VERSION 5.8 ;
BUSBITCHARS "[]" ;
DIVIDERCHAR "/" ;
UNITS
    DATABASE MICRONS 1000 ;
END UNITS

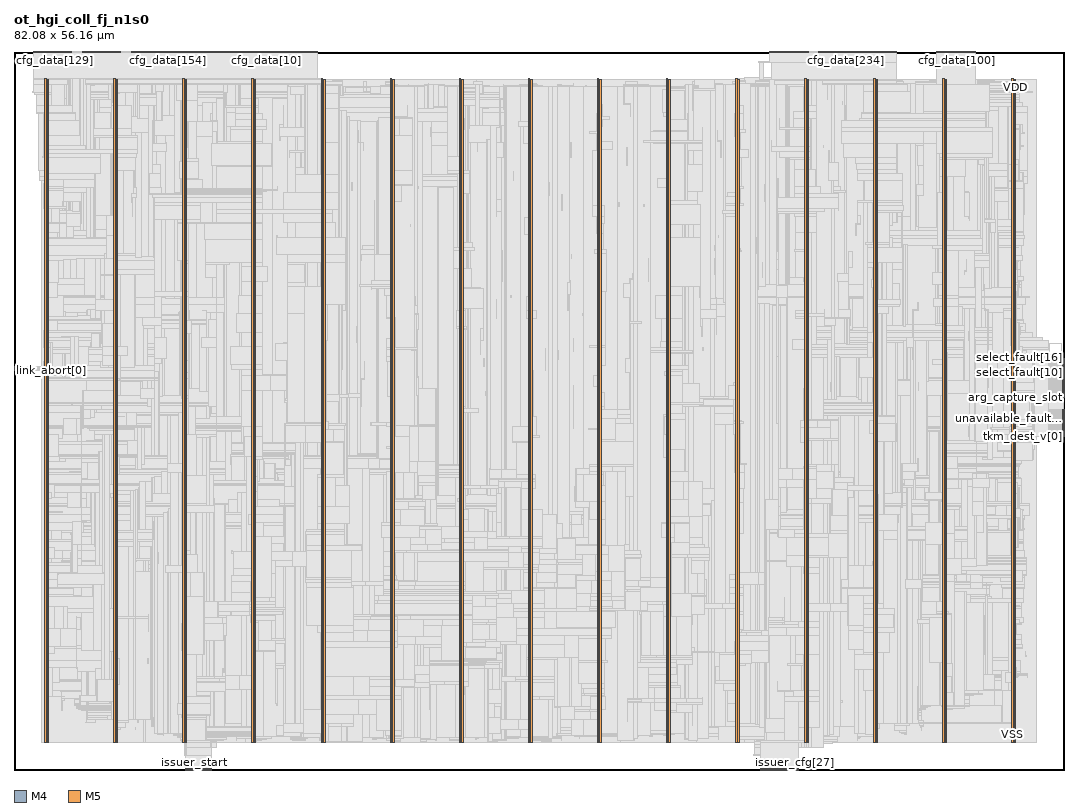
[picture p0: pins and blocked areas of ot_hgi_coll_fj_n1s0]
MACRO ot_hgi_coll_fj_n1s0
  FOREIGN ot_hgi_coll_fj_n1s0 0 0 ;
  CLASS BLOCK ;
  SIZE 82.08 BY 56.16 ;
  PIN arg_capture_slot
    DIRECTION INPUT ;
    USE SIGNAL ;
    PORT
      LAYER M4 ;
        RECT  81.996 29.136 82.08 29.16 ;
    END
  END arg_capture_slot
  PIN capture_fault[0]
    DIRECTION INPUT ;
    USE SIGNAL ;
    PORT
      LAYER M4 ;
        RECT  81.996 29.232 82.08 29.256 ;
    END
  END capture_fault[0]
  PIN capture_fault[1]
    DIRECTION INPUT ;
    USE SIGNAL ;
    PORT
      LAYER M4 ;
        RECT  81.996 29.328 82.08 29.352 ;
    END
  END capture_fault[1]
  PIN capture_fault[2]
    DIRECTION INPUT ;
    USE SIGNAL ;
    PORT
      LAYER M4 ;
        RECT  81.996 29.424 82.08 29.448 ;
    END
  END capture_fault[2]
  PIN capture_fault[3]
    DIRECTION INPUT ;
    USE SIGNAL ;
    PORT
      LAYER M4 ;
        RECT  81.996 29.52 82.08 29.544 ;
    END
  END capture_fault[3]
  PIN capture_fault[4]
    DIRECTION INPUT ;
    USE SIGNAL ;
    PORT
      LAYER M4 ;
        RECT  81.996 29.616 82.08 29.64 ;
    END
  END capture_fault[4]
  PIN capture_fault[5]
    DIRECTION INPUT ;
    USE SIGNAL ;
    PORT
      LAYER M4 ;
        RECT  81.996 29.712 82.08 29.736 ;
    END
  END capture_fault[5]
  PIN capture_fault[6]
    DIRECTION INPUT ;
    USE SIGNAL ;
    PORT
      LAYER M4 ;
        RECT  81.996 29.808 82.08 29.832 ;
    END
  END capture_fault[6]
  PIN capture_fault[7]
    DIRECTION INPUT ;
    USE SIGNAL ;
    PORT
      LAYER M4 ;
        RECT  81.996 29.904 82.08 29.928 ;
    END
  END capture_fault[7]
  PIN cfg_addr[0]
    DIRECTION INPUT ;
    USE SIGNAL ;
    PORT
      LAYER M5 ;
        RECT  17.616 56.076 17.64 56.16 ;
    END
  END cfg_addr[0]
  PIN cfg_addr[10]
    DIRECTION INPUT ;
    USE SIGNAL ;
    PORT
      LAYER M5 ;
        RECT  18.576 56.076 18.6 56.16 ;
    END
  END cfg_addr[10]
  PIN cfg_addr[11]
    DIRECTION INPUT ;
    USE SIGNAL ;
    PORT
      LAYER M5 ;
        RECT  18.672 56.076 18.696 56.16 ;
    END
  END cfg_addr[11]
  PIN cfg_addr[1]
    DIRECTION INPUT ;
    USE SIGNAL ;
    PORT
      LAYER M5 ;
        RECT  17.712 56.076 17.736 56.16 ;
    END
  END cfg_addr[1]
  PIN cfg_addr[2]
    DIRECTION INPUT ;
    USE SIGNAL ;
    PORT
      LAYER M5 ;
        RECT  17.808 56.076 17.832 56.16 ;
    END
  END cfg_addr[2]
  PIN cfg_addr[3]
    DIRECTION INPUT ;
    USE SIGNAL ;
    PORT
      LAYER M5 ;
        RECT  17.904 56.076 17.928 56.16 ;
    END
  END cfg_addr[3]
  PIN cfg_addr[4]
    DIRECTION INPUT ;
    USE SIGNAL ;
    PORT
      LAYER M5 ;
        RECT  18 56.076 18.024 56.16 ;
    END
  END cfg_addr[4]
  PIN cfg_addr[5]
    DIRECTION INPUT ;
    USE SIGNAL ;
    PORT
      LAYER M5 ;
        RECT  18.096 56.076 18.12 56.16 ;
    END
  END cfg_addr[5]
  PIN cfg_addr[6]
    DIRECTION INPUT ;
    USE SIGNAL ;
    PORT
      LAYER M5 ;
        RECT  18.192 56.076 18.216 56.16 ;
    END
  END cfg_addr[6]
  PIN cfg_addr[7]
    DIRECTION INPUT ;
    USE SIGNAL ;
    PORT
      LAYER M5 ;
        RECT  18.288 56.076 18.312 56.16 ;
    END
  END cfg_addr[7]
  PIN cfg_addr[8]
    DIRECTION INPUT ;
    USE SIGNAL ;
    PORT
      LAYER M5 ;
        RECT  18.384 56.076 18.408 56.16 ;
    END
  END cfg_addr[8]
  PIN cfg_addr[9]
    DIRECTION INPUT ;
    USE SIGNAL ;
    PORT
      LAYER M5 ;
        RECT  18.48 56.076 18.504 56.16 ;
    END
  END cfg_addr[9]
  PIN cfg_data[0]
    DIRECTION INPUT ;
    USE SIGNAL ;
    PORT
      LAYER M5 ;
        RECT  18.768 56.076 18.792 56.16 ;
    END
  END cfg_data[0]
  PIN cfg_data[100]
    DIRECTION INPUT ;
    USE SIGNAL ;
    PORT
      LAYER M5 ;
        RECT  73.68 56.076 73.704 56.16 ;
    END
  END cfg_data[100]
  PIN cfg_data[101]
    DIRECTION INPUT ;
    USE SIGNAL ;
    PORT
      LAYER M5 ;
        RECT  73.776 56.076 73.8 56.16 ;
    END
  END cfg_data[101]
  PIN cfg_data[102]
    DIRECTION INPUT ;
    USE SIGNAL ;
    PORT
      LAYER M5 ;
        RECT  73.872 56.076 73.896 56.16 ;
    END
  END cfg_data[102]
  PIN cfg_data[103]
    DIRECTION INPUT ;
    USE SIGNAL ;
    PORT
      LAYER M5 ;
        RECT  73.968 56.076 73.992 56.16 ;
    END
  END cfg_data[103]
  PIN cfg_data[104]
    DIRECTION INPUT ;
    USE SIGNAL ;
    PORT
      LAYER M5 ;
        RECT  74.064 56.076 74.088 56.16 ;
    END
  END cfg_data[104]
  PIN cfg_data[105]
    DIRECTION INPUT ;
    USE SIGNAL ;
    PORT
      LAYER M5 ;
        RECT  74.16 56.076 74.184 56.16 ;
    END
  END cfg_data[105]
  PIN cfg_data[106]
    DIRECTION INPUT ;
    USE SIGNAL ;
    PORT
      LAYER M5 ;
        RECT  74.256 56.076 74.28 56.16 ;
    END
  END cfg_data[106]
  PIN cfg_data[107]
    DIRECTION INPUT ;
    USE SIGNAL ;
    PORT
      LAYER M5 ;
        RECT  74.352 56.076 74.376 56.16 ;
    END
  END cfg_data[107]
  PIN cfg_data[108]
    DIRECTION INPUT ;
    USE SIGNAL ;
    PORT
      LAYER M5 ;
        RECT  74.448 56.076 74.472 56.16 ;
    END
  END cfg_data[108]
  PIN cfg_data[109]
    DIRECTION INPUT ;
    USE SIGNAL ;
    PORT
      LAYER M5 ;
        RECT  74.544 56.076 74.568 56.16 ;
    END
  END cfg_data[109]
  PIN cfg_data[10]
    DIRECTION INPUT ;
    USE SIGNAL ;
    PORT
      LAYER M5 ;
        RECT  19.728 56.076 19.752 56.16 ;
    END
  END cfg_data[10]
  PIN cfg_data[110]
    DIRECTION INPUT ;
    USE SIGNAL ;
    PORT
      LAYER M5 ;
        RECT  74.64 56.076 74.664 56.16 ;
    END
  END cfg_data[110]
  PIN cfg_data[111]
    DIRECTION INPUT ;
    USE SIGNAL ;
    PORT
      LAYER M5 ;
        RECT  74.736 56.076 74.76 56.16 ;
    END
  END cfg_data[111]
  PIN cfg_data[112]
    DIRECTION INPUT ;
    USE SIGNAL ;
    PORT
      LAYER M5 ;
        RECT  74.832 56.076 74.856 56.16 ;
    END
  END cfg_data[112]
  PIN cfg_data[113]
    DIRECTION INPUT ;
    USE SIGNAL ;
    PORT
      LAYER M5 ;
        RECT  74.928 56.076 74.952 56.16 ;
    END
  END cfg_data[113]
  PIN cfg_data[114]
    DIRECTION INPUT ;
    USE SIGNAL ;
    PORT
      LAYER M5 ;
        RECT  75.024 56.076 75.048 56.16 ;
    END
  END cfg_data[114]
  PIN cfg_data[115]
    DIRECTION INPUT ;
    USE SIGNAL ;
    PORT
      LAYER M5 ;
        RECT  75.12 56.076 75.144 56.16 ;
    END
  END cfg_data[115]
  PIN cfg_data[116]
    DIRECTION INPUT ;
    USE SIGNAL ;
    PORT
      LAYER M5 ;
        RECT  1.488 56.076 1.512 56.16 ;
    END
  END cfg_data[116]
  PIN cfg_data[117]
    DIRECTION INPUT ;
    USE SIGNAL ;
    PORT
      LAYER M5 ;
        RECT  1.584 56.076 1.608 56.16 ;
    END
  END cfg_data[117]
  PIN cfg_data[118]
    DIRECTION INPUT ;
    USE SIGNAL ;
    PORT
      LAYER M5 ;
        RECT  1.68 56.076 1.704 56.16 ;
    END
  END cfg_data[118]
  PIN cfg_data[119]
    DIRECTION INPUT ;
    USE SIGNAL ;
    PORT
      LAYER M5 ;
        RECT  1.776 56.076 1.8 56.16 ;
    END
  END cfg_data[119]
  PIN cfg_data[11]
    DIRECTION INPUT ;
    USE SIGNAL ;
    PORT
      LAYER M5 ;
        RECT  19.824 56.076 19.848 56.16 ;
    END
  END cfg_data[11]
  PIN cfg_data[120]
    DIRECTION INPUT ;
    USE SIGNAL ;
    PORT
      LAYER M5 ;
        RECT  1.872 56.076 1.896 56.16 ;
    END
  END cfg_data[120]
  PIN cfg_data[121]
    DIRECTION INPUT ;
    USE SIGNAL ;
    PORT
      LAYER M5 ;
        RECT  1.968 56.076 1.992 56.16 ;
    END
  END cfg_data[121]
  PIN cfg_data[122]
    DIRECTION INPUT ;
    USE SIGNAL ;
    PORT
      LAYER M5 ;
        RECT  2.064 56.076 2.088 56.16 ;
    END
  END cfg_data[122]
  PIN cfg_data[123]
    DIRECTION INPUT ;
    USE SIGNAL ;
    PORT
      LAYER M5 ;
        RECT  2.16 56.076 2.184 56.16 ;
    END
  END cfg_data[123]
  PIN cfg_data[124]
    DIRECTION INPUT ;
    USE SIGNAL ;
    PORT
      LAYER M5 ;
        RECT  2.256 56.076 2.28 56.16 ;
    END
  END cfg_data[124]
  PIN cfg_data[125]
    DIRECTION INPUT ;
    USE SIGNAL ;
    PORT
      LAYER M5 ;
        RECT  2.352 56.076 2.376 56.16 ;
    END
  END cfg_data[125]
  PIN cfg_data[126]
    DIRECTION INPUT ;
    USE SIGNAL ;
    PORT
      LAYER M5 ;
        RECT  2.448 56.076 2.472 56.16 ;
    END
  END cfg_data[126]
  PIN cfg_data[127]
    DIRECTION INPUT ;
    USE SIGNAL ;
    PORT
      LAYER M5 ;
        RECT  2.544 56.076 2.568 56.16 ;
    END
  END cfg_data[127]
  PIN cfg_data[128]
    DIRECTION INPUT ;
    USE SIGNAL ;
    PORT
      LAYER M5 ;
        RECT  2.64 56.076 2.664 56.16 ;
    END
  END cfg_data[128]
  PIN cfg_data[129]
    DIRECTION INPUT ;
    USE SIGNAL ;
    PORT
      LAYER M5 ;
        RECT  2.736 56.076 2.76 56.16 ;
    END
  END cfg_data[129]
  PIN cfg_data[12]
    DIRECTION INPUT ;
    USE SIGNAL ;
    PORT
      LAYER M5 ;
        RECT  19.92 56.076 19.944 56.16 ;
    END
  END cfg_data[12]
  PIN cfg_data[130]
    DIRECTION INPUT ;
    USE SIGNAL ;
    PORT
      LAYER M5 ;
        RECT  2.832 56.076 2.856 56.16 ;
    END
  END cfg_data[130]
  PIN cfg_data[131]
    DIRECTION INPUT ;
    USE SIGNAL ;
    PORT
      LAYER M5 ;
        RECT  2.928 56.076 2.952 56.16 ;
    END
  END cfg_data[131]
  PIN cfg_data[132]
    DIRECTION INPUT ;
    USE SIGNAL ;
    PORT
      LAYER M5 ;
        RECT  3.024 56.076 3.048 56.16 ;
    END
  END cfg_data[132]
  PIN cfg_data[133]
    DIRECTION INPUT ;
    USE SIGNAL ;
    PORT
      LAYER M5 ;
        RECT  3.12 56.076 3.144 56.16 ;
    END
  END cfg_data[133]
  PIN cfg_data[134]
    DIRECTION INPUT ;
    USE SIGNAL ;
    PORT
      LAYER M5 ;
        RECT  3.216 56.076 3.24 56.16 ;
    END
  END cfg_data[134]
  PIN cfg_data[135]
    DIRECTION INPUT ;
    USE SIGNAL ;
    PORT
      LAYER M5 ;
        RECT  3.312 56.076 3.336 56.16 ;
    END
  END cfg_data[135]
  PIN cfg_data[136]
    DIRECTION INPUT ;
    USE SIGNAL ;
    PORT
      LAYER M5 ;
        RECT  3.408 56.076 3.432 56.16 ;
    END
  END cfg_data[136]
  PIN cfg_data[137]
    DIRECTION INPUT ;
    USE SIGNAL ;
    PORT
      LAYER M5 ;
        RECT  3.504 56.076 3.528 56.16 ;
    END
  END cfg_data[137]
  PIN cfg_data[138]
    DIRECTION INPUT ;
    USE SIGNAL ;
    PORT
      LAYER M5 ;
        RECT  3.6 56.076 3.624 56.16 ;
    END
  END cfg_data[138]
  PIN cfg_data[139]
    DIRECTION INPUT ;
    USE SIGNAL ;
    PORT
      LAYER M5 ;
        RECT  3.696 56.076 3.72 56.16 ;
    END
  END cfg_data[139]
  PIN cfg_data[13]
    DIRECTION INPUT ;
    USE SIGNAL ;
    PORT
      LAYER M5 ;
        RECT  20.016 56.076 20.04 56.16 ;
    END
  END cfg_data[13]
  PIN cfg_data[140]
    DIRECTION INPUT ;
    USE SIGNAL ;
    PORT
      LAYER M5 ;
        RECT  3.792 56.076 3.816 56.16 ;
    END
  END cfg_data[140]
  PIN cfg_data[141]
    DIRECTION INPUT ;
    USE SIGNAL ;
    PORT
      LAYER M5 ;
        RECT  3.888 56.076 3.912 56.16 ;
    END
  END cfg_data[141]
  PIN cfg_data[142]
    DIRECTION INPUT ;
    USE SIGNAL ;
    PORT
      LAYER M5 ;
        RECT  3.984 56.076 4.008 56.16 ;
    END
  END cfg_data[142]
  PIN cfg_data[143]
    DIRECTION INPUT ;
    USE SIGNAL ;
    PORT
      LAYER M5 ;
        RECT  4.08 56.076 4.104 56.16 ;
    END
  END cfg_data[143]
  PIN cfg_data[144]
    DIRECTION INPUT ;
    USE SIGNAL ;
    PORT
      LAYER M5 ;
        RECT  4.176 56.076 4.2 56.16 ;
    END
  END cfg_data[144]
  PIN cfg_data[145]
    DIRECTION INPUT ;
    USE SIGNAL ;
    PORT
      LAYER M5 ;
        RECT  4.272 56.076 4.296 56.16 ;
    END
  END cfg_data[145]
  PIN cfg_data[146]
    DIRECTION INPUT ;
    USE SIGNAL ;
    PORT
      LAYER M5 ;
        RECT  4.368 56.076 4.392 56.16 ;
    END
  END cfg_data[146]
  PIN cfg_data[147]
    DIRECTION INPUT ;
    USE SIGNAL ;
    PORT
      LAYER M5 ;
        RECT  4.464 56.076 4.488 56.16 ;
    END
  END cfg_data[147]
  PIN cfg_data[148]
    DIRECTION INPUT ;
    USE SIGNAL ;
    PORT
      LAYER M5 ;
        RECT  11.472 56.076 11.496 56.16 ;
    END
  END cfg_data[148]
  PIN cfg_data[149]
    DIRECTION INPUT ;
    USE SIGNAL ;
    PORT
      LAYER M5 ;
        RECT  11.568 56.076 11.592 56.16 ;
    END
  END cfg_data[149]
  PIN cfg_data[14]
    DIRECTION INPUT ;
    USE SIGNAL ;
    PORT
      LAYER M5 ;
        RECT  20.112 56.076 20.136 56.16 ;
    END
  END cfg_data[14]
  PIN cfg_data[150]
    DIRECTION INPUT ;
    USE SIGNAL ;
    PORT
      LAYER M5 ;
        RECT  11.664 56.076 11.688 56.16 ;
    END
  END cfg_data[150]
  PIN cfg_data[151]
    DIRECTION INPUT ;
    USE SIGNAL ;
    PORT
      LAYER M5 ;
        RECT  11.76 56.076 11.784 56.16 ;
    END
  END cfg_data[151]
  PIN cfg_data[152]
    DIRECTION INPUT ;
    USE SIGNAL ;
    PORT
      LAYER M5 ;
        RECT  11.856 56.076 11.88 56.16 ;
    END
  END cfg_data[152]
  PIN cfg_data[153]
    DIRECTION INPUT ;
    USE SIGNAL ;
    PORT
      LAYER M5 ;
        RECT  11.952 56.076 11.976 56.16 ;
    END
  END cfg_data[153]
  PIN cfg_data[154]
    DIRECTION INPUT ;
    USE SIGNAL ;
    PORT
      LAYER M5 ;
        RECT  12.048 56.076 12.072 56.16 ;
    END
  END cfg_data[154]
  PIN cfg_data[155]
    DIRECTION INPUT ;
    USE SIGNAL ;
    PORT
      LAYER M5 ;
        RECT  12.144 56.076 12.168 56.16 ;
    END
  END cfg_data[155]
  PIN cfg_data[156]
    DIRECTION INPUT ;
    USE SIGNAL ;
    PORT
      LAYER M5 ;
        RECT  12.24 56.076 12.264 56.16 ;
    END
  END cfg_data[156]
  PIN cfg_data[157]
    DIRECTION INPUT ;
    USE SIGNAL ;
    PORT
      LAYER M5 ;
        RECT  12.336 56.076 12.36 56.16 ;
    END
  END cfg_data[157]
  PIN cfg_data[158]
    DIRECTION INPUT ;
    USE SIGNAL ;
    PORT
      LAYER M5 ;
        RECT  12.432 56.076 12.456 56.16 ;
    END
  END cfg_data[158]
  PIN cfg_data[159]
    DIRECTION INPUT ;
    USE SIGNAL ;
    PORT
      LAYER M5 ;
        RECT  12.528 56.076 12.552 56.16 ;
    END
  END cfg_data[159]
  PIN cfg_data[15]
    DIRECTION INPUT ;
    USE SIGNAL ;
    PORT
      LAYER M5 ;
        RECT  20.208 56.076 20.232 56.16 ;
    END
  END cfg_data[15]
  PIN cfg_data[160]
    DIRECTION INPUT ;
    USE SIGNAL ;
    PORT
      LAYER M5 ;
        RECT  12.624 56.076 12.648 56.16 ;
    END
  END cfg_data[160]
  PIN cfg_data[161]
    DIRECTION INPUT ;
    USE SIGNAL ;
    PORT
      LAYER M5 ;
        RECT  12.72 56.076 12.744 56.16 ;
    END
  END cfg_data[161]
  PIN cfg_data[162]
    DIRECTION INPUT ;
    USE SIGNAL ;
    PORT
      LAYER M5 ;
        RECT  12.816 56.076 12.84 56.16 ;
    END
  END cfg_data[162]
  PIN cfg_data[163]
    DIRECTION INPUT ;
    USE SIGNAL ;
    PORT
      LAYER M5 ;
        RECT  12.912 56.076 12.936 56.16 ;
    END
  END cfg_data[163]
  PIN cfg_data[164]
    DIRECTION INPUT ;
    USE SIGNAL ;
    PORT
      LAYER M5 ;
        RECT  13.008 56.076 13.032 56.16 ;
    END
  END cfg_data[164]
  PIN cfg_data[165]
    DIRECTION INPUT ;
    USE SIGNAL ;
    PORT
      LAYER M5 ;
        RECT  13.104 56.076 13.128 56.16 ;
    END
  END cfg_data[165]
  PIN cfg_data[166]
    DIRECTION INPUT ;
    USE SIGNAL ;
    PORT
      LAYER M5 ;
        RECT  13.2 56.076 13.224 56.16 ;
    END
  END cfg_data[166]
  PIN cfg_data[167]
    DIRECTION INPUT ;
    USE SIGNAL ;
    PORT
      LAYER M5 ;
        RECT  13.296 56.076 13.32 56.16 ;
    END
  END cfg_data[167]
  PIN cfg_data[168]
    DIRECTION INPUT ;
    USE SIGNAL ;
    PORT
      LAYER M5 ;
        RECT  13.392 56.076 13.416 56.16 ;
    END
  END cfg_data[168]
  PIN cfg_data[169]
    DIRECTION INPUT ;
    USE SIGNAL ;
    PORT
      LAYER M5 ;
        RECT  13.488 56.076 13.512 56.16 ;
    END
  END cfg_data[169]
  PIN cfg_data[16]
    DIRECTION INPUT ;
    USE SIGNAL ;
    PORT
      LAYER M5 ;
        RECT  20.304 56.076 20.328 56.16 ;
    END
  END cfg_data[16]
  PIN cfg_data[170]
    DIRECTION INPUT ;
    USE SIGNAL ;
    PORT
      LAYER M5 ;
        RECT  13.584 56.076 13.608 56.16 ;
    END
  END cfg_data[170]
  PIN cfg_data[171]
    DIRECTION INPUT ;
    USE SIGNAL ;
    PORT
      LAYER M5 ;
        RECT  13.68 56.076 13.704 56.16 ;
    END
  END cfg_data[171]
  PIN cfg_data[172]
    DIRECTION INPUT ;
    USE SIGNAL ;
    PORT
      LAYER M5 ;
        RECT  13.776 56.076 13.8 56.16 ;
    END
  END cfg_data[172]
  PIN cfg_data[173]
    DIRECTION INPUT ;
    USE SIGNAL ;
    PORT
      LAYER M5 ;
        RECT  13.872 56.076 13.896 56.16 ;
    END
  END cfg_data[173]
  PIN cfg_data[174]
    DIRECTION INPUT ;
    USE SIGNAL ;
    PORT
      LAYER M5 ;
        RECT  13.968 56.076 13.992 56.16 ;
    END
  END cfg_data[174]
  PIN cfg_data[175]
    DIRECTION INPUT ;
    USE SIGNAL ;
    PORT
      LAYER M5 ;
        RECT  14.064 56.076 14.088 56.16 ;
    END
  END cfg_data[175]
  PIN cfg_data[176]
    DIRECTION INPUT ;
    USE SIGNAL ;
    PORT
      LAYER M5 ;
        RECT  14.16 56.076 14.184 56.16 ;
    END
  END cfg_data[176]
  PIN cfg_data[177]
    DIRECTION INPUT ;
    USE SIGNAL ;
    PORT
      LAYER M5 ;
        RECT  14.256 56.076 14.28 56.16 ;
    END
  END cfg_data[177]
  PIN cfg_data[178]
    DIRECTION INPUT ;
    USE SIGNAL ;
    PORT
      LAYER M5 ;
        RECT  14.352 56.076 14.376 56.16 ;
    END
  END cfg_data[178]
  PIN cfg_data[179]
    DIRECTION INPUT ;
    USE SIGNAL ;
    PORT
      LAYER M5 ;
        RECT  14.448 56.076 14.472 56.16 ;
    END
  END cfg_data[179]
  PIN cfg_data[17]
    DIRECTION INPUT ;
    USE SIGNAL ;
    PORT
      LAYER M5 ;
        RECT  20.4 56.076 20.424 56.16 ;
    END
  END cfg_data[17]
  PIN cfg_data[180]
    DIRECTION INPUT ;
    USE SIGNAL ;
    PORT
      LAYER M5 ;
        RECT  59.088 56.076 59.112 56.16 ;
    END
  END cfg_data[180]
  PIN cfg_data[181]
    DIRECTION INPUT ;
    USE SIGNAL ;
    PORT
      LAYER M5 ;
        RECT  59.184 56.076 59.208 56.16 ;
    END
  END cfg_data[181]
  PIN cfg_data[182]
    DIRECTION INPUT ;
    USE SIGNAL ;
    PORT
      LAYER M5 ;
        RECT  59.28 56.076 59.304 56.16 ;
    END
  END cfg_data[182]
  PIN cfg_data[183]
    DIRECTION INPUT ;
    USE SIGNAL ;
    PORT
      LAYER M5 ;
        RECT  59.376 56.076 59.4 56.16 ;
    END
  END cfg_data[183]
  PIN cfg_data[184]
    DIRECTION INPUT ;
    USE SIGNAL ;
    PORT
      LAYER M5 ;
        RECT  59.472 56.076 59.496 56.16 ;
    END
  END cfg_data[184]
  PIN cfg_data[185]
    DIRECTION INPUT ;
    USE SIGNAL ;
    PORT
      LAYER M5 ;
        RECT  59.568 56.076 59.592 56.16 ;
    END
  END cfg_data[185]
  PIN cfg_data[186]
    DIRECTION INPUT ;
    USE SIGNAL ;
    PORT
      LAYER M5 ;
        RECT  59.664 56.076 59.688 56.16 ;
    END
  END cfg_data[186]
  PIN cfg_data[187]
    DIRECTION INPUT ;
    USE SIGNAL ;
    PORT
      LAYER M5 ;
        RECT  59.76 56.076 59.784 56.16 ;
    END
  END cfg_data[187]
  PIN cfg_data[188]
    DIRECTION INPUT ;
    USE SIGNAL ;
    PORT
      LAYER M5 ;
        RECT  59.856 56.076 59.88 56.16 ;
    END
  END cfg_data[188]
  PIN cfg_data[189]
    DIRECTION INPUT ;
    USE SIGNAL ;
    PORT
      LAYER M5 ;
        RECT  59.952 56.076 59.976 56.16 ;
    END
  END cfg_data[189]
  PIN cfg_data[18]
    DIRECTION INPUT ;
    USE SIGNAL ;
    PORT
      LAYER M5 ;
        RECT  20.496 56.076 20.52 56.16 ;
    END
  END cfg_data[18]
  PIN cfg_data[190]
    DIRECTION INPUT ;
    USE SIGNAL ;
    PORT
      LAYER M5 ;
        RECT  60.048 56.076 60.072 56.16 ;
    END
  END cfg_data[190]
  PIN cfg_data[191]
    DIRECTION INPUT ;
    USE SIGNAL ;
    PORT
      LAYER M5 ;
        RECT  60.144 56.076 60.168 56.16 ;
    END
  END cfg_data[191]
  PIN cfg_data[192]
    DIRECTION INPUT ;
    USE SIGNAL ;
    PORT
      LAYER M5 ;
        RECT  60.24 56.076 60.264 56.16 ;
    END
  END cfg_data[192]
  PIN cfg_data[193]
    DIRECTION INPUT ;
    USE SIGNAL ;
    PORT
      LAYER M5 ;
        RECT  60.336 56.076 60.36 56.16 ;
    END
  END cfg_data[193]
  PIN cfg_data[194]
    DIRECTION INPUT ;
    USE SIGNAL ;
    PORT
      LAYER M5 ;
        RECT  60.432 56.076 60.456 56.16 ;
    END
  END cfg_data[194]
  PIN cfg_data[195]
    DIRECTION INPUT ;
    USE SIGNAL ;
    PORT
      LAYER M5 ;
        RECT  60.528 56.076 60.552 56.16 ;
    END
  END cfg_data[195]
  PIN cfg_data[196]
    DIRECTION INPUT ;
    USE SIGNAL ;
    PORT
      LAYER M5 ;
        RECT  60.624 56.076 60.648 56.16 ;
    END
  END cfg_data[196]
  PIN cfg_data[197]
    DIRECTION INPUT ;
    USE SIGNAL ;
    PORT
      LAYER M5 ;
        RECT  60.72 56.076 60.744 56.16 ;
    END
  END cfg_data[197]
  PIN cfg_data[198]
    DIRECTION INPUT ;
    USE SIGNAL ;
    PORT
      LAYER M5 ;
        RECT  60.816 56.076 60.84 56.16 ;
    END
  END cfg_data[198]
  PIN cfg_data[199]
    DIRECTION INPUT ;
    USE SIGNAL ;
    PORT
      LAYER M5 ;
        RECT  60.912 56.076 60.936 56.16 ;
    END
  END cfg_data[199]
  PIN cfg_data[19]
    DIRECTION INPUT ;
    USE SIGNAL ;
    PORT
      LAYER M5 ;
        RECT  20.592 56.076 20.616 56.16 ;
    END
  END cfg_data[19]
  PIN cfg_data[1]
    DIRECTION INPUT ;
    USE SIGNAL ;
    PORT
      LAYER M5 ;
        RECT  18.864 56.076 18.888 56.16 ;
    END
  END cfg_data[1]
  PIN cfg_data[200]
    DIRECTION INPUT ;
    USE SIGNAL ;
    PORT
      LAYER M5 ;
        RECT  61.008 56.076 61.032 56.16 ;
    END
  END cfg_data[200]
  PIN cfg_data[201]
    DIRECTION INPUT ;
    USE SIGNAL ;
    PORT
      LAYER M5 ;
        RECT  61.104 56.076 61.128 56.16 ;
    END
  END cfg_data[201]
  PIN cfg_data[202]
    DIRECTION INPUT ;
    USE SIGNAL ;
    PORT
      LAYER M5 ;
        RECT  61.2 56.076 61.224 56.16 ;
    END
  END cfg_data[202]
  PIN cfg_data[203]
    DIRECTION INPUT ;
    USE SIGNAL ;
    PORT
      LAYER M5 ;
        RECT  61.296 56.076 61.32 56.16 ;
    END
  END cfg_data[203]
  PIN cfg_data[204]
    DIRECTION INPUT ;
    USE SIGNAL ;
    PORT
      LAYER M5 ;
        RECT  61.392 56.076 61.416 56.16 ;
    END
  END cfg_data[204]
  PIN cfg_data[205]
    DIRECTION INPUT ;
    USE SIGNAL ;
    PORT
      LAYER M5 ;
        RECT  61.488 56.076 61.512 56.16 ;
    END
  END cfg_data[205]
  PIN cfg_data[206]
    DIRECTION INPUT ;
    USE SIGNAL ;
    PORT
      LAYER M5 ;
        RECT  61.584 56.076 61.608 56.16 ;
    END
  END cfg_data[206]
  PIN cfg_data[207]
    DIRECTION INPUT ;
    USE SIGNAL ;
    PORT
      LAYER M5 ;
        RECT  61.68 56.076 61.704 56.16 ;
    END
  END cfg_data[207]
  PIN cfg_data[208]
    DIRECTION INPUT ;
    USE SIGNAL ;
    PORT
      LAYER M5 ;
        RECT  61.776 56.076 61.8 56.16 ;
    END
  END cfg_data[208]
  PIN cfg_data[209]
    DIRECTION INPUT ;
    USE SIGNAL ;
    PORT
      LAYER M5 ;
        RECT  61.872 56.076 61.896 56.16 ;
    END
  END cfg_data[209]
  PIN cfg_data[20]
    DIRECTION INPUT ;
    USE SIGNAL ;
    PORT
      LAYER M5 ;
        RECT  14.544 56.076 14.568 56.16 ;
    END
  END cfg_data[20]
  PIN cfg_data[210]
    DIRECTION INPUT ;
    USE SIGNAL ;
    PORT
      LAYER M5 ;
        RECT  61.968 56.076 61.992 56.16 ;
    END
  END cfg_data[210]
  PIN cfg_data[211]
    DIRECTION INPUT ;
    USE SIGNAL ;
    PORT
      LAYER M5 ;
        RECT  62.064 56.076 62.088 56.16 ;
    END
  END cfg_data[211]
  PIN cfg_data[212]
    DIRECTION INPUT ;
    USE SIGNAL ;
    PORT
      LAYER M5 ;
        RECT  62.928 56.076 62.952 56.16 ;
    END
  END cfg_data[212]
  PIN cfg_data[213]
    DIRECTION INPUT ;
    USE SIGNAL ;
    PORT
      LAYER M5 ;
        RECT  63.024 56.076 63.048 56.16 ;
    END
  END cfg_data[213]
  PIN cfg_data[214]
    DIRECTION INPUT ;
    USE SIGNAL ;
    PORT
      LAYER M5 ;
        RECT  63.12 56.076 63.144 56.16 ;
    END
  END cfg_data[214]
  PIN cfg_data[215]
    DIRECTION INPUT ;
    USE SIGNAL ;
    PORT
      LAYER M5 ;
        RECT  63.216 56.076 63.24 56.16 ;
    END
  END cfg_data[215]
  PIN cfg_data[216]
    DIRECTION INPUT ;
    USE SIGNAL ;
    PORT
      LAYER M5 ;
        RECT  63.312 56.076 63.336 56.16 ;
    END
  END cfg_data[216]
  PIN cfg_data[217]
    DIRECTION INPUT ;
    USE SIGNAL ;
    PORT
      LAYER M5 ;
        RECT  63.408 56.076 63.432 56.16 ;
    END
  END cfg_data[217]
  PIN cfg_data[218]
    DIRECTION INPUT ;
    USE SIGNAL ;
    PORT
      LAYER M5 ;
        RECT  63.504 56.076 63.528 56.16 ;
    END
  END cfg_data[218]
  PIN cfg_data[219]
    DIRECTION INPUT ;
    USE SIGNAL ;
    PORT
      LAYER M5 ;
        RECT  63.6 56.076 63.624 56.16 ;
    END
  END cfg_data[219]
  PIN cfg_data[21]
    DIRECTION INPUT ;
    USE SIGNAL ;
    PORT
      LAYER M5 ;
        RECT  14.64 56.076 14.664 56.16 ;
    END
  END cfg_data[21]
  PIN cfg_data[220]
    DIRECTION INPUT ;
    USE SIGNAL ;
    PORT
      LAYER M5 ;
        RECT  63.696 56.076 63.72 56.16 ;
    END
  END cfg_data[220]
  PIN cfg_data[221]
    DIRECTION INPUT ;
    USE SIGNAL ;
    PORT
      LAYER M5 ;
        RECT  63.792 56.076 63.816 56.16 ;
    END
  END cfg_data[221]
  PIN cfg_data[222]
    DIRECTION INPUT ;
    USE SIGNAL ;
    PORT
      LAYER M5 ;
        RECT  63.888 56.076 63.912 56.16 ;
    END
  END cfg_data[222]
  PIN cfg_data[223]
    DIRECTION INPUT ;
    USE SIGNAL ;
    PORT
      LAYER M5 ;
        RECT  63.984 56.076 64.008 56.16 ;
    END
  END cfg_data[223]
  PIN cfg_data[224]
    DIRECTION INPUT ;
    USE SIGNAL ;
    PORT
      LAYER M5 ;
        RECT  64.08 56.076 64.104 56.16 ;
    END
  END cfg_data[224]
  PIN cfg_data[225]
    DIRECTION INPUT ;
    USE SIGNAL ;
    PORT
      LAYER M5 ;
        RECT  64.176 56.076 64.2 56.16 ;
    END
  END cfg_data[225]
  PIN cfg_data[226]
    DIRECTION INPUT ;
    USE SIGNAL ;
    PORT
      LAYER M5 ;
        RECT  64.272 56.076 64.296 56.16 ;
    END
  END cfg_data[226]
  PIN cfg_data[227]
    DIRECTION INPUT ;
    USE SIGNAL ;
    PORT
      LAYER M5 ;
        RECT  64.368 56.076 64.392 56.16 ;
    END
  END cfg_data[227]
  PIN cfg_data[228]
    DIRECTION INPUT ;
    USE SIGNAL ;
    PORT
      LAYER M5 ;
        RECT  64.464 56.076 64.488 56.16 ;
    END
  END cfg_data[228]
  PIN cfg_data[229]
    DIRECTION INPUT ;
    USE SIGNAL ;
    PORT
      LAYER M5 ;
        RECT  64.56 56.076 64.584 56.16 ;
    END
  END cfg_data[229]
  PIN cfg_data[22]
    DIRECTION INPUT ;
    USE SIGNAL ;
    PORT
      LAYER M5 ;
        RECT  14.736 56.076 14.76 56.16 ;
    END
  END cfg_data[22]
  PIN cfg_data[230]
    DIRECTION INPUT ;
    USE SIGNAL ;
    PORT
      LAYER M5 ;
        RECT  64.656 56.076 64.68 56.16 ;
    END
  END cfg_data[230]
  PIN cfg_data[231]
    DIRECTION INPUT ;
    USE SIGNAL ;
    PORT
      LAYER M5 ;
        RECT  64.752 56.076 64.776 56.16 ;
    END
  END cfg_data[231]
  PIN cfg_data[232]
    DIRECTION INPUT ;
    USE SIGNAL ;
    PORT
      LAYER M5 ;
        RECT  64.848 56.076 64.872 56.16 ;
    END
  END cfg_data[232]
  PIN cfg_data[233]
    DIRECTION INPUT ;
    USE SIGNAL ;
    PORT
      LAYER M5 ;
        RECT  64.944 56.076 64.968 56.16 ;
    END
  END cfg_data[233]
  PIN cfg_data[234]
    DIRECTION INPUT ;
    USE SIGNAL ;
    PORT
      LAYER M5 ;
        RECT  65.04 56.076 65.064 56.16 ;
    END
  END cfg_data[234]
  PIN cfg_data[235]
    DIRECTION INPUT ;
    USE SIGNAL ;
    PORT
      LAYER M5 ;
        RECT  65.136 56.076 65.16 56.16 ;
    END
  END cfg_data[235]
  PIN cfg_data[236]
    DIRECTION INPUT ;
    USE SIGNAL ;
    PORT
      LAYER M5 ;
        RECT  65.232 56.076 65.256 56.16 ;
    END
  END cfg_data[236]
  PIN cfg_data[237]
    DIRECTION INPUT ;
    USE SIGNAL ;
    PORT
      LAYER M5 ;
        RECT  65.328 56.076 65.352 56.16 ;
    END
  END cfg_data[237]
  PIN cfg_data[238]
    DIRECTION INPUT ;
    USE SIGNAL ;
    PORT
      LAYER M5 ;
        RECT  65.424 56.076 65.448 56.16 ;
    END
  END cfg_data[238]
  PIN cfg_data[239]
    DIRECTION INPUT ;
    USE SIGNAL ;
    PORT
      LAYER M5 ;
        RECT  65.52 56.076 65.544 56.16 ;
    END
  END cfg_data[239]
  PIN cfg_data[23]
    DIRECTION INPUT ;
    USE SIGNAL ;
    PORT
      LAYER M5 ;
        RECT  14.832 56.076 14.856 56.16 ;
    END
  END cfg_data[23]
  PIN cfg_data[240]
    DIRECTION INPUT ;
    USE SIGNAL ;
    PORT
      LAYER M5 ;
        RECT  65.616 56.076 65.64 56.16 ;
    END
  END cfg_data[240]
  PIN cfg_data[241]
    DIRECTION INPUT ;
    USE SIGNAL ;
    PORT
      LAYER M5 ;
        RECT  65.712 56.076 65.736 56.16 ;
    END
  END cfg_data[241]
  PIN cfg_data[242]
    DIRECTION INPUT ;
    USE SIGNAL ;
    PORT
      LAYER M5 ;
        RECT  65.808 56.076 65.832 56.16 ;
    END
  END cfg_data[242]
  PIN cfg_data[243]
    DIRECTION INPUT ;
    USE SIGNAL ;
    PORT
      LAYER M5 ;
        RECT  65.904 56.076 65.928 56.16 ;
    END
  END cfg_data[243]
  PIN cfg_data[244]
    DIRECTION INPUT ;
    USE SIGNAL ;
    PORT
      LAYER M5 ;
        RECT  20.688 56.076 20.712 56.16 ;
    END
  END cfg_data[244]
  PIN cfg_data[245]
    DIRECTION INPUT ;
    USE SIGNAL ;
    PORT
      LAYER M5 ;
        RECT  20.784 56.076 20.808 56.16 ;
    END
  END cfg_data[245]
  PIN cfg_data[246]
    DIRECTION INPUT ;
    USE SIGNAL ;
    PORT
      LAYER M5 ;
        RECT  20.88 56.076 20.904 56.16 ;
    END
  END cfg_data[246]
  PIN cfg_data[247]
    DIRECTION INPUT ;
    USE SIGNAL ;
    PORT
      LAYER M5 ;
        RECT  20.976 56.076 21 56.16 ;
    END
  END cfg_data[247]
  PIN cfg_data[248]
    DIRECTION INPUT ;
    USE SIGNAL ;
    PORT
      LAYER M5 ;
        RECT  21.072 56.076 21.096 56.16 ;
    END
  END cfg_data[248]
  PIN cfg_data[249]
    DIRECTION INPUT ;
    USE SIGNAL ;
    PORT
      LAYER M5 ;
        RECT  21.168 56.076 21.192 56.16 ;
    END
  END cfg_data[249]
  PIN cfg_data[24]
    DIRECTION INPUT ;
    USE SIGNAL ;
    PORT
      LAYER M5 ;
        RECT  14.928 56.076 14.952 56.16 ;
    END
  END cfg_data[24]
  PIN cfg_data[250]
    DIRECTION INPUT ;
    USE SIGNAL ;
    PORT
      LAYER M5 ;
        RECT  21.264 56.076 21.288 56.16 ;
    END
  END cfg_data[250]
  PIN cfg_data[251]
    DIRECTION INPUT ;
    USE SIGNAL ;
    PORT
      LAYER M5 ;
        RECT  21.36 56.076 21.384 56.16 ;
    END
  END cfg_data[251]
  PIN cfg_data[252]
    DIRECTION INPUT ;
    USE SIGNAL ;
    PORT
      LAYER M5 ;
        RECT  21.456 56.076 21.48 56.16 ;
    END
  END cfg_data[252]
  PIN cfg_data[253]
    DIRECTION INPUT ;
    USE SIGNAL ;
    PORT
      LAYER M5 ;
        RECT  21.552 56.076 21.576 56.16 ;
    END
  END cfg_data[253]
  PIN cfg_data[254]
    DIRECTION INPUT ;
    USE SIGNAL ;
    PORT
      LAYER M5 ;
        RECT  21.648 56.076 21.672 56.16 ;
    END
  END cfg_data[254]
  PIN cfg_data[255]
    DIRECTION INPUT ;
    USE SIGNAL ;
    PORT
      LAYER M5 ;
        RECT  21.744 56.076 21.768 56.16 ;
    END
  END cfg_data[255]
  PIN cfg_data[25]
    DIRECTION INPUT ;
    USE SIGNAL ;
    PORT
      LAYER M5 ;
        RECT  15.024 56.076 15.048 56.16 ;
    END
  END cfg_data[25]
  PIN cfg_data[26]
    DIRECTION INPUT ;
    USE SIGNAL ;
    PORT
      LAYER M5 ;
        RECT  15.12 56.076 15.144 56.16 ;
    END
  END cfg_data[26]
  PIN cfg_data[27]
    DIRECTION INPUT ;
    USE SIGNAL ;
    PORT
      LAYER M5 ;
        RECT  15.216 56.076 15.24 56.16 ;
    END
  END cfg_data[27]
  PIN cfg_data[28]
    DIRECTION INPUT ;
    USE SIGNAL ;
    PORT
      LAYER M5 ;
        RECT  15.312 56.076 15.336 56.16 ;
    END
  END cfg_data[28]
  PIN cfg_data[29]
    DIRECTION INPUT ;
    USE SIGNAL ;
    PORT
      LAYER M5 ;
        RECT  15.408 56.076 15.432 56.16 ;
    END
  END cfg_data[29]
  PIN cfg_data[2]
    DIRECTION INPUT ;
    USE SIGNAL ;
    PORT
      LAYER M5 ;
        RECT  18.96 56.076 18.984 56.16 ;
    END
  END cfg_data[2]
  PIN cfg_data[30]
    DIRECTION INPUT ;
    USE SIGNAL ;
    PORT
      LAYER M5 ;
        RECT  15.504 56.076 15.528 56.16 ;
    END
  END cfg_data[30]
  PIN cfg_data[31]
    DIRECTION INPUT ;
    USE SIGNAL ;
    PORT
      LAYER M5 ;
        RECT  15.6 56.076 15.624 56.16 ;
    END
  END cfg_data[31]
  PIN cfg_data[32]
    DIRECTION INPUT ;
    USE SIGNAL ;
    PORT
      LAYER M5 ;
        RECT  15.696 56.076 15.72 56.16 ;
    END
  END cfg_data[32]
  PIN cfg_data[33]
    DIRECTION INPUT ;
    USE SIGNAL ;
    PORT
      LAYER M5 ;
        RECT  15.792 56.076 15.816 56.16 ;
    END
  END cfg_data[33]
  PIN cfg_data[34]
    DIRECTION INPUT ;
    USE SIGNAL ;
    PORT
      LAYER M5 ;
        RECT  15.888 56.076 15.912 56.16 ;
    END
  END cfg_data[34]
  PIN cfg_data[35]
    DIRECTION INPUT ;
    USE SIGNAL ;
    PORT
      LAYER M5 ;
        RECT  15.984 56.076 16.008 56.16 ;
    END
  END cfg_data[35]
  PIN cfg_data[36]
    DIRECTION INPUT ;
    USE SIGNAL ;
    PORT
      LAYER M5 ;
        RECT  16.08 56.076 16.104 56.16 ;
    END
  END cfg_data[36]
  PIN cfg_data[37]
    DIRECTION INPUT ;
    USE SIGNAL ;
    PORT
      LAYER M5 ;
        RECT  16.176 56.076 16.2 56.16 ;
    END
  END cfg_data[37]
  PIN cfg_data[38]
    DIRECTION INPUT ;
    USE SIGNAL ;
    PORT
      LAYER M5 ;
        RECT  16.272 56.076 16.296 56.16 ;
    END
  END cfg_data[38]
  PIN cfg_data[39]
    DIRECTION INPUT ;
    USE SIGNAL ;
    PORT
      LAYER M5 ;
        RECT  16.368 56.076 16.392 56.16 ;
    END
  END cfg_data[39]
  PIN cfg_data[3]
    DIRECTION INPUT ;
    USE SIGNAL ;
    PORT
      LAYER M5 ;
        RECT  19.056 56.076 19.08 56.16 ;
    END
  END cfg_data[3]
  PIN cfg_data[40]
    DIRECTION INPUT ;
    USE SIGNAL ;
    PORT
      LAYER M5 ;
        RECT  16.464 56.076 16.488 56.16 ;
    END
  END cfg_data[40]
  PIN cfg_data[41]
    DIRECTION INPUT ;
    USE SIGNAL ;
    PORT
      LAYER M5 ;
        RECT  16.56 56.076 16.584 56.16 ;
    END
  END cfg_data[41]
  PIN cfg_data[42]
    DIRECTION INPUT ;
    USE SIGNAL ;
    PORT
      LAYER M5 ;
        RECT  16.656 56.076 16.68 56.16 ;
    END
  END cfg_data[42]
  PIN cfg_data[43]
    DIRECTION INPUT ;
    USE SIGNAL ;
    PORT
      LAYER M5 ;
        RECT  16.752 56.076 16.776 56.16 ;
    END
  END cfg_data[43]
  PIN cfg_data[44]
    DIRECTION INPUT ;
    USE SIGNAL ;
    PORT
      LAYER M5 ;
        RECT  16.848 56.076 16.872 56.16 ;
    END
  END cfg_data[44]
  PIN cfg_data[45]
    DIRECTION INPUT ;
    USE SIGNAL ;
    PORT
      LAYER M5 ;
        RECT  16.944 56.076 16.968 56.16 ;
    END
  END cfg_data[45]
  PIN cfg_data[46]
    DIRECTION INPUT ;
    USE SIGNAL ;
    PORT
      LAYER M5 ;
        RECT  17.04 56.076 17.064 56.16 ;
    END
  END cfg_data[46]
  PIN cfg_data[47]
    DIRECTION INPUT ;
    USE SIGNAL ;
    PORT
      LAYER M5 ;
        RECT  17.136 56.076 17.16 56.16 ;
    END
  END cfg_data[47]
  PIN cfg_data[48]
    DIRECTION INPUT ;
    USE SIGNAL ;
    PORT
      LAYER M5 ;
        RECT  17.232 56.076 17.256 56.16 ;
    END
  END cfg_data[48]
  PIN cfg_data[49]
    DIRECTION INPUT ;
    USE SIGNAL ;
    PORT
      LAYER M5 ;
        RECT  17.328 56.076 17.352 56.16 ;
    END
  END cfg_data[49]
  PIN cfg_data[4]
    DIRECTION INPUT ;
    USE SIGNAL ;
    PORT
      LAYER M5 ;
        RECT  19.152 56.076 19.176 56.16 ;
    END
  END cfg_data[4]
  PIN cfg_data[50]
    DIRECTION INPUT ;
    USE SIGNAL ;
    PORT
      LAYER M5 ;
        RECT  17.424 56.076 17.448 56.16 ;
    END
  END cfg_data[50]
  PIN cfg_data[51]
    DIRECTION INPUT ;
    USE SIGNAL ;
    PORT
      LAYER M5 ;
        RECT  17.52 56.076 17.544 56.16 ;
    END
  END cfg_data[51]
  PIN cfg_data[52]
    DIRECTION INPUT ;
    USE SIGNAL ;
    PORT
      LAYER M5 ;
        RECT  66 56.076 66.024 56.16 ;
    END
  END cfg_data[52]
  PIN cfg_data[53]
    DIRECTION INPUT ;
    USE SIGNAL ;
    PORT
      LAYER M5 ;
        RECT  66.096 56.076 66.12 56.16 ;
    END
  END cfg_data[53]
  PIN cfg_data[54]
    DIRECTION INPUT ;
    USE SIGNAL ;
    PORT
      LAYER M5 ;
        RECT  66.192 56.076 66.216 56.16 ;
    END
  END cfg_data[54]
  PIN cfg_data[55]
    DIRECTION INPUT ;
    USE SIGNAL ;
    PORT
      LAYER M5 ;
        RECT  66.288 56.076 66.312 56.16 ;
    END
  END cfg_data[55]
  PIN cfg_data[56]
    DIRECTION INPUT ;
    USE SIGNAL ;
    PORT
      LAYER M5 ;
        RECT  66.384 56.076 66.408 56.16 ;
    END
  END cfg_data[56]
  PIN cfg_data[57]
    DIRECTION INPUT ;
    USE SIGNAL ;
    PORT
      LAYER M5 ;
        RECT  66.48 56.076 66.504 56.16 ;
    END
  END cfg_data[57]
  PIN cfg_data[58]
    DIRECTION INPUT ;
    USE SIGNAL ;
    PORT
      LAYER M5 ;
        RECT  66.576 56.076 66.6 56.16 ;
    END
  END cfg_data[58]
  PIN cfg_data[59]
    DIRECTION INPUT ;
    USE SIGNAL ;
    PORT
      LAYER M5 ;
        RECT  66.672 56.076 66.696 56.16 ;
    END
  END cfg_data[59]
  PIN cfg_data[5]
    DIRECTION INPUT ;
    USE SIGNAL ;
    PORT
      LAYER M5 ;
        RECT  19.248 56.076 19.272 56.16 ;
    END
  END cfg_data[5]
  PIN cfg_data[60]
    DIRECTION INPUT ;
    USE SIGNAL ;
    PORT
      LAYER M5 ;
        RECT  66.768 56.076 66.792 56.16 ;
    END
  END cfg_data[60]
  PIN cfg_data[61]
    DIRECTION INPUT ;
    USE SIGNAL ;
    PORT
      LAYER M5 ;
        RECT  66.864 56.076 66.888 56.16 ;
    END
  END cfg_data[61]
  PIN cfg_data[62]
    DIRECTION INPUT ;
    USE SIGNAL ;
    PORT
      LAYER M5 ;
        RECT  66.96 56.076 66.984 56.16 ;
    END
  END cfg_data[62]
  PIN cfg_data[63]
    DIRECTION INPUT ;
    USE SIGNAL ;
    PORT
      LAYER M5 ;
        RECT  67.056 56.076 67.08 56.16 ;
    END
  END cfg_data[63]
  PIN cfg_data[64]
    DIRECTION INPUT ;
    USE SIGNAL ;
    PORT
      LAYER M5 ;
        RECT  67.152 56.076 67.176 56.16 ;
    END
  END cfg_data[64]
  PIN cfg_data[65]
    DIRECTION INPUT ;
    USE SIGNAL ;
    PORT
      LAYER M5 ;
        RECT  67.248 56.076 67.272 56.16 ;
    END
  END cfg_data[65]
  PIN cfg_data[66]
    DIRECTION INPUT ;
    USE SIGNAL ;
    PORT
      LAYER M5 ;
        RECT  67.344 56.076 67.368 56.16 ;
    END
  END cfg_data[66]
  PIN cfg_data[67]
    DIRECTION INPUT ;
    USE SIGNAL ;
    PORT
      LAYER M5 ;
        RECT  67.44 56.076 67.464 56.16 ;
    END
  END cfg_data[67]
  PIN cfg_data[68]
    DIRECTION INPUT ;
    USE SIGNAL ;
    PORT
      LAYER M5 ;
        RECT  67.536 56.076 67.56 56.16 ;
    END
  END cfg_data[68]
  PIN cfg_data[69]
    DIRECTION INPUT ;
    USE SIGNAL ;
    PORT
      LAYER M5 ;
        RECT  67.632 56.076 67.656 56.16 ;
    END
  END cfg_data[69]
  PIN cfg_data[6]
    DIRECTION INPUT ;
    USE SIGNAL ;
    PORT
      LAYER M5 ;
        RECT  19.344 56.076 19.368 56.16 ;
    END
  END cfg_data[6]
  PIN cfg_data[70]
    DIRECTION INPUT ;
    USE SIGNAL ;
    PORT
      LAYER M5 ;
        RECT  67.728 56.076 67.752 56.16 ;
    END
  END cfg_data[70]
  PIN cfg_data[71]
    DIRECTION INPUT ;
    USE SIGNAL ;
    PORT
      LAYER M5 ;
        RECT  67.824 56.076 67.848 56.16 ;
    END
  END cfg_data[71]
  PIN cfg_data[72]
    DIRECTION INPUT ;
    USE SIGNAL ;
    PORT
      LAYER M5 ;
        RECT  67.92 56.076 67.944 56.16 ;
    END
  END cfg_data[72]
  PIN cfg_data[73]
    DIRECTION INPUT ;
    USE SIGNAL ;
    PORT
      LAYER M5 ;
        RECT  68.016 56.076 68.04 56.16 ;
    END
  END cfg_data[73]
  PIN cfg_data[74]
    DIRECTION INPUT ;
    USE SIGNAL ;
    PORT
      LAYER M5 ;
        RECT  68.112 56.076 68.136 56.16 ;
    END
  END cfg_data[74]
  PIN cfg_data[75]
    DIRECTION INPUT ;
    USE SIGNAL ;
    PORT
      LAYER M5 ;
        RECT  68.208 56.076 68.232 56.16 ;
    END
  END cfg_data[75]
  PIN cfg_data[76]
    DIRECTION INPUT ;
    USE SIGNAL ;
    PORT
      LAYER M5 ;
        RECT  68.304 56.076 68.328 56.16 ;
    END
  END cfg_data[76]
  PIN cfg_data[77]
    DIRECTION INPUT ;
    USE SIGNAL ;
    PORT
      LAYER M5 ;
        RECT  68.4 56.076 68.424 56.16 ;
    END
  END cfg_data[77]
  PIN cfg_data[78]
    DIRECTION INPUT ;
    USE SIGNAL ;
    PORT
      LAYER M5 ;
        RECT  68.496 56.076 68.52 56.16 ;
    END
  END cfg_data[78]
  PIN cfg_data[79]
    DIRECTION INPUT ;
    USE SIGNAL ;
    PORT
      LAYER M5 ;
        RECT  68.592 56.076 68.616 56.16 ;
    END
  END cfg_data[79]
  PIN cfg_data[7]
    DIRECTION INPUT ;
    USE SIGNAL ;
    PORT
      LAYER M5 ;
        RECT  19.44 56.076 19.464 56.16 ;
    END
  END cfg_data[7]
  PIN cfg_data[80]
    DIRECTION INPUT ;
    USE SIGNAL ;
    PORT
      LAYER M5 ;
        RECT  68.688 56.076 68.712 56.16 ;
    END
  END cfg_data[80]
  PIN cfg_data[81]
    DIRECTION INPUT ;
    USE SIGNAL ;
    PORT
      LAYER M5 ;
        RECT  68.784 56.076 68.808 56.16 ;
    END
  END cfg_data[81]
  PIN cfg_data[82]
    DIRECTION INPUT ;
    USE SIGNAL ;
    PORT
      LAYER M5 ;
        RECT  68.88 56.076 68.904 56.16 ;
    END
  END cfg_data[82]
  PIN cfg_data[83]
    DIRECTION INPUT ;
    USE SIGNAL ;
    PORT
      LAYER M5 ;
        RECT  68.976 56.076 69 56.16 ;
    END
  END cfg_data[83]
  PIN cfg_data[84]
    DIRECTION INPUT ;
    USE SIGNAL ;
    PORT
      LAYER M5 ;
        RECT  72.144 56.076 72.168 56.16 ;
    END
  END cfg_data[84]
  PIN cfg_data[85]
    DIRECTION INPUT ;
    USE SIGNAL ;
    PORT
      LAYER M5 ;
        RECT  72.24 56.076 72.264 56.16 ;
    END
  END cfg_data[85]
  PIN cfg_data[86]
    DIRECTION INPUT ;
    USE SIGNAL ;
    PORT
      LAYER M5 ;
        RECT  72.336 56.076 72.36 56.16 ;
    END
  END cfg_data[86]
  PIN cfg_data[87]
    DIRECTION INPUT ;
    USE SIGNAL ;
    PORT
      LAYER M5 ;
        RECT  72.432 56.076 72.456 56.16 ;
    END
  END cfg_data[87]
  PIN cfg_data[88]
    DIRECTION INPUT ;
    USE SIGNAL ;
    PORT
      LAYER M5 ;
        RECT  72.528 56.076 72.552 56.16 ;
    END
  END cfg_data[88]
  PIN cfg_data[89]
    DIRECTION INPUT ;
    USE SIGNAL ;
    PORT
      LAYER M5 ;
        RECT  72.624 56.076 72.648 56.16 ;
    END
  END cfg_data[89]
  PIN cfg_data[8]
    DIRECTION INPUT ;
    USE SIGNAL ;
    PORT
      LAYER M5 ;
        RECT  19.536 56.076 19.56 56.16 ;
    END
  END cfg_data[8]
  PIN cfg_data[90]
    DIRECTION INPUT ;
    USE SIGNAL ;
    PORT
      LAYER M5 ;
        RECT  72.72 56.076 72.744 56.16 ;
    END
  END cfg_data[90]
  PIN cfg_data[91]
    DIRECTION INPUT ;
    USE SIGNAL ;
    PORT
      LAYER M5 ;
        RECT  72.816 56.076 72.84 56.16 ;
    END
  END cfg_data[91]
  PIN cfg_data[92]
    DIRECTION INPUT ;
    USE SIGNAL ;
    PORT
      LAYER M5 ;
        RECT  72.912 56.076 72.936 56.16 ;
    END
  END cfg_data[92]
  PIN cfg_data[93]
    DIRECTION INPUT ;
    USE SIGNAL ;
    PORT
      LAYER M5 ;
        RECT  73.008 56.076 73.032 56.16 ;
    END
  END cfg_data[93]
  PIN cfg_data[94]
    DIRECTION INPUT ;
    USE SIGNAL ;
    PORT
      LAYER M5 ;
        RECT  73.104 56.076 73.128 56.16 ;
    END
  END cfg_data[94]
  PIN cfg_data[95]
    DIRECTION INPUT ;
    USE SIGNAL ;
    PORT
      LAYER M5 ;
        RECT  73.2 56.076 73.224 56.16 ;
    END
  END cfg_data[95]
  PIN cfg_data[96]
    DIRECTION INPUT ;
    USE SIGNAL ;
    PORT
      LAYER M5 ;
        RECT  73.296 56.076 73.32 56.16 ;
    END
  END cfg_data[96]
  PIN cfg_data[97]
    DIRECTION INPUT ;
    USE SIGNAL ;
    PORT
      LAYER M5 ;
        RECT  73.392 56.076 73.416 56.16 ;
    END
  END cfg_data[97]
  PIN cfg_data[98]
    DIRECTION INPUT ;
    USE SIGNAL ;
    PORT
      LAYER M5 ;
        RECT  73.488 56.076 73.512 56.16 ;
    END
  END cfg_data[98]
  PIN cfg_data[99]
    DIRECTION INPUT ;
    USE SIGNAL ;
    PORT
      LAYER M5 ;
        RECT  73.584 56.076 73.608 56.16 ;
    END
  END cfg_data[99]
  PIN cfg_data[9]
    DIRECTION INPUT ;
    USE SIGNAL ;
    PORT
      LAYER M5 ;
        RECT  19.632 56.076 19.656 56.16 ;
    END
  END cfg_data[9]
  PIN cfg_target[0]
    DIRECTION INPUT ;
    USE SIGNAL ;
    PORT
      LAYER M5 ;
        RECT  21.84 56.076 21.864 56.16 ;
    END
  END cfg_target[0]
  PIN cfg_target[1]
    DIRECTION INPUT ;
    USE SIGNAL ;
    PORT
      LAYER M5 ;
        RECT  21.936 56.076 21.96 56.16 ;
    END
  END cfg_target[1]
  PIN cfg_target[2]
    DIRECTION INPUT ;
    USE SIGNAL ;
    PORT
      LAYER M5 ;
        RECT  22.032 56.076 22.056 56.16 ;
    END
  END cfg_target[2]
  PIN cfg_target[3]
    DIRECTION INPUT ;
    USE SIGNAL ;
    PORT
      LAYER M5 ;
        RECT  22.128 56.076 22.152 56.16 ;
    END
  END cfg_target[3]
  PIN cfg_target[4]
    DIRECTION INPUT ;
    USE SIGNAL ;
    PORT
      LAYER M5 ;
        RECT  22.224 56.076 22.248 56.16 ;
    END
  END cfg_target[4]
  PIN cfg_target[5]
    DIRECTION INPUT ;
    USE SIGNAL ;
    PORT
      LAYER M5 ;
        RECT  22.32 56.076 22.344 56.16 ;
    END
  END cfg_target[5]
  PIN cfg_target[6]
    DIRECTION INPUT ;
    USE SIGNAL ;
    PORT
      LAYER M5 ;
        RECT  22.416 56.076 22.44 56.16 ;
    END
  END cfg_target[6]
  PIN cfg_target[7]
    DIRECTION INPUT ;
    USE SIGNAL ;
    PORT
      LAYER M5 ;
        RECT  22.512 56.076 22.536 56.16 ;
    END
  END cfg_target[7]
  PIN cfg_v
    DIRECTION INPUT ;
    USE SIGNAL ;
    PORT
      LAYER M5 ;
        RECT  22.608 56.076 22.632 56.16 ;
    END
  END cfg_v
  PIN clk
    DIRECTION INPUT ;
    USE SIGNAL ;
    PORT
      LAYER M5 ;
        RECT  22.704 56.076 22.728 56.16 ;
    END
  END clk
  PIN configured
    DIRECTION OUTPUT ;
    USE SIGNAL ;
    PORT
      LAYER M5 ;
        RECT  22.8 56.076 22.824 56.16 ;
    END
  END configured
  PIN desc_base[0]
    DIRECTION INPUT ;
    USE SIGNAL ;
    PORT
      LAYER M5 ;
        RECT  22.896 56.076 22.92 56.16 ;
    END
  END desc_base[0]
  PIN desc_base[10]
    DIRECTION INPUT ;
    USE SIGNAL ;
    PORT
      LAYER M5 ;
        RECT  5.424 56.076 5.448 56.16 ;
    END
  END desc_base[10]
  PIN desc_base[11]
    DIRECTION INPUT ;
    USE SIGNAL ;
    PORT
      LAYER M5 ;
        RECT  5.52 56.076 5.544 56.16 ;
    END
  END desc_base[11]
  PIN desc_base[1]
    DIRECTION INPUT ;
    USE SIGNAL ;
    PORT
      LAYER M5 ;
        RECT  22.992 56.076 23.016 56.16 ;
    END
  END desc_base[1]
  PIN desc_base[2]
    DIRECTION INPUT ;
    USE SIGNAL ;
    PORT
      LAYER M5 ;
        RECT  23.088 56.076 23.112 56.16 ;
    END
  END desc_base[2]
  PIN desc_base[3]
    DIRECTION INPUT ;
    USE SIGNAL ;
    PORT
      LAYER M5 ;
        RECT  23.184 56.076 23.208 56.16 ;
    END
  END desc_base[3]
  PIN desc_base[4]
    DIRECTION INPUT ;
    USE SIGNAL ;
    PORT
      LAYER M5 ;
        RECT  23.28 56.076 23.304 56.16 ;
    END
  END desc_base[4]
  PIN desc_base[5]
    DIRECTION INPUT ;
    USE SIGNAL ;
    PORT
      LAYER M5 ;
        RECT  23.376 56.076 23.4 56.16 ;
    END
  END desc_base[5]
  PIN desc_base[6]
    DIRECTION INPUT ;
    USE SIGNAL ;
    PORT
      LAYER M5 ;
        RECT  23.472 56.076 23.496 56.16 ;
    END
  END desc_base[6]
  PIN desc_base[7]
    DIRECTION INPUT ;
    USE SIGNAL ;
    PORT
      LAYER M5 ;
        RECT  23.568 56.076 23.592 56.16 ;
    END
  END desc_base[7]
  PIN desc_base[8]
    DIRECTION INPUT ;
    USE SIGNAL ;
    PORT
      LAYER M5 ;
        RECT  23.664 56.076 23.688 56.16 ;
    END
  END desc_base[8]
  PIN desc_base[9]
    DIRECTION INPUT ;
    USE SIGNAL ;
    PORT
      LAYER M5 ;
        RECT  5.328 56.076 5.352 56.16 ;
    END
  END desc_base[9]
  PIN desc_limit[0]
    DIRECTION INPUT ;
    USE SIGNAL ;
    PORT
      LAYER M5 ;
        RECT  5.616 56.076 5.64 56.16 ;
    END
  END desc_limit[0]
  PIN desc_limit[10]
    DIRECTION INPUT ;
    USE SIGNAL ;
    PORT
      LAYER M5 ;
        RECT  6.576 56.076 6.6 56.16 ;
    END
  END desc_limit[10]
  PIN desc_limit[11]
    DIRECTION INPUT ;
    USE SIGNAL ;
    PORT
      LAYER M5 ;
        RECT  6.672 56.076 6.696 56.16 ;
    END
  END desc_limit[11]
  PIN desc_limit[12]
    DIRECTION INPUT ;
    USE SIGNAL ;
    PORT
      LAYER M5 ;
        RECT  6.768 56.076 6.792 56.16 ;
    END
  END desc_limit[12]
  PIN desc_limit[1]
    DIRECTION INPUT ;
    USE SIGNAL ;
    PORT
      LAYER M5 ;
        RECT  5.712 56.076 5.736 56.16 ;
    END
  END desc_limit[1]
  PIN desc_limit[2]
    DIRECTION INPUT ;
    USE SIGNAL ;
    PORT
      LAYER M5 ;
        RECT  5.808 56.076 5.832 56.16 ;
    END
  END desc_limit[2]
  PIN desc_limit[3]
    DIRECTION INPUT ;
    USE SIGNAL ;
    PORT
      LAYER M5 ;
        RECT  5.904 56.076 5.928 56.16 ;
    END
  END desc_limit[3]
  PIN desc_limit[4]
    DIRECTION INPUT ;
    USE SIGNAL ;
    PORT
      LAYER M5 ;
        RECT  6 56.076 6.024 56.16 ;
    END
  END desc_limit[4]
  PIN desc_limit[5]
    DIRECTION INPUT ;
    USE SIGNAL ;
    PORT
      LAYER M5 ;
        RECT  6.096 56.076 6.12 56.16 ;
    END
  END desc_limit[5]
  PIN desc_limit[6]
    DIRECTION INPUT ;
    USE SIGNAL ;
    PORT
      LAYER M5 ;
        RECT  6.192 56.076 6.216 56.16 ;
    END
  END desc_limit[6]
  PIN desc_limit[7]
    DIRECTION INPUT ;
    USE SIGNAL ;
    PORT
      LAYER M5 ;
        RECT  6.288 56.076 6.312 56.16 ;
    END
  END desc_limit[7]
  PIN desc_limit[8]
    DIRECTION INPUT ;
    USE SIGNAL ;
    PORT
      LAYER M5 ;
        RECT  6.384 56.076 6.408 56.16 ;
    END
  END desc_limit[8]
  PIN desc_limit[9]
    DIRECTION INPUT ;
    USE SIGNAL ;
    PORT
      LAYER M5 ;
        RECT  6.48 56.076 6.504 56.16 ;
    END
  END desc_limit[9]
  PIN desc_loops[0]
    DIRECTION INPUT ;
    USE SIGNAL ;
    PORT
      LAYER M5 ;
        RECT  6.864 56.076 6.888 56.16 ;
    END
  END desc_loops[0]
  PIN desc_loops[10]
    DIRECTION INPUT ;
    USE SIGNAL ;
    PORT
      LAYER M5 ;
        RECT  7.824 56.076 7.848 56.16 ;
    END
  END desc_loops[10]
  PIN desc_loops[11]
    DIRECTION INPUT ;
    USE SIGNAL ;
    PORT
      LAYER M5 ;
        RECT  7.92 56.076 7.944 56.16 ;
    END
  END desc_loops[11]
  PIN desc_loops[12]
    DIRECTION INPUT ;
    USE SIGNAL ;
    PORT
      LAYER M5 ;
        RECT  8.016 56.076 8.04 56.16 ;
    END
  END desc_loops[12]
  PIN desc_loops[13]
    DIRECTION INPUT ;
    USE SIGNAL ;
    PORT
      LAYER M5 ;
        RECT  8.112 56.076 8.136 56.16 ;
    END
  END desc_loops[13]
  PIN desc_loops[14]
    DIRECTION INPUT ;
    USE SIGNAL ;
    PORT
      LAYER M5 ;
        RECT  8.208 56.076 8.232 56.16 ;
    END
  END desc_loops[14]
  PIN desc_loops[15]
    DIRECTION INPUT ;
    USE SIGNAL ;
    PORT
      LAYER M5 ;
        RECT  8.304 56.076 8.328 56.16 ;
    END
  END desc_loops[15]
  PIN desc_loops[1]
    DIRECTION INPUT ;
    USE SIGNAL ;
    PORT
      LAYER M5 ;
        RECT  6.96 56.076 6.984 56.16 ;
    END
  END desc_loops[1]
  PIN desc_loops[2]
    DIRECTION INPUT ;
    USE SIGNAL ;
    PORT
      LAYER M5 ;
        RECT  7.056 56.076 7.08 56.16 ;
    END
  END desc_loops[2]
  PIN desc_loops[3]
    DIRECTION INPUT ;
    USE SIGNAL ;
    PORT
      LAYER M5 ;
        RECT  7.152 56.076 7.176 56.16 ;
    END
  END desc_loops[3]
  PIN desc_loops[4]
    DIRECTION INPUT ;
    USE SIGNAL ;
    PORT
      LAYER M5 ;
        RECT  7.248 56.076 7.272 56.16 ;
    END
  END desc_loops[4]
  PIN desc_loops[5]
    DIRECTION INPUT ;
    USE SIGNAL ;
    PORT
      LAYER M5 ;
        RECT  7.344 56.076 7.368 56.16 ;
    END
  END desc_loops[5]
  PIN desc_loops[6]
    DIRECTION INPUT ;
    USE SIGNAL ;
    PORT
      LAYER M5 ;
        RECT  7.44 56.076 7.464 56.16 ;
    END
  END desc_loops[6]
  PIN desc_loops[7]
    DIRECTION INPUT ;
    USE SIGNAL ;
    PORT
      LAYER M5 ;
        RECT  7.536 56.076 7.56 56.16 ;
    END
  END desc_loops[7]
  PIN desc_loops[8]
    DIRECTION INPUT ;
    USE SIGNAL ;
    PORT
      LAYER M5 ;
        RECT  7.632 56.076 7.656 56.16 ;
    END
  END desc_loops[8]
  PIN desc_loops[9]
    DIRECTION INPUT ;
    USE SIGNAL ;
    PORT
      LAYER M5 ;
        RECT  7.728 56.076 7.752 56.16 ;
    END
  END desc_loops[9]
  PIN desc_v
    DIRECTION INPUT ;
    USE SIGNAL ;
    PORT
      LAYER M5 ;
        RECT  9.168 56.076 9.192 56.16 ;
    END
  END desc_v
  PIN fault
    DIRECTION OUTPUT ;
    USE SIGNAL ;
    PORT
      LAYER M5 ;
        RECT  9.264 56.076 9.288 56.16 ;
    END
  END fault
  PIN fault_cause[0]
    DIRECTION OUTPUT ;
    USE SIGNAL ;
    PORT
      LAYER M5 ;
        RECT  9.36 56.076 9.384 56.16 ;
    END
  END fault_cause[0]
  PIN fault_cause[10]
    DIRECTION OUTPUT ;
    USE SIGNAL ;
    PORT
      LAYER M5 ;
        RECT  10.32 56.076 10.344 56.16 ;
    END
  END fault_cause[10]
  PIN fault_cause[11]
    DIRECTION OUTPUT ;
    USE SIGNAL ;
    PORT
      LAYER M5 ;
        RECT  10.416 56.076 10.44 56.16 ;
    END
  END fault_cause[11]
  PIN fault_cause[12]
    DIRECTION OUTPUT ;
    USE SIGNAL ;
    PORT
      LAYER M5 ;
        RECT  10.512 56.076 10.536 56.16 ;
    END
  END fault_cause[12]
  PIN fault_cause[13]
    DIRECTION OUTPUT ;
    USE SIGNAL ;
    PORT
      LAYER M5 ;
        RECT  10.608 56.076 10.632 56.16 ;
    END
  END fault_cause[13]
  PIN fault_cause[14]
    DIRECTION OUTPUT ;
    USE SIGNAL ;
    PORT
      LAYER M5 ;
        RECT  10.704 56.076 10.728 56.16 ;
    END
  END fault_cause[14]
  PIN fault_cause[15]
    DIRECTION OUTPUT ;
    USE SIGNAL ;
    PORT
      LAYER M5 ;
        RECT  10.8 56.076 10.824 56.16 ;
    END
  END fault_cause[15]
  PIN fault_cause[1]
    DIRECTION OUTPUT ;
    USE SIGNAL ;
    PORT
      LAYER M5 ;
        RECT  9.456 56.076 9.48 56.16 ;
    END
  END fault_cause[1]
  PIN fault_cause[2]
    DIRECTION OUTPUT ;
    USE SIGNAL ;
    PORT
      LAYER M5 ;
        RECT  9.552 56.076 9.576 56.16 ;
    END
  END fault_cause[2]
  PIN fault_cause[3]
    DIRECTION OUTPUT ;
    USE SIGNAL ;
    PORT
      LAYER M5 ;
        RECT  9.648 56.076 9.672 56.16 ;
    END
  END fault_cause[3]
  PIN fault_cause[4]
    DIRECTION OUTPUT ;
    USE SIGNAL ;
    PORT
      LAYER M5 ;
        RECT  9.744 56.076 9.768 56.16 ;
    END
  END fault_cause[4]
  PIN fault_cause[5]
    DIRECTION OUTPUT ;
    USE SIGNAL ;
    PORT
      LAYER M5 ;
        RECT  9.84 56.076 9.864 56.16 ;
    END
  END fault_cause[5]
  PIN fault_cause[6]
    DIRECTION OUTPUT ;
    USE SIGNAL ;
    PORT
      LAYER M5 ;
        RECT  9.936 56.076 9.96 56.16 ;
    END
  END fault_cause[6]
  PIN fault_cause[7]
    DIRECTION OUTPUT ;
    USE SIGNAL ;
    PORT
      LAYER M5 ;
        RECT  10.032 56.076 10.056 56.16 ;
    END
  END fault_cause[7]
  PIN fault_cause[8]
    DIRECTION OUTPUT ;
    USE SIGNAL ;
    PORT
      LAYER M5 ;
        RECT  10.128 56.076 10.152 56.16 ;
    END
  END fault_cause[8]
  PIN fault_cause[9]
    DIRECTION OUTPUT ;
    USE SIGNAL ;
    PORT
      LAYER M5 ;
        RECT  10.224 56.076 10.248 56.16 ;
    END
  END fault_cause[9]
  PIN init_busy
    DIRECTION OUTPUT ;
    USE SIGNAL ;
    PORT
      LAYER M5 ;
        RECT  10.896 56.076 10.92 56.16 ;
    END
  END init_busy
  PIN issuer_busy
    DIRECTION INPUT ;
    USE SIGNAL ;
    PORT
      LAYER M5 ;
        RECT  58.32 0 58.344 0.084 ;
    END
  END issuer_busy
  PIN issuer_cfg[0]
    DIRECTION OUTPUT ;
    USE SIGNAL ;
    PORT
      LAYER M5 ;
        RECT  58.416 0 58.44 0.084 ;
    END
  END issuer_cfg[0]
  PIN issuer_cfg[10]
    DIRECTION OUTPUT ;
    USE SIGNAL ;
    PORT
      LAYER M5 ;
        RECT  59.376 0 59.4 0.084 ;
    END
  END issuer_cfg[10]
  PIN issuer_cfg[11]
    DIRECTION OUTPUT ;
    USE SIGNAL ;
    PORT
      LAYER M5 ;
        RECT  59.472 0 59.496 0.084 ;
    END
  END issuer_cfg[11]
  PIN issuer_cfg[12]
    DIRECTION OUTPUT ;
    USE SIGNAL ;
    PORT
      LAYER M5 ;
        RECT  59.568 0 59.592 0.084 ;
    END
  END issuer_cfg[12]
  PIN issuer_cfg[13]
    DIRECTION OUTPUT ;
    USE SIGNAL ;
    PORT
      LAYER M5 ;
        RECT  59.664 0 59.688 0.084 ;
    END
  END issuer_cfg[13]
  PIN issuer_cfg[14]
    DIRECTION OUTPUT ;
    USE SIGNAL ;
    PORT
      LAYER M5 ;
        RECT  59.76 0 59.784 0.084 ;
    END
  END issuer_cfg[14]
  PIN issuer_cfg[15]
    DIRECTION OUTPUT ;
    USE SIGNAL ;
    PORT
      LAYER M5 ;
        RECT  59.856 0 59.88 0.084 ;
    END
  END issuer_cfg[15]
  PIN issuer_cfg[16]
    DIRECTION OUTPUT ;
    USE SIGNAL ;
    PORT
      LAYER M5 ;
        RECT  59.952 0 59.976 0.084 ;
    END
  END issuer_cfg[16]
  PIN issuer_cfg[17]
    DIRECTION OUTPUT ;
    USE SIGNAL ;
    PORT
      LAYER M5 ;
        RECT  60.048 0 60.072 0.084 ;
    END
  END issuer_cfg[17]
  PIN issuer_cfg[18]
    DIRECTION OUTPUT ;
    USE SIGNAL ;
    PORT
      LAYER M5 ;
        RECT  60.144 0 60.168 0.084 ;
    END
  END issuer_cfg[18]
  PIN issuer_cfg[19]
    DIRECTION OUTPUT ;
    USE SIGNAL ;
    PORT
      LAYER M5 ;
        RECT  60.24 0 60.264 0.084 ;
    END
  END issuer_cfg[19]
  PIN issuer_cfg[1]
    DIRECTION OUTPUT ;
    USE SIGNAL ;
    PORT
      LAYER M5 ;
        RECT  58.512 0 58.536 0.084 ;
    END
  END issuer_cfg[1]
  PIN issuer_cfg[20]
    DIRECTION OUTPUT ;
    USE SIGNAL ;
    PORT
      LAYER M5 ;
        RECT  60.336 0 60.36 0.084 ;
    END
  END issuer_cfg[20]
  PIN issuer_cfg[21]
    DIRECTION OUTPUT ;
    USE SIGNAL ;
    PORT
      LAYER M5 ;
        RECT  60.432 0 60.456 0.084 ;
    END
  END issuer_cfg[21]
  PIN issuer_cfg[22]
    DIRECTION OUTPUT ;
    USE SIGNAL ;
    PORT
      LAYER M5 ;
        RECT  60.528 0 60.552 0.084 ;
    END
  END issuer_cfg[22]
  PIN issuer_cfg[23]
    DIRECTION OUTPUT ;
    USE SIGNAL ;
    PORT
      LAYER M5 ;
        RECT  60.624 0 60.648 0.084 ;
    END
  END issuer_cfg[23]
  PIN issuer_cfg[24]
    DIRECTION OUTPUT ;
    USE SIGNAL ;
    PORT
      LAYER M5 ;
        RECT  60.72 0 60.744 0.084 ;
    END
  END issuer_cfg[24]
  PIN issuer_cfg[25]
    DIRECTION OUTPUT ;
    USE SIGNAL ;
    PORT
      LAYER M5 ;
        RECT  60.816 0 60.84 0.084 ;
    END
  END issuer_cfg[25]
  PIN issuer_cfg[26]
    DIRECTION OUTPUT ;
    USE SIGNAL ;
    PORT
      LAYER M5 ;
        RECT  60.912 0 60.936 0.084 ;
    END
  END issuer_cfg[26]
  PIN issuer_cfg[27]
    DIRECTION OUTPUT ;
    USE SIGNAL ;
    PORT
      LAYER M5 ;
        RECT  61.008 0 61.032 0.084 ;
    END
  END issuer_cfg[27]
  PIN issuer_cfg[28]
    DIRECTION OUTPUT ;
    USE SIGNAL ;
    PORT
      LAYER M5 ;
        RECT  61.104 0 61.128 0.084 ;
    END
  END issuer_cfg[28]
  PIN issuer_cfg[29]
    DIRECTION OUTPUT ;
    USE SIGNAL ;
    PORT
      LAYER M5 ;
        RECT  61.2 0 61.224 0.084 ;
    END
  END issuer_cfg[29]
  PIN issuer_cfg[2]
    DIRECTION OUTPUT ;
    USE SIGNAL ;
    PORT
      LAYER M5 ;
        RECT  58.608 0 58.632 0.084 ;
    END
  END issuer_cfg[2]
  PIN issuer_cfg[30]
    DIRECTION OUTPUT ;
    USE SIGNAL ;
    PORT
      LAYER M5 ;
        RECT  61.296 0 61.32 0.084 ;
    END
  END issuer_cfg[30]
  PIN issuer_cfg[31]
    DIRECTION OUTPUT ;
    USE SIGNAL ;
    PORT
      LAYER M5 ;
        RECT  13.392 0 13.416 0.084 ;
    END
  END issuer_cfg[31]
  PIN issuer_cfg[32]
    DIRECTION OUTPUT ;
    USE SIGNAL ;
    PORT
      LAYER M5 ;
        RECT  13.488 0 13.512 0.084 ;
    END
  END issuer_cfg[32]
  PIN issuer_cfg[33]
    DIRECTION OUTPUT ;
    USE SIGNAL ;
    PORT
      LAYER M5 ;
        RECT  13.584 0 13.608 0.084 ;
    END
  END issuer_cfg[33]
  PIN issuer_cfg[34]
    DIRECTION OUTPUT ;
    USE SIGNAL ;
    PORT
      LAYER M5 ;
        RECT  13.68 0 13.704 0.084 ;
    END
  END issuer_cfg[34]
  PIN issuer_cfg[35]
    DIRECTION OUTPUT ;
    USE SIGNAL ;
    PORT
      LAYER M5 ;
        RECT  13.776 0 13.8 0.084 ;
    END
  END issuer_cfg[35]
  PIN issuer_cfg[36]
    DIRECTION OUTPUT ;
    USE SIGNAL ;
    PORT
      LAYER M5 ;
        RECT  13.872 0 13.896 0.084 ;
    END
  END issuer_cfg[36]
  PIN issuer_cfg[3]
    DIRECTION OUTPUT ;
    USE SIGNAL ;
    PORT
      LAYER M5 ;
        RECT  58.704 0 58.728 0.084 ;
    END
  END issuer_cfg[3]
  PIN issuer_cfg[4]
    DIRECTION OUTPUT ;
    USE SIGNAL ;
    PORT
      LAYER M5 ;
        RECT  58.8 0 58.824 0.084 ;
    END
  END issuer_cfg[4]
  PIN issuer_cfg[5]
    DIRECTION OUTPUT ;
    USE SIGNAL ;
    PORT
      LAYER M5 ;
        RECT  58.896 0 58.92 0.084 ;
    END
  END issuer_cfg[5]
  PIN issuer_cfg[6]
    DIRECTION OUTPUT ;
    USE SIGNAL ;
    PORT
      LAYER M5 ;
        RECT  58.992 0 59.016 0.084 ;
    END
  END issuer_cfg[6]
  PIN issuer_cfg[7]
    DIRECTION OUTPUT ;
    USE SIGNAL ;
    PORT
      LAYER M5 ;
        RECT  59.088 0 59.112 0.084 ;
    END
  END issuer_cfg[7]
  PIN issuer_cfg[8]
    DIRECTION OUTPUT ;
    USE SIGNAL ;
    PORT
      LAYER M5 ;
        RECT  59.184 0 59.208 0.084 ;
    END
  END issuer_cfg[8]
  PIN issuer_cfg[9]
    DIRECTION OUTPUT ;
    USE SIGNAL ;
    PORT
      LAYER M5 ;
        RECT  59.28 0 59.304 0.084 ;
    END
  END issuer_cfg[9]
  PIN issuer_fault
    DIRECTION INPUT ;
    USE SIGNAL ;
    PORT
      LAYER M5 ;
        RECT  13.968 0 13.992 0.084 ;
    END
  END issuer_fault
  PIN issuer_start
    DIRECTION OUTPUT ;
    USE SIGNAL ;
    PORT
      LAYER M5 ;
        RECT  14.064 0 14.088 0.084 ;
    END
  END issuer_start
  PIN issuer_start_pc[0]
    DIRECTION OUTPUT ;
    USE SIGNAL ;
    PORT
      LAYER M5 ;
        RECT  14.16 0 14.184 0.084 ;
    END
  END issuer_start_pc[0]
  PIN issuer_start_pc[1]
    DIRECTION OUTPUT ;
    USE SIGNAL ;
    PORT
      LAYER M5 ;
        RECT  14.256 0 14.28 0.084 ;
    END
  END issuer_start_pc[1]
  PIN issuer_start_pc[2]
    DIRECTION OUTPUT ;
    USE SIGNAL ;
    PORT
      LAYER M5 ;
        RECT  14.352 0 14.376 0.084 ;
    END
  END issuer_start_pc[2]
  PIN issuer_start_pc[3]
    DIRECTION OUTPUT ;
    USE SIGNAL ;
    PORT
      LAYER M5 ;
        RECT  14.448 0 14.472 0.084 ;
    END
  END issuer_start_pc[3]
  PIN issuer_start_pc[4]
    DIRECTION OUTPUT ;
    USE SIGNAL ;
    PORT
      LAYER M5 ;
        RECT  14.544 0 14.568 0.084 ;
    END
  END issuer_start_pc[4]
  PIN issuer_start_pc[5]
    DIRECTION OUTPUT ;
    USE SIGNAL ;
    PORT
      LAYER M5 ;
        RECT  14.64 0 14.664 0.084 ;
    END
  END issuer_start_pc[5]
  PIN issuer_uop_pc[0]
    DIRECTION INPUT ;
    USE SIGNAL ;
    PORT
      LAYER M5 ;
        RECT  14.736 0 14.76 0.084 ;
    END
  END issuer_uop_pc[0]
  PIN issuer_uop_pc[1]
    DIRECTION INPUT ;
    USE SIGNAL ;
    PORT
      LAYER M5 ;
        RECT  14.832 0 14.856 0.084 ;
    END
  END issuer_uop_pc[1]
  PIN issuer_uop_pc[2]
    DIRECTION INPUT ;
    USE SIGNAL ;
    PORT
      LAYER M5 ;
        RECT  14.928 0 14.952 0.084 ;
    END
  END issuer_uop_pc[2]
  PIN issuer_uop_pc[3]
    DIRECTION INPUT ;
    USE SIGNAL ;
    PORT
      LAYER M5 ;
        RECT  15.024 0 15.048 0.084 ;
    END
  END issuer_uop_pc[3]
  PIN issuer_uop_pc[4]
    DIRECTION INPUT ;
    USE SIGNAL ;
    PORT
      LAYER M5 ;
        RECT  15.12 0 15.144 0.084 ;
    END
  END issuer_uop_pc[4]
  PIN issuer_uop_pc[5]
    DIRECTION INPUT ;
    USE SIGNAL ;
    PORT
      LAYER M5 ;
        RECT  15.216 0 15.24 0.084 ;
    END
  END issuer_uop_pc[5]
  PIN issuer_uop_v
    DIRECTION INPUT ;
    USE SIGNAL ;
    PORT
      LAYER M5 ;
        RECT  15.312 0 15.336 0.084 ;
    END
  END issuer_uop_v
  PIN launch_v
    DIRECTION INPUT ;
    USE SIGNAL ;
    PORT
      LAYER M5 ;
        RECT  10.992 56.076 11.016 56.16 ;
    END
  END launch_v
  PIN link_abort[0]
    DIRECTION INPUT ;
    USE SIGNAL ;
    PORT
      LAYER M4 ;
        RECT  0 31.248 0.084 31.272 ;
    END
  END link_abort[0]
  PIN program_active
    DIRECTION INPUT ;
    USE SIGNAL ;
    PORT
      LAYER M5 ;
        RECT  15.408 0 15.432 0.084 ;
    END
  END program_active
  PIN program_fault
    DIRECTION OUTPUT ;
    USE SIGNAL ;
    PORT
      LAYER M5 ;
        RECT  11.088 56.076 11.112 56.16 ;
    END
  END program_fault
  PIN protocol_fault
    DIRECTION INPUT ;
    USE SIGNAL ;
    PORT
      LAYER M4 ;
        RECT  81.996 30 82.08 30.024 ;
    END
  END protocol_fault
  PIN qid[0]
    DIRECTION INPUT ;
    USE SIGNAL ;
    PORT
      LAYER M5 ;
        RECT  11.184 56.076 11.208 56.16 ;
    END
  END qid[0]
  PIN qid[1]
    DIRECTION INPUT ;
    USE SIGNAL ;
    PORT
      LAYER M5 ;
        RECT  11.28 56.076 11.304 56.16 ;
    END
  END qid[1]
  PIN reduce_fault
    DIRECTION INPUT ;
    USE SIGNAL ;
    PORT
      LAYER M4 ;
        RECT  0 31.344 0.084 31.368 ;
    END
  END reduce_fault
  PIN ring_fault
    DIRECTION INPUT ;
    USE SIGNAL ;
    PORT
      LAYER M4 ;
        RECT  0 31.44 0.084 31.464 ;
    END
  END ring_fault
  PIN rst_n
    DIRECTION INPUT ;
    USE SIGNAL ;
    PORT
      LAYER M5 ;
        RECT  11.376 56.076 11.4 56.16 ;
    END
  END rst_n
  PIN select_fault[0]
    DIRECTION INPUT ;
    USE SIGNAL ;
    PORT
      LAYER M4 ;
        RECT  81.996 30.096 82.08 30.12 ;
    END
  END select_fault[0]
  PIN select_fault[10]
    DIRECTION INPUT ;
    USE SIGNAL ;
    PORT
      LAYER M4 ;
        RECT  81.996 31.056 82.08 31.08 ;
    END
  END select_fault[10]
  PIN select_fault[11]
    DIRECTION INPUT ;
    USE SIGNAL ;
    PORT
      LAYER M4 ;
        RECT  81.996 31.152 82.08 31.176 ;
    END
  END select_fault[11]
  PIN select_fault[12]
    DIRECTION INPUT ;
    USE SIGNAL ;
    PORT
      LAYER M4 ;
        RECT  81.996 31.248 82.08 31.272 ;
    END
  END select_fault[12]
  PIN select_fault[13]
    DIRECTION INPUT ;
    USE SIGNAL ;
    PORT
      LAYER M4 ;
        RECT  81.996 31.344 82.08 31.368 ;
    END
  END select_fault[13]
  PIN select_fault[14]
    DIRECTION INPUT ;
    USE SIGNAL ;
    PORT
      LAYER M4 ;
        RECT  81.996 31.44 82.08 31.464 ;
    END
  END select_fault[14]
  PIN select_fault[15]
    DIRECTION INPUT ;
    USE SIGNAL ;
    PORT
      LAYER M4 ;
        RECT  81.996 31.536 82.08 31.56 ;
    END
  END select_fault[15]
  PIN select_fault[16]
    DIRECTION INPUT ;
    USE SIGNAL ;
    PORT
      LAYER M4 ;
        RECT  81.996 31.632 82.08 31.656 ;
    END
  END select_fault[16]
  PIN select_fault[17]
    DIRECTION INPUT ;
    USE SIGNAL ;
    PORT
      LAYER M4 ;
        RECT  81.996 31.728 82.08 31.752 ;
    END
  END select_fault[17]
  PIN select_fault[1]
    DIRECTION INPUT ;
    USE SIGNAL ;
    PORT
      LAYER M4 ;
        RECT  81.996 30.192 82.08 30.216 ;
    END
  END select_fault[1]
  PIN select_fault[2]
    DIRECTION INPUT ;
    USE SIGNAL ;
    PORT
      LAYER M4 ;
        RECT  81.996 30.288 82.08 30.312 ;
    END
  END select_fault[2]
  PIN select_fault[3]
    DIRECTION INPUT ;
    USE SIGNAL ;
    PORT
      LAYER M4 ;
        RECT  81.996 30.384 82.08 30.408 ;
    END
  END select_fault[3]
  PIN select_fault[4]
    DIRECTION INPUT ;
    USE SIGNAL ;
    PORT
      LAYER M4 ;
        RECT  81.996 30.48 82.08 30.504 ;
    END
  END select_fault[4]
  PIN select_fault[5]
    DIRECTION INPUT ;
    USE SIGNAL ;
    PORT
      LAYER M4 ;
        RECT  81.996 30.576 82.08 30.6 ;
    END
  END select_fault[5]
  PIN select_fault[6]
    DIRECTION INPUT ;
    USE SIGNAL ;
    PORT
      LAYER M4 ;
        RECT  81.996 30.672 82.08 30.696 ;
    END
  END select_fault[6]
  PIN select_fault[7]
    DIRECTION INPUT ;
    USE SIGNAL ;
    PORT
      LAYER M4 ;
        RECT  81.996 30.768 82.08 30.792 ;
    END
  END select_fault[7]
  PIN select_fault[8]
    DIRECTION INPUT ;
    USE SIGNAL ;
    PORT
      LAYER M4 ;
        RECT  81.996 30.864 82.08 30.888 ;
    END
  END select_fault[8]
  PIN select_fault[9]
    DIRECTION INPUT ;
    USE SIGNAL ;
    PORT
      LAYER M4 ;
        RECT  81.996 30.96 82.08 30.984 ;
    END
  END select_fault[9]
  PIN tkm_del_slot[0]
    DIRECTION INPUT ;
    USE SIGNAL ;
    PORT
      LAYER M4 ;
        RECT  81.996 31.824 82.08 31.848 ;
    END
  END tkm_del_slot[0]
  PIN tkm_del_slot[1]
    DIRECTION INPUT ;
    USE SIGNAL ;
    PORT
      LAYER M4 ;
        RECT  81.996 31.92 82.08 31.944 ;
    END
  END tkm_del_slot[1]
  PIN tkm_del_slot[2]
    DIRECTION INPUT ;
    USE SIGNAL ;
    PORT
      LAYER M4 ;
        RECT  81.996 32.016 82.08 32.04 ;
    END
  END tkm_del_slot[2]
  PIN tkm_del_slot[3]
    DIRECTION INPUT ;
    USE SIGNAL ;
    PORT
      LAYER M4 ;
        RECT  81.996 32.112 82.08 32.136 ;
    END
  END tkm_del_slot[3]
  PIN tkm_dest_v[0]
    DIRECTION INPUT ;
    USE SIGNAL ;
    PORT
      LAYER M4 ;
        RECT  81.996 26.064 82.08 26.088 ;
    END
  END tkm_dest_v[0]
  PIN tkm_dest_v[1]
    DIRECTION INPUT ;
    USE SIGNAL ;
    PORT
      LAYER M4 ;
        RECT  81.996 26.16 82.08 26.184 ;
    END
  END tkm_dest_v[1]
  PIN tkm_dest_v[2]
    DIRECTION INPUT ;
    USE SIGNAL ;
    PORT
      LAYER M4 ;
        RECT  81.996 26.256 82.08 26.28 ;
    END
  END tkm_dest_v[2]
  PIN tkm_dest_v[3]
    DIRECTION INPUT ;
    USE SIGNAL ;
    PORT
      LAYER M4 ;
        RECT  81.996 26.352 82.08 26.376 ;
    END
  END tkm_dest_v[3]
  PIN tkm_start
    DIRECTION INPUT ;
    USE SIGNAL ;
    PORT
      LAYER M4 ;
        RECT  81.996 26.448 82.08 26.472 ;
    END
  END tkm_start
  PIN unavailable_fault[0]
    DIRECTION INPUT ;
    USE SIGNAL ;
    PORT
      LAYER M4 ;
        RECT  81.996 26.544 82.08 26.568 ;
    END
  END unavailable_fault[0]
  PIN unavailable_fault[10]
    DIRECTION INPUT ;
    USE SIGNAL ;
    PORT
      LAYER M4 ;
        RECT  81.996 27.504 82.08 27.528 ;
    END
  END unavailable_fault[10]
  PIN unavailable_fault[11]
    DIRECTION INPUT ;
    USE SIGNAL ;
    PORT
      LAYER M4 ;
        RECT  81.996 27.6 82.08 27.624 ;
    END
  END unavailable_fault[11]
  PIN unavailable_fault[12]
    DIRECTION INPUT ;
    USE SIGNAL ;
    PORT
      LAYER M4 ;
        RECT  81.996 27.696 82.08 27.72 ;
    END
  END unavailable_fault[12]
  PIN unavailable_fault[13]
    DIRECTION INPUT ;
    USE SIGNAL ;
    PORT
      LAYER M4 ;
        RECT  81.996 27.792 82.08 27.816 ;
    END
  END unavailable_fault[13]
  PIN unavailable_fault[14]
    DIRECTION INPUT ;
    USE SIGNAL ;
    PORT
      LAYER M4 ;
        RECT  81.996 27.888 82.08 27.912 ;
    END
  END unavailable_fault[14]
  PIN unavailable_fault[15]
    DIRECTION INPUT ;
    USE SIGNAL ;
    PORT
      LAYER M4 ;
        RECT  81.996 27.984 82.08 28.008 ;
    END
  END unavailable_fault[15]
  PIN unavailable_fault[16]
    DIRECTION INPUT ;
    USE SIGNAL ;
    PORT
      LAYER M4 ;
        RECT  81.996 28.08 82.08 28.104 ;
    END
  END unavailable_fault[16]
  PIN unavailable_fault[17]
    DIRECTION INPUT ;
    USE SIGNAL ;
    PORT
      LAYER M4 ;
        RECT  81.996 28.176 82.08 28.2 ;
    END
  END unavailable_fault[17]
  PIN unavailable_fault[1]
    DIRECTION INPUT ;
    USE SIGNAL ;
    PORT
      LAYER M4 ;
        RECT  81.996 26.64 82.08 26.664 ;
    END
  END unavailable_fault[1]
  PIN unavailable_fault[2]
    DIRECTION INPUT ;
    USE SIGNAL ;
    PORT
      LAYER M4 ;
        RECT  81.996 26.736 82.08 26.76 ;
    END
  END unavailable_fault[2]
  PIN unavailable_fault[3]
    DIRECTION INPUT ;
    USE SIGNAL ;
    PORT
      LAYER M4 ;
        RECT  81.996 26.832 82.08 26.856 ;
    END
  END unavailable_fault[3]
  PIN unavailable_fault[4]
    DIRECTION INPUT ;
    USE SIGNAL ;
    PORT
      LAYER M4 ;
        RECT  81.996 26.928 82.08 26.952 ;
    END
  END unavailable_fault[4]
  PIN unavailable_fault[5]
    DIRECTION INPUT ;
    USE SIGNAL ;
    PORT
      LAYER M4 ;
        RECT  81.996 27.024 82.08 27.048 ;
    END
  END unavailable_fault[5]
  PIN unavailable_fault[6]
    DIRECTION INPUT ;
    USE SIGNAL ;
    PORT
      LAYER M4 ;
        RECT  81.996 27.12 82.08 27.144 ;
    END
  END unavailable_fault[6]
  PIN unavailable_fault[7]
    DIRECTION INPUT ;
    USE SIGNAL ;
    PORT
      LAYER M4 ;
        RECT  81.996 27.216 82.08 27.24 ;
    END
  END unavailable_fault[7]
  PIN unavailable_fault[8]
    DIRECTION INPUT ;
    USE SIGNAL ;
    PORT
      LAYER M4 ;
        RECT  81.996 27.312 82.08 27.336 ;
    END
  END unavailable_fault[8]
  PIN unavailable_fault[9]
    DIRECTION INPUT ;
    USE SIGNAL ;
    PORT
      LAYER M4 ;
        RECT  81.996 27.408 82.08 27.432 ;
    END
  END unavailable_fault[9]
  PIN writer_fault
    DIRECTION INPUT ;
    USE SIGNAL ;
    PORT
      LAYER M4 ;
        RECT  0 31.536 0.084 31.56 ;
    END
  END writer_fault
  PIN VDD
    DIRECTION INOUT ;
    USE POWER ;
    PORT
      LAYER M5 ;
        RECT  78.192 2.151 78.312 54.009 ;
        RECT  72.792 2.151 72.912 54.009 ;
        RECT  67.392 2.151 67.512 54.009 ;
        RECT  61.992 2.151 62.112 54.009 ;
        RECT  56.592 2.151 56.712 54.009 ;
        RECT  51.192 2.151 51.312 54.009 ;
        RECT  45.792 2.151 45.912 54.009 ;
        RECT  40.392 2.151 40.512 54.009 ;
        RECT  34.992 2.151 35.112 54.009 ;
        RECT  29.592 2.151 29.712 54.009 ;
        RECT  24.192 2.151 24.312 54.009 ;
        RECT  18.792 2.151 18.912 54.009 ;
        RECT  13.392 2.151 13.512 54.009 ;
        RECT  7.992 2.151 8.112 54.009 ;
        RECT  2.592 2.151 2.712 54.009 ;
    END
  END VDD
  PIN VSS
    DIRECTION INOUT ;
    USE GROUND ;
    PORT
      LAYER M5 ;
        RECT  78 2.137 78.12 54.023 ;
        RECT  72.6 2.137 72.72 54.023 ;
        RECT  67.2 2.137 67.32 54.023 ;
        RECT  61.8 2.137 61.92 54.023 ;
        RECT  56.4 2.137 56.52 54.023 ;
        RECT  51 2.137 51.12 54.023 ;
        RECT  45.6 2.137 45.72 54.023 ;
        RECT  40.2 2.137 40.32 54.023 ;
        RECT  34.8 2.137 34.92 54.023 ;
        RECT  29.4 2.137 29.52 54.023 ;
        RECT  24 2.137 24.12 54.023 ;
        RECT  18.6 2.137 18.72 54.023 ;
        RECT  13.2 2.137 13.32 54.023 ;
        RECT  7.8 2.137 7.92 54.023 ;
        RECT  2.4 2.137 2.52 54.023 ;
    END
  END VSS
  # OT_OBS_CLOSED layer=M5 d_um=1.536 added=695
  OBS
    LAYER RVTN ;
     RECT  2.16 2.16 79.92 2.295 ;
     RECT  2.16 2.565 79.92 2.835 ;
     RECT  2.16 3.105 79.92 3.375 ;
     RECT  2.16 3.645 79.92 3.915 ;
     RECT  2.16 4.185 79.92 4.455 ;
     RECT  2.16 4.725 79.92 4.995 ;
     RECT  2.16 5.265 79.92 5.535 ;
     RECT  2.16 5.805 79.92 6.075 ;
     RECT  2.16 6.345 79.92 6.615 ;
     RECT  2.16 6.885 79.92 7.155 ;
     RECT  2.16 7.425 79.92 7.695 ;
     RECT  2.16 7.965 79.92 8.235 ;
     RECT  2.16 8.505 79.92 8.775 ;
     RECT  2.16 9.045 79.92 9.315 ;
     RECT  2.16 9.585 79.92 9.855 ;
     RECT  2.16 10.125 79.92 10.395 ;
     RECT  2.16 10.665 79.92 10.935 ;
     RECT  2.16 11.205 79.92 11.475 ;
     RECT  2.16 11.745 79.92 12.015 ;
     RECT  2.16 12.285 79.92 12.555 ;
     RECT  2.16 12.825 79.92 13.095 ;
     RECT  2.16 13.365 79.92 13.635 ;
     RECT  2.16 13.905 79.92 14.175 ;
     RECT  2.16 14.445 79.92 14.715 ;
     RECT  2.16 14.985 79.92 15.255 ;
     RECT  2.16 15.525 79.92 15.795 ;
     RECT  2.16 16.065 79.92 16.335 ;
     RECT  2.16 16.605 79.92 16.875 ;
     RECT  2.16 17.145 79.92 17.415 ;
     RECT  2.16 17.685 79.92 17.955 ;
     RECT  2.16 18.225 79.92 18.495 ;
     RECT  2.16 18.765 79.92 19.035 ;
     RECT  2.16 19.305 79.92 19.575 ;
     RECT  2.16 19.845 79.92 20.115 ;
     RECT  2.16 20.385 79.92 20.655 ;
     RECT  2.16 20.925 79.92 21.195 ;
     RECT  2.16 21.465 79.92 21.735 ;
     RECT  2.16 22.005 79.92 22.275 ;
     RECT  2.16 22.545 79.92 22.815 ;
     RECT  2.16 23.085 79.92 23.355 ;
     RECT  2.16 23.625 79.92 23.895 ;
     RECT  2.16 24.165 79.92 24.435 ;
     RECT  2.16 24.705 79.92 24.975 ;
     RECT  2.16 25.245 79.92 25.515 ;
     RECT  2.16 25.785 79.92 26.055 ;
     RECT  2.16 26.325 79.92 26.595 ;
     RECT  2.16 26.865 79.92 27.135 ;
     RECT  2.16 27.405 79.92 27.675 ;
     RECT  2.16 27.945 79.92 28.215 ;
     RECT  2.16 28.485 79.92 28.755 ;
     RECT  2.16 29.025 79.92 29.295 ;
     RECT  2.16 29.565 79.92 29.835 ;
     RECT  2.16 30.105 79.92 30.375 ;
     RECT  2.16 30.645 79.92 30.915 ;
     RECT  2.16 31.185 79.92 31.455 ;
     RECT  2.16 31.725 79.92 31.995 ;
     RECT  2.16 32.265 79.92 32.535 ;
     RECT  2.16 32.805 79.92 33.075 ;
     RECT  2.16 33.345 79.92 33.615 ;
     RECT  2.16 33.885 79.92 34.155 ;
     RECT  2.16 34.425 79.92 34.695 ;
     RECT  2.16 34.965 79.92 35.235 ;
     RECT  2.16 35.505 79.92 35.775 ;
     RECT  2.16 36.045 79.92 36.315 ;
     RECT  2.16 36.585 79.92 36.855 ;
     RECT  2.16 37.125 79.92 37.395 ;
     RECT  2.16 37.665 79.92 37.935 ;
     RECT  2.16 38.205 79.92 38.475 ;
     RECT  2.16 38.745 79.92 39.015 ;
     RECT  2.16 39.285 79.92 39.555 ;
     RECT  2.16 39.825 79.92 40.095 ;
     RECT  2.16 40.365 79.92 40.635 ;
     RECT  2.16 40.905 79.92 41.175 ;
     RECT  2.16 41.445 79.92 41.715 ;
     RECT  2.16 41.985 79.92 42.255 ;
     RECT  2.16 42.525 79.92 42.795 ;
     RECT  2.16 43.065 79.92 43.335 ;
     RECT  2.16 43.605 79.92 43.875 ;
     RECT  2.16 44.145 79.92 44.415 ;
     RECT  2.16 44.685 79.92 44.955 ;
     RECT  2.16 45.225 79.92 45.495 ;
     RECT  2.16 45.765 79.92 46.035 ;
     RECT  2.16 46.305 79.92 46.575 ;
     RECT  2.16 46.845 79.92 47.115 ;
     RECT  2.16 47.385 79.92 47.655 ;
     RECT  2.16 47.925 79.92 48.195 ;
     RECT  2.16 48.465 79.92 48.735 ;
     RECT  2.16 49.005 79.92 49.275 ;
     RECT  2.16 49.545 79.92 49.815 ;
     RECT  2.16 50.085 79.92 50.355 ;
     RECT  2.16 50.625 79.92 50.895 ;
     RECT  2.16 51.165 79.92 51.435 ;
     RECT  2.16 51.705 79.92 51.975 ;
     RECT  2.16 52.245 79.92 52.515 ;
     RECT  2.16 52.785 79.92 53.055 ;
     RECT  2.16 53.325 79.92 53.595 ;
     RECT  2.16 53.865 79.92 54 ;
    LAYER RVTP ;
     RECT  2.16 2.295 79.92 2.565 ;
     RECT  2.16 2.835 79.92 3.105 ;
     RECT  2.16 3.375 79.92 3.645 ;
     RECT  2.16 3.915 79.92 4.185 ;
     RECT  2.16 4.455 79.92 4.725 ;
     RECT  2.16 4.995 79.92 5.265 ;
     RECT  2.16 5.535 79.92 5.805 ;
     RECT  2.16 6.075 79.92 6.345 ;
     RECT  2.16 6.615 79.92 6.885 ;
     RECT  2.16 7.155 79.92 7.425 ;
     RECT  2.16 7.695 79.92 7.965 ;
     RECT  2.16 8.235 79.92 8.505 ;
     RECT  2.16 8.775 79.92 9.045 ;
     RECT  2.16 9.315 79.92 9.585 ;
     RECT  2.16 9.855 79.92 10.125 ;
     RECT  2.16 10.395 79.92 10.665 ;
     RECT  2.16 10.935 79.92 11.205 ;
     RECT  2.16 11.475 79.92 11.745 ;
     RECT  2.16 12.015 79.92 12.285 ;
     RECT  2.16 12.555 79.92 12.825 ;
     RECT  2.16 13.095 79.92 13.365 ;
     RECT  2.16 13.635 79.92 13.905 ;
     RECT  2.16 14.175 79.92 14.445 ;
     RECT  2.16 14.715 79.92 14.985 ;
     RECT  2.16 15.255 79.92 15.525 ;
     RECT  2.16 15.795 79.92 16.065 ;
     RECT  2.16 16.335 79.92 16.605 ;
     RECT  2.16 16.875 79.92 17.145 ;
     RECT  2.16 17.415 79.92 17.685 ;
     RECT  2.16 17.955 79.92 18.225 ;
     RECT  2.16 18.495 79.92 18.765 ;
     RECT  2.16 19.035 79.92 19.305 ;
     RECT  2.16 19.575 79.92 19.845 ;
     RECT  2.16 20.115 79.92 20.385 ;
     RECT  2.16 20.655 79.92 20.925 ;
     RECT  2.16 21.195 79.92 21.465 ;
     RECT  2.16 21.735 79.92 22.005 ;
     RECT  2.16 22.275 79.92 22.545 ;
     RECT  2.16 22.815 79.92 23.085 ;
     RECT  2.16 23.355 79.92 23.625 ;
     RECT  2.16 23.895 79.92 24.165 ;
     RECT  2.16 24.435 79.92 24.705 ;
     RECT  2.16 24.975 79.92 25.245 ;
     RECT  2.16 25.515 79.92 25.785 ;
     RECT  2.16 26.055 79.92 26.325 ;
     RECT  2.16 26.595 79.92 26.865 ;
     RECT  2.16 27.135 79.92 27.405 ;
     RECT  2.16 27.675 79.92 27.945 ;
     RECT  2.16 28.215 79.92 28.485 ;
     RECT  2.16 28.755 79.92 29.025 ;
     RECT  2.16 29.295 79.92 29.565 ;
     RECT  2.16 29.835 79.92 30.105 ;
     RECT  2.16 30.375 79.92 30.645 ;
     RECT  2.16 30.915 79.92 31.185 ;
     RECT  2.16 31.455 79.92 31.725 ;
     RECT  2.16 31.995 79.92 32.265 ;
     RECT  2.16 32.535 79.92 32.805 ;
     RECT  2.16 33.075 79.92 33.345 ;
     RECT  2.16 33.615 79.92 33.885 ;
     RECT  2.16 34.155 79.92 34.425 ;
     RECT  2.16 34.695 79.92 34.965 ;
     RECT  2.16 35.235 79.92 35.505 ;
     RECT  2.16 35.775 79.92 36.045 ;
     RECT  2.16 36.315 79.92 36.585 ;
     RECT  2.16 36.855 79.92 37.125 ;
     RECT  2.16 37.395 79.92 37.665 ;
     RECT  2.16 37.935 79.92 38.205 ;
     RECT  2.16 38.475 79.92 38.745 ;
     RECT  2.16 39.015 79.92 39.285 ;
     RECT  2.16 39.555 79.92 39.825 ;
     RECT  2.16 40.095 79.92 40.365 ;
     RECT  2.16 40.635 79.92 40.905 ;
     RECT  2.16 41.175 79.92 41.445 ;
     RECT  2.16 41.715 79.92 41.985 ;
     RECT  2.16 42.255 79.92 42.525 ;
     RECT  2.16 42.795 79.92 43.065 ;
     RECT  2.16 43.335 79.92 43.605 ;
     RECT  2.16 43.875 79.92 44.145 ;
     RECT  2.16 44.415 79.92 44.685 ;
     RECT  2.16 44.955 79.92 45.225 ;
     RECT  2.16 45.495 79.92 45.765 ;
     RECT  2.16 46.035 79.92 46.305 ;
     RECT  2.16 46.575 79.92 46.845 ;
     RECT  2.16 47.115 79.92 47.385 ;
     RECT  2.16 47.655 79.92 47.925 ;
     RECT  2.16 48.195 79.92 48.465 ;
     RECT  2.16 48.735 79.92 49.005 ;
     RECT  2.16 49.275 79.92 49.545 ;
     RECT  2.16 49.815 79.92 50.085 ;
     RECT  2.16 50.355 79.92 50.625 ;
     RECT  2.16 50.895 79.92 51.165 ;
     RECT  2.16 51.435 79.92 51.705 ;
     RECT  2.16 51.975 79.92 52.245 ;
     RECT  2.16 52.515 79.92 52.785 ;
     RECT  2.16 53.055 79.92 53.325 ;
     RECT  2.16 53.595 79.92 53.865 ;
    LAYER M1 ;
     RECT  2.16 2.151 79.92 54.009 ;
    LAYER M2 ;
     RECT  1.687 52.83 1.939 53.01 ;
     RECT  1.687 53.91 1.939 53.928 ;
     RECT  1.939 46.89 1.975 46.908 ;
     RECT  1.939 52.83 2.047 53.928 ;
     RECT  2.047 49.014 2.083 49.032 ;
     RECT  2.083 49.014 2.155 49.644 ;
     RECT  2.011 46.116 2.16 46.134 ;
     RECT  1.975 46.89 2.16 47.412 ;
     RECT  2.155 48.906 2.16 50.148 ;
     RECT  2.011 50.904 2.16 50.922 ;
     RECT  2.047 52.416 2.16 53.928 ;
     RECT  2.16 2.151 10.147 54.009 ;
     RECT  10.147 2.151 10.247 54.702 ;
     RECT  10.247 2.151 18.067 54.009 ;
     RECT  18.067 2.151 18.923 54.054 ;
     RECT  18.923 2.151 57.091 54.009 ;
     RECT  57.091 2.151 60.583 54.126 ;
     RECT  60.583 2.034 60.863 54.126 ;
     RECT  60.863 2.034 61.555 54.009 ;
     RECT  61.555 1.962 62.735 54.009 ;
     RECT  62.735 2.106 63.995 54.009 ;
     RECT  63.995 2.151 79.92 54.009 ;
     RECT  79.92 26.532 80.375 33.84 ;
     RECT  80.375 26.532 80.879 33.606 ;
     RECT  80.879 26.532 80.915 33.336 ;
     RECT  80.915 26.532 80.951 29.862 ;
     RECT  80.915 30.924 80.951 33.336 ;
     RECT  80.951 31.536 81.455 32.49 ;
     RECT  80.951 27.612 81.491 27.702 ;
     RECT  80.951 28.8 81.491 29.862 ;
     RECT  81.455 32.472 81.491 32.49 ;
     RECT  81.491 29.304 81.527 29.862 ;
     RECT  80.951 33.318 81.923 33.336 ;
     RECT  81.491 27.684 81.995 27.702 ;
     RECT  81.527 29.844 81.995 29.862 ;
     RECT  81.455 31.536 81.995 31.554 ;
    LAYER M3 ;
     RECT  59.256 0.091 59.634 0.235 ;
     RECT  58.644 0.235 59.634 0.571 ;
     RECT  58.644 0.571 59.958 0.619 ;
     RECT  58.644 0.619 60.426 1.003 ;
     RECT  13.68 0.091 14.382 1.099 ;
     RECT  58.536 1.003 60.426 1.099 ;
     RECT  58.5 1.099 60.426 1.147 ;
     RECT  13.356 1.099 14.382 1.723 ;
     RECT  57.852 1.147 60.642 1.723 ;
     RECT  57.852 1.723 61.542 1.957 ;
     RECT  63.216 1.771 63.234 1.957 ;
     RECT  57.852 1.957 61.578 1.993 ;
     RECT  57.852 1.993 61.974 2.029 ;
     RECT  62.712 1.957 63.234 2.029 ;
     RECT  13.356 1.723 15.822 2.143 ;
     RECT  13.215 2.143 15.822 2.191 ;
     RECT  29.415 2.143 29.505 2.191 ;
     RECT  57.852 2.029 63.234 2.227 ;
     RECT  63.972 2.101 63.99 2.227 ;
     RECT  27.252 2.191 27.27 2.237 ;
     RECT  25.416 2.227 25.434 2.263 ;
     RECT  32.22 2.191 32.238 2.263 ;
     RECT  37.404 2.227 37.422 2.263 ;
     RECT  57.852 2.227 63.99 2.263 ;
     RECT  47.376 2.227 47.394 2.293 ;
     RECT  53.316 2.227 53.334 2.293 ;
     RECT  24.015 2.143 24.105 2.299 ;
     RECT  25.416 2.263 25.758 2.299 ;
     RECT  29.415 2.191 30.222 2.299 ;
     RECT  34.815 2.143 34.905 2.299 ;
     RECT  37.404 2.263 37.818 2.299 ;
     RECT  52.776 2.293 53.334 2.299 ;
     RECT  47.196 2.293 47.394 2.332 ;
     RECT  13.104 2.191 15.822 2.335 ;
     RECT  18.615 2.143 18.705 2.335 ;
     RECT  21.852 2.299 22.266 2.335 ;
     RECT  23.976 2.299 24.138 2.335 ;
     RECT  34.236 2.299 34.905 2.335 ;
     RECT  37.188 2.299 38.394 2.335 ;
     RECT  40.215 2.143 40.305 2.335 ;
     RECT  41.22 2.227 42.03 2.335 ;
     RECT  42.768 2.299 42.786 2.335 ;
     RECT  48.42 2.299 48.438 2.335 ;
     RECT  52.776 2.299 53.406 2.335 ;
     RECT  31.788 2.263 32.238 2.347 ;
     RECT  32.976 2.335 32.994 2.347 ;
     RECT  48.42 2.335 48.474 2.347 ;
     RECT  12.996 2.335 16.398 2.371 ;
     RECT  18.615 2.335 19.314 2.371 ;
     RECT  21.78 2.335 22.77 2.371 ;
     RECT  25.416 2.299 26.406 2.371 ;
     RECT  31.788 2.347 32.994 2.371 ;
     RECT  40.215 2.335 42.03 2.371 ;
     RECT  47.16 2.332 47.394 2.371 ;
     RECT  48.348 2.347 48.474 2.371 ;
     RECT  52.704 2.335 53.406 2.371 ;
     RECT  56.415 2.143 56.505 2.371 ;
     RECT  57.852 2.263 64.35 2.371 ;
     RECT  2.415 2.143 2.505 2.413 ;
     RECT  7.815 2.143 7.905 2.413 ;
     RECT  23.904 2.335 24.138 2.413 ;
     RECT  34.056 2.335 34.905 2.413 ;
     RECT  45.615 2.143 45.705 2.413 ;
     RECT  51.015 2.143 51.105 2.413 ;
     RECT  67.215 2.143 67.305 2.413 ;
     RECT  72.615 2.143 72.705 2.413 ;
     RECT  78.015 2.143 78.105 2.413 ;
     RECT  47.16 2.371 48.474 2.443 ;
     RECT  17.388 2.299 17.406 2.461 ;
     RECT  18.615 2.371 19.71 2.461 ;
     RECT  23.904 2.413 24.297 2.461 ;
     RECT  25.056 2.371 26.874 2.461 ;
     RECT  36.108 2.371 36.126 2.461 ;
     RECT  37.152 2.335 38.466 2.461 ;
     RECT  40.212 2.371 42.03 2.461 ;
     RECT  42.768 2.335 42.822 2.461 ;
     RECT  28.008 2.371 28.35 2.491 ;
     RECT  29.088 2.299 30.222 2.491 ;
     RECT  17.388 2.461 19.71 2.497 ;
     RECT  21.6 2.371 22.77 2.497 ;
     RECT  65.952 2.335 65.97 2.497 ;
     RECT  37.152 2.461 39.474 2.533 ;
     RECT  40.212 2.461 42.822 2.533 ;
     RECT  36.108 2.461 36.342 2.539 ;
     RECT  37.152 2.533 42.822 2.539 ;
     RECT  12.996 2.371 16.614 2.569 ;
     RECT  21.6 2.497 22.95 2.569 ;
     RECT  23.904 2.461 26.874 2.569 ;
     RECT  31.788 2.371 33.03 2.569 ;
     RECT  34.056 2.413 35.097 2.569 ;
     RECT  36.108 2.539 42.822 2.569 ;
     RECT  44.208 2.497 44.226 2.569 ;
     RECT  65.952 2.497 66.114 2.569 ;
     RECT  52.416 2.371 53.406 2.587 ;
     RECT  12.78 2.569 16.614 2.605 ;
     RECT  17.388 2.497 20.142 2.605 ;
     RECT  21.6 2.569 26.874 2.605 ;
     RECT  44.172 2.569 44.226 2.605 ;
     RECT  45.615 2.413 45.897 2.605 ;
     RECT  47.16 2.443 48.762 2.605 ;
     RECT  52.416 2.587 53.514 2.605 ;
     RECT  54.252 2.491 54.27 2.605 ;
     RECT  31.788 2.569 42.822 2.635 ;
     RECT  28.008 2.491 30.402 2.641 ;
     RECT  31.356 2.635 42.822 2.641 ;
     RECT  44.172 2.605 44.766 2.641 ;
     RECT  45.615 2.605 45.99 2.641 ;
     RECT  47.16 2.605 48.798 2.641 ;
     RECT  49.752 2.605 49.878 2.641 ;
     RECT  52.416 2.605 54.27 2.641 ;
     RECT  55.044 2.371 55.062 2.641 ;
     RECT  56.415 2.371 64.35 2.641 ;
     RECT  65.952 2.569 66.15 2.641 ;
     RECT  67.215 2.413 67.497 2.641 ;
     RECT  43.776 2.641 48.798 2.683 ;
     RECT  12.78 2.605 20.142 2.731 ;
     RECT  43.632 2.683 48.798 2.731 ;
     RECT  49.716 2.641 49.878 2.731 ;
     RECT  51.015 2.413 51.297 2.731 ;
     RECT  43.632 2.731 49.878 2.767 ;
     RECT  50.76 2.731 51.297 2.767 ;
     RECT  11.664 2.731 11.682 2.803 ;
     RECT  12.492 2.731 20.142 2.803 ;
     RECT  43.632 2.767 51.297 2.803 ;
     RECT  11.196 2.803 11.682 2.839 ;
     RECT  12.492 2.803 20.25 2.839 ;
     RECT  69.624 2.803 69.75 2.839 ;
     RECT  28.008 2.641 42.822 2.875 ;
     RECT  43.632 2.803 51.606 2.875 ;
     RECT  52.416 2.641 55.062 2.875 ;
     RECT  65.952 2.641 67.497 2.875 ;
     RECT  11.196 2.839 20.25 2.911 ;
     RECT  20.988 2.605 26.874 2.911 ;
     RECT  69.372 2.839 69.75 2.911 ;
     RECT  11.196 2.911 26.874 3.001 ;
     RECT  27.612 2.875 42.822 3.001 ;
     RECT  69.228 2.911 69.75 3.109 ;
     RECT  7.815 2.413 8.097 3.181 ;
     RECT  65.736 2.875 67.497 3.271 ;
     RECT  9.504 3.181 9.522 3.299 ;
     RECT  11.196 3.001 42.822 3.307 ;
     RECT  43.632 2.875 55.062 3.307 ;
     RECT  70.956 3.109 70.974 3.307 ;
     RECT  7.815 3.181 8.298 3.343 ;
     RECT  11.196 3.307 55.062 3.379 ;
     RECT  56.415 2.641 64.566 3.379 ;
     RECT  56.232 3.379 64.566 3.415 ;
     RECT  70.884 3.307 70.974 3.415 ;
     RECT  10.764 3.379 55.062 3.437 ;
     RECT  68.796 3.109 69.75 3.451 ;
     RECT  70.884 3.415 71.082 3.451 ;
     RECT  65.736 3.271 67.626 3.613 ;
     RECT  68.796 3.451 70.002 3.613 ;
     RECT  56.088 3.415 64.566 3.649 ;
     RECT  65.664 3.613 67.626 3.649 ;
     RECT  11.016 3.437 55.062 3.685 ;
     RECT  68.796 3.613 70.074 3.685 ;
     RECT  70.812 3.451 71.082 3.685 ;
     RECT  77.184 3.643 77.202 3.691 ;
     RECT  5.652 3.685 5.67 3.721 ;
     RECT  7.815 3.343 8.694 3.721 ;
     RECT  11.016 3.685 55.134 3.811 ;
     RECT  68.796 3.685 71.082 3.839 ;
     RECT  7.815 3.721 8.946 3.955 ;
     RECT  5.652 3.721 6.39 3.991 ;
     RECT  5.652 3.991 6.534 4.075 ;
     RECT  7.344 3.955 8.946 4.075 ;
     RECT  56.088 3.649 67.626 4.081 ;
     RECT  11.016 3.811 55.314 4.189 ;
     RECT  56.088 4.081 67.698 4.189 ;
     RECT  5.652 4.075 8.946 4.261 ;
     RECT  9.684 3.721 9.702 4.261 ;
     RECT  11.016 4.189 67.77 4.261 ;
     RECT  68.796 3.839 70.974 4.261 ;
     RECT  10.836 4.261 70.974 4.495 ;
     RECT  5.652 4.261 9.702 4.531 ;
     RECT  10.764 4.495 70.974 4.531 ;
     RECT  5.652 4.531 70.974 4.621 ;
     RECT  5.256 4.621 70.974 4.693 ;
     RECT  5.184 4.693 70.974 4.729 ;
     RECT  72.615 2.413 72.897 4.729 ;
     RECT  5.04 4.729 71.262 4.801 ;
     RECT  72.615 4.729 73.35 4.801 ;
     RECT  4.896 4.801 71.262 4.891 ;
     RECT  72.615 4.801 74.286 4.927 ;
     RECT  4.896 4.891 71.442 4.963 ;
     RECT  72.615 4.927 74.718 4.999 ;
     RECT  77.184 3.691 77.274 5.035 ;
     RECT  4.896 4.963 71.622 5.071 ;
     RECT  4.752 5.071 71.622 5.233 ;
     RECT  72.468 4.999 74.718 5.233 ;
     RECT  3.744 4.621 3.762 5.431 ;
     RECT  4.752 5.233 74.718 5.495 ;
     RECT  4.752 5.495 9.126 5.603 ;
     RECT  3.744 5.431 3.978 5.611 ;
     RECT  4.752 5.603 9.018 5.611 ;
     RECT  2.415 2.413 2.697 5.707 ;
     RECT  10.116 5.495 74.718 5.809 ;
     RECT  10.116 5.809 74.862 5.845 ;
     RECT  10.116 5.845 75.042 5.873 ;
     RECT  10.26 5.873 75.042 5.881 ;
     RECT  10.26 5.881 75.69 5.999 ;
     RECT  3.744 5.611 9.018 6.143 ;
     RECT  2.415 5.707 2.826 6.151 ;
     RECT  3.744 6.143 8.91 6.151 ;
     RECT  2.415 6.151 2.862 6.235 ;
     RECT  3.636 6.151 8.91 6.235 ;
     RECT  2.415 6.235 8.91 6.925 ;
     RECT  2.415 6.925 9.234 6.955 ;
     RECT  10.26 5.999 75.366 6.955 ;
     RECT  2.415 6.955 75.366 6.961 ;
     RECT  76.644 5.035 77.274 6.961 ;
     RECT  78.015 2.413 78.297 6.961 ;
     RECT  2.415 6.961 75.546 7.051 ;
     RECT  76.644 6.961 78.297 7.231 ;
     RECT  76.644 7.231 78.462 7.321 ;
     RECT  76.644 7.321 78.498 7.387 ;
     RECT  79.236 7.231 79.254 7.387 ;
     RECT  76.644 7.387 79.254 7.501 ;
     RECT  76.608 7.501 79.254 7.529 ;
     RECT  2.415 7.051 75.798 7.591 ;
     RECT  2.415 7.591 75.834 7.663 ;
     RECT  76.608 7.529 78.714 7.663 ;
     RECT  2.415 7.663 78.714 8.537 ;
     RECT  79.056 8.851 79.182 8.969 ;
     RECT  79.056 8.969 79.074 9.239 ;
     RECT  2.415 8.537 78.297 9.481 ;
     RECT  2.415 9.481 78.822 9.779 ;
     RECT  2.415 9.779 78.75 10.193 ;
     RECT  2.415 10.193 73.638 10.229 ;
     RECT  74.664 10.193 78.75 10.589 ;
     RECT  74.664 10.589 78.39 11.173 ;
     RECT  74.52 11.173 78.39 11.245 ;
     RECT  2.415 10.229 73.53 11.371 ;
     RECT  2.415 11.371 73.602 11.407 ;
     RECT  74.448 11.245 78.39 11.407 ;
     RECT  2.415 11.407 78.75 11.515 ;
     RECT  2.415 11.515 78.894 11.939 ;
     RECT  2.415 11.939 78.75 12.605 ;
     RECT  2.415 12.605 73.026 12.623 ;
     RECT  73.8 12.605 78.75 12.623 ;
     RECT  74.736 12.623 78.75 12.749 ;
     RECT  74.772 12.749 78.75 13.063 ;
     RECT  74.772 13.063 78.894 13.433 ;
     RECT  2.415 12.623 72.954 13.531 ;
     RECT  73.8 12.623 73.962 13.531 ;
     RECT  74.772 13.433 76.374 13.559 ;
     RECT  2.415 13.531 73.962 13.711 ;
     RECT  74.772 13.559 76.266 13.711 ;
     RECT  2.415 13.711 76.266 14.171 ;
     RECT  77.292 13.433 78.894 14.179 ;
     RECT  77.292 14.179 78.966 14.251 ;
     RECT  75.672 14.171 76.266 14.449 ;
     RECT  2.415 14.171 74.79 14.477 ;
     RECT  75.672 14.449 76.338 14.485 ;
     RECT  77.22 14.251 78.966 14.485 ;
     RECT  8.82 14.477 74.79 14.639 ;
     RECT  10.26 14.639 74.79 14.675 ;
     RECT  8.82 14.639 9.414 14.711 ;
     RECT  10.44 14.675 74.79 14.747 ;
     RECT  10.44 14.747 73.674 14.945 ;
     RECT  75.672 14.485 78.966 15.025 ;
     RECT  10.44 14.945 70.002 15.053 ;
     RECT  10.512 15.053 70.002 15.179 ;
     RECT  75.672 15.025 79.002 15.187 ;
     RECT  70.74 14.945 73.674 15.215 ;
     RECT  75.672 15.187 79.11 15.223 ;
     RECT  10.512 15.179 69.858 15.245 ;
     RECT  70.992 15.215 73.674 15.287 ;
     RECT  74.448 14.747 74.79 15.295 ;
     RECT  75.528 15.223 79.11 15.295 ;
     RECT  10.512 15.245 69.822 15.323 ;
     RECT  2.415 14.477 8.097 15.331 ;
     RECT  8.82 14.711 9.162 15.331 ;
     RECT  74.448 15.295 79.146 15.593 ;
     RECT  71.028 15.287 73.674 15.595 ;
     RECT  74.448 15.593 79.11 15.595 ;
     RECT  10.512 15.323 69.534 15.719 ;
     RECT  2.415 15.331 9.162 15.961 ;
     RECT  71.028 15.595 79.11 16.033 ;
     RECT  10.512 15.719 69.066 16.061 ;
     RECT  10.512 16.061 63.882 16.069 ;
     RECT  70.848 16.033 79.11 16.141 ;
     RECT  2.415 15.961 9.45 16.259 ;
     RECT  64.656 16.061 69.066 16.259 ;
     RECT  3.708 16.259 9.45 16.267 ;
     RECT  70.632 16.141 79.11 16.303 ;
     RECT  3.708 16.267 9.594 16.339 ;
     RECT  10.476 16.069 63.882 16.339 ;
     RECT  70.56 16.303 79.11 16.339 ;
     RECT  3.708 16.339 63.882 16.403 ;
     RECT  70.38 16.339 79.11 16.411 ;
     RECT  64.836 16.259 69.066 16.501 ;
     RECT  70.272 16.411 79.11 16.501 ;
     RECT  64.836 16.501 79.11 16.601 ;
     RECT  64.836 16.601 78.966 17.141 ;
     RECT  2.415 16.259 2.934 17.149 ;
     RECT  3.78 16.403 63.882 17.149 ;
     RECT  64.836 17.141 78.93 17.681 ;
     RECT  2.415 17.149 63.882 17.851 ;
     RECT  64.836 17.681 78.894 17.851 ;
     RECT  2.415 17.851 78.894 17.987 ;
     RECT  3.744 17.987 78.894 18.029 ;
     RECT  3.744 18.029 66.078 18.563 ;
     RECT  66.888 18.029 78.894 18.725 ;
     RECT  2.415 17.987 2.97 18.733 ;
     RECT  3.744 18.563 4.698 18.733 ;
     RECT  5.436 18.563 66.078 18.769 ;
     RECT  66.888 18.725 76.95 18.769 ;
     RECT  77.688 18.725 78.894 18.805 ;
     RECT  77.688 18.805 78.966 18.845 ;
     RECT  5.436 18.769 76.95 19.037 ;
     RECT  5.436 19.037 43.614 19.139 ;
     RECT  2.415 18.733 4.698 19.381 ;
     RECT  5.436 19.139 43.578 19.381 ;
     RECT  77.688 18.845 78.93 19.579 ;
     RECT  44.388 19.037 76.95 19.651 ;
     RECT  77.688 19.579 78.966 19.651 ;
     RECT  44.388 19.651 78.966 19.877 ;
     RECT  77.616 19.877 78.966 19.885 ;
     RECT  2.415 19.381 43.578 20.011 ;
     RECT  44.388 19.877 76.698 20.011 ;
     RECT  2.415 20.011 76.698 20.623 ;
     RECT  2.415 20.623 76.806 20.659 ;
     RECT  77.616 19.885 79.398 20.659 ;
     RECT  2.415 20.659 79.398 20.849 ;
     RECT  2.415 20.849 78.786 22.235 ;
     RECT  2.415 22.235 69.606 22.315 ;
     RECT  2.376 22.315 69.606 22.379 ;
     RECT  70.344 22.235 78.786 22.811 ;
     RECT  70.344 22.811 78.678 22.883 ;
     RECT  2.415 22.379 69.606 23.125 ;
     RECT  70.344 22.883 78.534 23.125 ;
     RECT  2.415 23.125 78.534 23.279 ;
     RECT  73.656 23.279 78.534 23.357 ;
     RECT  2.415 23.279 72.897 23.459 ;
     RECT  2.415 23.459 29.862 23.549 ;
     RECT  2.415 23.549 27.81 23.597 ;
     RECT  73.764 23.357 78.534 23.701 ;
     RECT  73.764 23.701 78.57 23.791 ;
     RECT  30.78 23.459 72.897 23.819 ;
     RECT  73.764 23.791 78.606 23.863 ;
     RECT  31.392 23.819 72.897 23.927 ;
     RECT  73.764 23.863 78.642 23.971 ;
     RECT  28.584 23.549 29.862 24.241 ;
     RECT  79.56 24.205 79.578 24.241 ;
     RECT  2.415 23.597 27.702 24.331 ;
     RECT  28.584 24.241 29.97 24.331 ;
     RECT  2.415 24.331 29.97 24.475 ;
     RECT  37.224 23.927 72.897 24.511 ;
     RECT  73.764 23.971 78.75 24.511 ;
     RECT  2.415 24.475 30.618 24.601 ;
     RECT  31.392 23.927 36.342 24.601 ;
     RECT  2.415 24.601 36.342 24.629 ;
     RECT  3.42 24.629 36.342 24.701 ;
     RECT  9.648 24.701 36.342 24.709 ;
     RECT  37.224 24.511 78.75 24.709 ;
     RECT  9.648 24.709 78.75 24.781 ;
     RECT  79.56 24.241 79.722 24.781 ;
     RECT  9.648 24.781 79.722 25.007 ;
     RECT  2.415 24.629 2.697 25.483 ;
     RECT  3.42 24.701 8.838 25.483 ;
     RECT  9.684 25.007 79.722 25.519 ;
     RECT  2.415 25.483 8.838 25.709 ;
     RECT  5.688 25.709 8.838 25.745 ;
     RECT  5.796 25.745 8.838 25.781 ;
     RECT  6.264 25.781 8.838 25.861 ;
     RECT  9.684 25.519 79.758 25.861 ;
     RECT  6.264 25.861 79.758 26.249 ;
     RECT  2.415 25.709 4.95 26.527 ;
     RECT  6.264 26.249 79.722 26.527 ;
     RECT  5.94 26.527 79.722 26.671 ;
     RECT  2.415 26.527 5.022 26.761 ;
     RECT  5.76 26.671 79.722 26.761 ;
     RECT  2.415 26.761 79.722 26.825 ;
     RECT  2.415 26.825 51.606 26.897 ;
     RECT  9.54 26.897 51.606 27.059 ;
     RECT  80.928 26.347 80.946 27.211 ;
     RECT  80.928 27.211 81.486 27.307 ;
     RECT  52.344 26.825 79.722 27.595 ;
     RECT  80.892 27.307 81.486 27.635 ;
     RECT  9.54 27.059 51.57 27.707 ;
     RECT  9.54 27.707 51.462 27.779 ;
     RECT  52.344 27.595 79.794 27.877 ;
     RECT  80.892 27.635 80.946 27.883 ;
     RECT  2.415 26.897 8.802 27.913 ;
     RECT  9.54 27.779 51.426 27.913 ;
     RECT  52.2 27.877 79.794 27.979 ;
     RECT  80.856 27.883 80.946 27.979 ;
     RECT  81.972 27.679 81.99 28.109 ;
     RECT  52.2 27.979 80.946 28.211 ;
     RECT  80.892 28.211 80.946 28.247 ;
     RECT  52.2 28.211 79.83 28.517 ;
     RECT  2.415 27.913 51.426 28.525 ;
     RECT  52.2 28.517 79.722 28.525 ;
     RECT  2.415 28.525 79.722 28.687 ;
     RECT  2.412 28.687 79.722 28.733 ;
     RECT  81.468 28.795 81.486 29.299 ;
     RECT  81.468 29.299 81.522 29.323 ;
     RECT  80.856 29.323 81.522 29.363 ;
     RECT  80.928 29.363 81.522 29.549 ;
     RECT  81.756 29.803 81.99 29.867 ;
     RECT  80.928 29.549 80.946 30.283 ;
     RECT  2.415 28.733 79.722 30.451 ;
     RECT  80.892 30.283 80.946 30.475 ;
     RECT  2.376 30.451 79.722 30.571 ;
     RECT  80.82 30.475 80.946 30.571 ;
     RECT  81.756 29.867 81.882 30.667 ;
     RECT  2.376 30.571 80.946 30.713 ;
     RECT  80.82 30.713 80.946 30.859 ;
     RECT  81.756 30.667 81.99 30.859 ;
     RECT  2.376 30.713 79.758 31.225 ;
     RECT  80.82 30.859 81.99 31.559 ;
     RECT  2.304 31.225 79.758 31.915 ;
     RECT  80.82 31.559 81.918 31.915 ;
     RECT  2.304 31.915 81.918 31.955 ;
     RECT  2.376 31.955 81.918 32.495 ;
     RECT  2.376 32.495 80.946 32.873 ;
     RECT  2.376 32.873 80.874 33.053 ;
     RECT  81.9 32.495 81.918 33.341 ;
     RECT  2.415 33.053 80.874 33.611 ;
     RECT  2.415 33.611 80.37 33.845 ;
     RECT  2.415 33.845 79.65 34.187 ;
     RECT  2.415 34.187 79.038 34.219 ;
     RECT  2.34 34.219 79.038 34.349 ;
     RECT  3.42 34.349 79.038 34.889 ;
     RECT  2.415 34.349 2.697 35.131 ;
     RECT  3.42 34.889 78.894 35.131 ;
     RECT  2.415 35.131 78.894 35.195 ;
     RECT  2.415 35.195 78.822 36.355 ;
     RECT  2.415 36.355 79.038 36.931 ;
     RECT  2.415 36.931 79.362 37.049 ;
     RECT  2.415 37.049 78.786 37.967 ;
     RECT  73.728 37.967 78.786 38.165 ;
     RECT  73.8 38.165 78.786 38.281 ;
     RECT  73.8 38.281 78.93 38.543 ;
     RECT  73.8 38.543 78.75 38.579 ;
     RECT  2.415 37.967 72.954 39.091 ;
     RECT  73.8 38.579 78.714 39.091 ;
     RECT  2.415 39.091 78.714 39.865 ;
     RECT  2.415 39.865 78.822 40.199 ;
     RECT  2.415 40.199 78.75 40.981 ;
     RECT  2.415 40.981 78.894 41.521 ;
     RECT  2.415 41.521 78.966 41.747 ;
     RECT  2.415 41.747 78.93 42.179 ;
     RECT  74.916 42.179 78.93 42.449 ;
     RECT  74.988 42.449 78.93 42.485 ;
     RECT  74.988 42.485 78.858 43.291 ;
     RECT  74.988 43.291 78.93 43.411 ;
     RECT  2.415 42.179 74.034 43.501 ;
     RECT  74.988 43.411 79.002 43.501 ;
     RECT  74.916 43.501 79.002 43.528 ;
     RECT  2.415 43.501 74.142 43.531 ;
     RECT  74.88 43.528 79.002 43.531 ;
     RECT  2.415 43.531 79.002 43.871 ;
     RECT  2.415 43.871 78.966 45.301 ;
     RECT  2.415 45.301 79.002 45.427 ;
     RECT  2.376 45.427 79.002 45.491 ;
     RECT  2.376 45.491 35.766 45.581 ;
     RECT  36.54 45.491 79.002 45.841 ;
     RECT  2.376 45.581 35.73 46.111 ;
     RECT  2.016 46.111 35.73 46.363 ;
     RECT  36.54 45.841 79.254 46.363 ;
     RECT  2.016 46.363 79.254 46.885 ;
     RECT  1.944 46.885 79.254 51.359 ;
     RECT  1.944 51.359 39.438 51.773 ;
     RECT  40.215 51.359 79.254 51.899 ;
     RECT  40.215 51.899 78.858 52.169 ;
     RECT  32.796 51.773 39.438 52.411 ;
     RECT  40.215 52.169 78.606 52.411 ;
     RECT  1.944 51.773 32.058 52.555 ;
     RECT  32.796 52.411 78.606 52.555 ;
     RECT  1.944 52.555 78.606 52.825 ;
     RECT  1.692 52.825 78.606 52.979 ;
     RECT  27.324 52.979 37.422 53.015 ;
     RECT  1.692 52.979 25.902 53.021 ;
     RECT  79.56 52.987 79.578 53.024 ;
     RECT  38.16 52.979 78.606 53.131 ;
     RECT  38.16 53.131 78.786 53.249 ;
     RECT  28.476 53.015 37.422 53.309 ;
     RECT  44.712 53.249 46.206 53.309 ;
     RECT  47.304 53.249 53.514 53.321 ;
     RECT  28.476 53.309 37.386 53.357 ;
     RECT  38.232 53.249 41.31 53.357 ;
     RECT  44.712 53.309 46.098 53.357 ;
     RECT  28.512 53.357 37.386 53.393 ;
     RECT  42.336 53.249 43.722 53.393 ;
     RECT  28.512 53.393 37.134 53.429 ;
     RECT  44.712 53.357 45.954 53.429 ;
     RECT  47.664 53.321 53.478 53.429 ;
     RECT  28.656 53.429 37.134 53.519 ;
     RECT  38.268 53.357 41.31 53.519 ;
     RECT  42.516 53.393 43.722 53.519 ;
     RECT  44.712 53.429 44.73 53.519 ;
     RECT  45.615 53.429 45.954 53.519 ;
     RECT  47.664 53.429 51.297 53.519 ;
     RECT  52.416 53.429 53.478 53.519 ;
     RECT  54.72 53.249 78.39 53.519 ;
     RECT  1.944 53.021 25.686 53.549 ;
     RECT  29.052 53.519 29.97 53.555 ;
     RECT  32.076 53.519 33.642 53.555 ;
     RECT  38.268 53.519 38.286 53.555 ;
     RECT  39.492 53.519 40.914 53.555 ;
     RECT  42.516 53.519 42.786 53.555 ;
     RECT  47.664 53.519 49.626 53.555 ;
     RECT  30.852 53.519 30.87 53.591 ;
     RECT  32.076 53.555 33.138 53.591 ;
     RECT  42.768 53.555 42.786 53.591 ;
     RECT  45.615 53.519 45.918 53.591 ;
     RECT  47.664 53.555 48.762 53.591 ;
     RECT  49.608 53.555 49.626 53.591 ;
     RECT  32.4 53.591 33.138 53.597 ;
     RECT  35.892 53.519 36.63 53.597 ;
     RECT  52.524 53.519 53.226 53.597 ;
     RECT  54.72 53.519 69.57 53.597 ;
     RECT  40.215 53.555 40.878 53.627 ;
     RECT  32.4 53.597 32.418 53.663 ;
     RECT  43.704 53.519 43.722 53.699 ;
     RECT  54.72 53.597 55.422 53.699 ;
     RECT  56.196 53.597 69.57 53.699 ;
     RECT  29.052 53.555 29.697 53.747 ;
     RECT  34.815 53.519 35.097 53.747 ;
     RECT  40.215 53.627 40.497 53.747 ;
     RECT  45.615 53.591 45.897 53.747 ;
     RECT  51.015 53.519 51.297 53.747 ;
     RECT  70.452 53.519 78.297 53.747 ;
     RECT  27.324 53.015 27.522 53.789 ;
     RECT  29.052 53.747 29.505 53.789 ;
     RECT  35.892 53.597 36.594 53.789 ;
     RECT  47.808 53.591 48.762 53.789 ;
     RECT  53.028 53.597 53.226 53.789 ;
     RECT  57.96 53.699 69.57 53.789 ;
     RECT  70.452 53.747 78.105 53.789 ;
     RECT  1.944 53.549 25.65 53.825 ;
     RECT  27.324 53.789 27.342 53.825 ;
     RECT  35.892 53.789 36.162 53.825 ;
     RECT  47.808 53.789 47.826 53.825 ;
     RECT  56.196 53.699 57.15 53.825 ;
     RECT  70.452 53.789 70.722 53.825 ;
     RECT  1.944 53.825 24.105 53.861 ;
     RECT  57.96 53.789 69.426 53.861 ;
     RECT  24.876 53.825 25.65 53.897 ;
     RECT  71.568 53.789 76.662 53.897 ;
     RECT  1.944 53.861 3.114 53.905 ;
     RECT  53.208 53.789 53.226 53.933 ;
     RECT  56.415 53.825 57.15 53.933 ;
     RECT  58.14 53.861 68.958 53.933 ;
     RECT  71.568 53.897 75.726 53.933 ;
     RECT  76.572 53.897 76.662 53.933 ;
     RECT  25.56 53.897 25.578 53.969 ;
     RECT  36.144 53.825 36.162 53.969 ;
     RECT  54.72 53.699 54.738 53.969 ;
     RECT  71.568 53.933 75.33 53.969 ;
     RECT  76.644 53.933 76.662 53.969 ;
     RECT  1.692 53.905 3.114 53.981 ;
     RECT  3.852 53.861 24.105 53.981 ;
     RECT  58.248 53.933 68.958 53.981 ;
     RECT  72.108 53.969 75.33 53.981 ;
     RECT  2.415 53.981 2.79 54.017 ;
     RECT  17.46 53.981 24.105 54.017 ;
     RECT  29.415 53.789 29.505 54.017 ;
     RECT  34.815 53.747 34.905 54.017 ;
     RECT  40.215 53.747 40.305 54.017 ;
     RECT  45.615 53.747 45.705 54.017 ;
     RECT  51.015 53.747 51.105 54.017 ;
     RECT  56.415 53.933 57.114 54.017 ;
     RECT  78.015 53.789 78.105 54.017 ;
     RECT  4.536 53.981 10.638 54.029 ;
     RECT  11.376 53.981 15.39 54.029 ;
     RECT  16.128 53.981 16.686 54.029 ;
     RECT  17.46 54.017 23.922 54.029 ;
     RECT  68.616 53.981 68.958 54.029 ;
     RECT  17.532 54.029 23.922 54.077 ;
     RECT  2.556 54.017 2.79 54.125 ;
     RECT  5.112 54.029 10.638 54.125 ;
     RECT  12.132 54.029 12.15 54.125 ;
     RECT  13.104 54.029 15.39 54.125 ;
     RECT  17.532 54.077 20.826 54.125 ;
     RECT  21.636 54.077 23.742 54.125 ;
     RECT  59.652 53.981 63.054 54.125 ;
     RECT  63.972 53.981 67.806 54.125 ;
     RECT  72.576 53.981 73.386 54.125 ;
     RECT  57.096 54.017 57.114 54.131 ;
     RECT  60.84 54.125 60.858 54.131 ;
     RECT  2.556 54.125 2.754 54.173 ;
     RECT  13.104 54.125 13.59 54.173 ;
     RECT  18.576 54.125 19.602 54.173 ;
     RECT  61.776 54.125 63.054 54.173 ;
     RECT  65.952 54.125 67.554 54.173 ;
     RECT  72.576 54.125 72.954 54.173 ;
     RECT  2.736 54.173 2.754 54.221 ;
     RECT  13.572 54.173 13.59 54.221 ;
     RECT  18.756 54.173 19.602 54.221 ;
     RECT  62.064 54.173 63.054 54.221 ;
     RECT  65.952 54.173 67.374 54.221 ;
     RECT  72.936 54.173 72.954 54.221 ;
     RECT  7.344 54.125 10.638 54.269 ;
     RECT  22.932 54.125 22.95 54.701 ;
     RECT  5.112 54.125 5.706 54.749 ;
     RECT  64.188 54.125 64.926 54.749 ;
     RECT  8.424 54.269 10.638 54.797 ;
     RECT  7.344 54.269 7.362 55.181 ;
     RECT  9.324 54.797 10.638 55.277 ;
     RECT  18.936 54.221 19.602 55.277 ;
     RECT  5.688 54.749 5.706 55.325 ;
     RECT  8.424 54.797 8.442 55.325 ;
     RECT  10.548 55.277 10.566 55.325 ;
     RECT  14.436 54.125 15.39 55.325 ;
     RECT  16.668 54.029 16.686 55.325 ;
     RECT  58.248 53.981 58.626 55.325 ;
     RECT  62.352 54.221 63.054 55.325 ;
     RECT  64.188 54.749 64.206 55.325 ;
     RECT  65.952 54.221 66.654 55.325 ;
     RECT  9.324 55.277 9.63 55.373 ;
     RECT  58.248 55.325 58.266 55.373 ;
     RECT  9.324 55.373 9.342 55.421 ;
     RECT  66.636 55.325 66.654 55.805 ;
     RECT  13.608 55.675 13.626 55.901 ;
     RECT  2.556 55.915 2.574 56.045 ;
     RECT  11.376 54.029 11.394 56.045 ;
     RECT  14.724 55.325 14.742 56.045 ;
     RECT  18.936 55.277 18.954 56.045 ;
     RECT  62.352 55.325 62.37 56.045 ;
    LAYER M4 ;
     RECT  1.477 52.992 1.573 53.016 ;
     RECT  1.573 52.848 1.669 53.016 ;
     RECT  1.765 51.312 1.861 51.336 ;
     RECT  1.861 51.312 2.252 51.432 ;
     RECT  2.285 34.224 2.293 34.248 ;
     RECT  2.252 51.312 2.293 51.864 ;
     RECT  2.293 55.92 2.341 55.944 ;
     RECT  0.084 31.248 2.365 31.272 ;
     RECT  0.06 31.272 2.365 31.344 ;
     RECT  0.084 31.344 2.365 31.368 ;
     RECT  0.06 31.368 2.365 31.44 ;
     RECT  0.084 31.44 2.365 31.464 ;
     RECT  0.06 31.464 2.365 31.536 ;
     RECT  0.084 31.536 2.365 31.56 ;
     RECT  2.365 22.32 2.408 22.344 ;
     RECT  2.401 28.704 2.408 28.728 ;
     RECT  2.365 31.104 2.408 31.56 ;
     RECT  2.293 33.024 2.408 34.248 ;
     RECT  2.293 43.872 2.408 43.896 ;
     RECT  2.293 45.792 2.408 45.816 ;
     RECT  2.252 47.904 2.408 47.928 ;
     RECT  2.293 50.544 2.408 51.864 ;
     RECT  1.669 52.848 2.408 53.976 ;
     RECT  2.408 2.148 2.437 54.012 ;
     RECT  2.437 2.148 2.512 54.168 ;
     RECT  2.512 2.418 2.533 54.168 ;
     RECT  2.341 55.92 2.585 56.04 ;
     RECT  2.533 2.418 2.704 54.216 ;
     RECT  2.704 51.888 2.765 54.216 ;
     RECT  2.765 51.888 2.812 54.12 ;
     RECT  2.585 55.968 2.915 55.992 ;
     RECT  2.704 30.816 2.981 33.432 ;
     RECT  2.704 5.712 3.017 7.992 ;
     RECT  2.704 16.512 3.155 17.4 ;
     RECT  2.704 9.072 3.197 12.744 ;
     RECT  2.704 21.264 3.197 22.344 ;
     RECT  2.704 14.16 3.421 15.432 ;
     RECT  2.704 38.112 3.443 39.864 ;
     RECT  3.421 15.312 3.485 15.432 ;
     RECT  2.704 41.616 3.521 44.04 ;
     RECT  2.704 24.144 3.529 24.504 ;
     RECT  3.521 41.616 3.539 42.792 ;
     RECT  3.017 6.816 3.593 7.992 ;
     RECT  2.704 48.912 3.685 49.272 ;
     RECT  2.704 50.4 3.685 50.424 ;
     RECT  2.981 30.816 3.769 32.52 ;
     RECT  2.704 20.16 3.773 20.184 ;
     RECT  2.704 25.92 3.773 26.664 ;
     RECT  3.521 43.776 3.829 44.04 ;
     RECT  2.704 45.6 3.836 47.928 ;
     RECT  3.773 26.208 3.841 26.664 ;
     RECT  2.704 35.424 3.845 37.08 ;
     RECT  3.443 38.448 3.877 39.864 ;
     RECT  3.197 9.648 3.881 12.744 ;
     RECT  3.829 43.776 3.925 44.424 ;
     RECT  3.836 45.504 3.925 47.928 ;
     RECT  3.769 30.672 3.949 32.52 ;
     RECT  3.017 5.712 3.953 5.736 ;
     RECT  3.949 30.672 3.989 32.568 ;
     RECT  3.925 43.776 4.021 47.928 ;
     RECT  3.685 48.912 4.021 50.424 ;
     RECT  2.812 51.888 4.021 53.976 ;
     RECT  3.845 35.424 4.025 35.832 ;
     RECT  3.529 24.144 4.061 24.36 ;
     RECT  4.025 35.472 4.061 35.832 ;
     RECT  3.539 41.616 4.115 42.744 ;
     RECT  3.197 21.264 4.201 21.72 ;
     RECT  3.881 9.696 4.205 12.744 ;
     RECT  4.021 43.776 4.237 50.424 ;
     RECT  4.021 51.408 4.237 53.976 ;
     RECT  4.237 43.776 4.357 53.976 ;
     RECT  3.485 15.408 4.381 15.432 ;
     RECT  3.155 16.512 4.381 16.536 ;
     RECT  4.381 15.408 4.417 16.536 ;
     RECT  3.877 38.448 4.417 39.912 ;
     RECT  3.989 31.488 4.453 32.568 ;
     RECT  3.697 33.84 4.453 33.864 ;
     RECT  4.357 43.776 4.453 54.024 ;
     RECT  2.704 28.704 4.525 28.728 ;
     RECT  4.417 15.408 4.533 16.968 ;
     RECT  4.417 18.432 4.533 18.456 ;
     RECT  4.533 15.408 4.549 18.456 ;
     RECT  4.525 28.464 4.565 28.728 ;
     RECT  4.549 15.408 4.595 19.416 ;
     RECT  4.453 43.776 4.597 54.072 ;
     RECT  4.061 24.336 4.601 24.36 ;
     RECT  3.421 14.16 4.633 14.28 ;
     RECT  4.115 41.616 4.637 42.504 ;
     RECT  4.453 31.488 4.709 33.864 ;
     RECT  3.841 26.208 4.853 27.48 ;
     RECT  4.417 38.4 4.921 39.912 ;
     RECT  4.595 15.408 4.925 18.264 ;
     RECT  3.593 7.056 4.969 7.992 ;
     RECT  4.925 15.408 4.997 16.536 ;
     RECT  4.061 35.472 4.997 35.736 ;
     RECT  4.709 31.632 5.033 33.864 ;
     RECT  4.597 43.68 5.101 54.072 ;
     RECT  4.741 5.088 5.125 5.112 ;
     RECT  4.853 26.256 5.173 27.48 ;
     RECT  4.565 28.464 5.173 28.488 ;
     RECT  4.637 42.144 5.221 42.504 ;
     RECT  5.101 43.68 5.221 54.744 ;
     RECT  4.201 20.544 5.228 21.72 ;
     RECT  4.595 19.392 5.269 19.416 ;
     RECT  5.125 5.088 5.281 5.832 ;
     RECT  4.969 7.056 5.281 7.704 ;
     RECT  4.205 9.696 5.281 12.312 ;
     RECT  4.633 13.632 5.281 14.28 ;
     RECT  4.997 15.984 5.315 16.536 ;
     RECT  5.228 20.544 5.315 22.152 ;
     RECT  5.173 26.256 5.315 28.488 ;
     RECT  4.309 23.328 5.317 23.352 ;
     RECT  5.315 26.736 5.411 28.488 ;
     RECT  5.221 42.144 5.459 54.744 ;
     RECT  3.845 37.056 5.509 37.08 ;
     RECT  4.921 38.4 5.509 39.96 ;
     RECT  5.315 20.544 5.633 21.72 ;
     RECT  4.997 35.568 5.641 35.736 ;
     RECT  5.612 3.696 5.653 3.72 ;
     RECT  5.281 5.088 5.653 7.704 ;
     RECT  5.269 19.392 5.677 19.512 ;
     RECT  5.365 29.664 5.677 29.688 ;
     RECT  5.459 42.144 5.677 54.12 ;
     RECT  5.653 3.696 5.699 7.704 ;
     RECT  5.317 22.704 5.701 23.352 ;
     RECT  5.641 35.568 5.749 35.928 ;
     RECT  5.699 3.984 5.753 7.704 ;
     RECT  5.033 31.632 5.789 33.096 ;
     RECT  5.753 5.088 5.825 7.704 ;
     RECT  5.677 55.296 5.843 55.32 ;
     RECT  5.749 35.568 5.965 35.976 ;
     RECT  5.677 19.344 6.001 19.512 ;
     RECT  5.633 20.496 6.001 21.72 ;
     RECT  5.789 33.024 6.001 33.096 ;
     RECT  5.411 27.456 6.005 28.488 ;
     RECT  5.677 41.664 6.005 54.12 ;
     RECT  4.925 17.664 6.073 18.264 ;
     RECT  6.001 19.344 6.073 21.72 ;
     RECT  6.001 33.024 6.073 33.384 ;
     RECT  5.281 13.584 6.109 14.28 ;
     RECT  5.281 9.36 6.217 12.312 ;
     RECT  6.109 13.584 6.217 14.472 ;
     RECT  6.005 41.664 6.253 52.44 ;
     RECT  6.253 41.616 6.275 52.44 ;
     RECT  6.005 27.552 6.293 28.488 ;
     RECT  6.005 53.472 6.293 54.12 ;
     RECT  6.073 17.664 6.325 21.72 ;
     RECT  5.965 35.328 6.332 35.976 ;
     RECT  5.509 37.056 6.332 39.96 ;
     RECT  5.825 5.328 6.361 7.704 ;
     RECT  5.315 15.984 6.361 16.296 ;
     RECT  6.325 17.472 6.361 21.72 ;
     RECT  6.275 41.616 6.365 50.184 ;
     RECT  6.293 27.936 6.437 28.488 ;
     RECT  6.275 51.36 6.509 52.44 ;
     RECT  5.701 22.704 6.577 24.024 ;
     RECT  6.509 51.408 6.653 52.44 ;
     RECT  6.361 15.984 6.685 21.72 ;
     RECT  6.577 22.704 6.685 24.936 ;
     RECT  6.073 33.024 6.721 34.152 ;
     RECT  5.789 31.632 6.757 31.944 ;
     RECT  6.721 33.024 6.761 34.2 ;
     RECT  6.332 35.328 6.761 39.96 ;
     RECT  6.361 5.328 6.829 7.944 ;
     RECT  6.217 9.312 6.829 14.472 ;
     RECT  6.761 33.36 6.86 34.2 ;
     RECT  6.761 35.328 6.86 35.976 ;
     RECT  6.685 15.984 6.901 24.936 ;
     RECT  6.541 26.208 6.901 26.232 ;
     RECT  6.901 15.984 6.937 26.232 ;
     RECT  6.829 5.328 7.081 14.472 ;
     RECT  6.937 15.456 7.081 26.232 ;
     RECT  6.761 37.056 7.081 39.96 ;
     RECT  7.081 37.056 7.261 40.392 ;
     RECT  6.365 41.616 7.261 42.216 ;
     RECT  5.753 3.984 7.333 4.104 ;
     RECT  6.757 31.44 7.369 31.944 ;
     RECT  6.653 52.416 7.405 52.44 ;
     RECT  6.293 53.568 7.405 54.12 ;
     RECT  7.081 5.328 7.441 26.232 ;
     RECT  7.333 55.152 7.475 55.176 ;
     RECT  6.365 43.344 7.549 50.184 ;
     RECT  6.653 51.408 7.549 51.432 ;
     RECT  7.333 3.984 7.585 4.248 ;
     RECT  7.441 5.28 7.585 26.232 ;
     RECT  7.549 43.344 7.621 51.432 ;
     RECT  7.405 52.416 7.621 54.12 ;
     RECT  7.621 43.344 7.693 54.12 ;
     RECT  7.585 3.984 7.808 26.232 ;
     RECT  6.437 28.176 7.808 28.488 ;
     RECT  5.677 29.664 7.808 30.456 ;
     RECT  7.369 31.44 7.808 32.328 ;
     RECT  6.86 33.36 7.808 35.976 ;
     RECT  7.261 37.056 7.808 42.216 ;
     RECT  7.693 43.344 7.808 54.264 ;
     RECT  7.808 2.148 7.912 54.264 ;
     RECT  7.912 2.418 8.104 54.264 ;
     RECT  8.104 23.136 8.237 24.504 ;
     RECT  8.237 23.808 8.273 24.504 ;
     RECT  8.104 29.28 8.291 38.76 ;
     RECT  8.291 29.28 8.309 30.456 ;
     RECT  8.104 40.368 8.597 50.136 ;
     RECT  8.104 27.6 8.669 27.624 ;
     RECT  8.104 51.12 8.737 54.264 ;
     RECT  8.413 55.296 8.737 55.32 ;
     RECT  8.104 3.888 8.921 17.496 ;
     RECT  8.104 18.72 9.097 19.512 ;
     RECT  8.104 21.024 9.097 21.816 ;
     RECT  8.921 3.984 9.313 17.496 ;
     RECT  9.097 18.72 9.313 21.816 ;
     RECT  8.737 51.12 9.313 55.32 ;
     RECT  8.291 31.44 9.389 38.76 ;
     RECT  8.104 25.776 9.421 26.616 ;
     RECT  9.389 31.632 9.461 38.76 ;
     RECT  9.313 51.12 9.491 55.416 ;
     RECT  9.313 3.984 9.493 21.816 ;
     RECT  8.273 23.808 9.493 24.456 ;
     RECT  8.597 40.368 9.493 49.848 ;
     RECT  9.493 3.984 9.497 21.96 ;
     RECT  9.493 23.52 9.637 24.456 ;
     RECT  9.421 25.776 9.637 26.76 ;
     RECT  9.491 51.12 9.637 53.592 ;
     RECT  9.497 16.512 9.641 21.96 ;
     RECT  9.641 18.816 9.709 21.96 ;
     RECT  9.709 18.816 9.781 22.104 ;
     RECT  9.641 16.512 9.785 17.832 ;
     RECT  9.637 50.928 9.785 53.592 ;
     RECT  8.309 29.28 9.877 30.36 ;
     RECT  9.493 40.08 9.965 49.848 ;
     RECT  9.637 23.52 10.001 26.76 ;
     RECT  9.877 29.04 10.069 30.36 ;
     RECT  9.461 31.632 10.115 35.352 ;
     RECT  10.115 31.632 10.156 34.776 ;
     RECT  10.001 23.904 10.217 26.76 ;
     RECT  9.781 18.816 10.253 22.536 ;
     RECT  10.069 29.04 10.429 30.456 ;
     RECT  10.156 31.632 10.469 34.488 ;
     RECT  9.965 40.176 10.501 49.848 ;
     RECT  9.785 50.928 10.501 51.912 ;
     RECT  9.491 54.72 10.501 55.416 ;
     RECT  10.501 54.672 10.585 55.416 ;
     RECT  9.497 3.984 10.645 15.48 ;
     RECT  9.785 16.512 10.645 17.496 ;
     RECT  10.585 55.248 10.649 55.416 ;
     RECT  10.217 24.624 10.717 26.76 ;
     RECT  10.429 28.416 10.717 30.456 ;
     RECT  10.649 55.296 10.739 55.416 ;
     RECT  9.785 52.896 10.748 53.592 ;
     RECT  10.645 3.984 10.753 17.496 ;
     RECT  10.253 21.024 10.753 22.536 ;
     RECT  10.753 3.408 10.789 17.496 ;
     RECT  10.253 18.816 10.825 19.848 ;
     RECT  10.748 52.896 10.825 53.688 ;
     RECT  10.753 21.024 10.835 22.872 ;
     RECT  10.789 3.408 10.837 17.544 ;
     RECT  10.825 18.768 10.837 19.848 ;
     RECT  10.501 40.176 10.933 51.912 ;
     RECT  10.933 40.032 10.973 51.912 ;
     RECT  10.837 3.408 10.981 19.848 ;
     RECT  10.835 21.648 11.005 22.872 ;
     RECT  9.461 36.912 11.113 38.76 ;
     RECT  10.973 40.032 11.113 49.608 ;
     RECT  10.973 50.736 11.149 51.912 ;
     RECT  10.825 52.896 11.149 53.976 ;
     RECT  10.981 2.832 11.225 19.848 ;
     RECT  10.717 24.624 11.293 30.456 ;
     RECT  10.469 31.632 11.293 32.328 ;
     RECT  11.293 24.624 11.405 32.328 ;
     RECT  10.885 56.016 11.405 56.04 ;
     RECT  11.005 21.648 11.509 22.968 ;
     RECT  11.149 50.736 11.548 53.976 ;
     RECT  11.548 50.736 11.585 54.024 ;
     RECT  11.405 29.184 11.621 32.328 ;
     RECT  11.225 2.88 11.725 19.848 ;
     RECT  11.621 29.28 11.761 32.328 ;
     RECT  10.469 33.312 11.761 34.488 ;
     RECT  11.113 36.912 11.869 49.608 ;
     RECT  11.509 21.648 11.989 23.352 ;
     RECT  11.405 24.624 11.989 27.72 ;
     RECT  11.725 2.88 12.013 20.136 ;
     RECT  12.013 2.88 12.049 20.232 ;
     RECT  11.585 51.168 12.121 54.024 ;
     RECT  12.049 2.88 12.229 20.424 ;
     RECT  11.989 21.648 12.229 27.72 ;
     RECT  11.869 36.864 12.553 49.608 ;
     RECT  12.121 51.168 12.553 54.12 ;
     RECT  11.113 35.568 12.841 35.592 ;
     RECT  12.229 2.88 12.877 27.72 ;
     RECT  11.761 29.28 12.913 34.488 ;
     RECT  12.841 35.568 12.913 35.784 ;
     RECT  12.913 29.28 12.949 35.784 ;
     RECT  12.949 29.28 12.985 35.832 ;
     RECT  12.553 36.864 12.985 54.12 ;
     RECT  12.985 29.28 13.052 54.12 ;
     RECT  13.052 29.28 13.093 54.168 ;
     RECT  12.877 2.88 13.208 27.912 ;
     RECT  13.093 29.088 13.208 54.168 ;
     RECT  13.34 1.104 13.427 1.128 ;
     RECT  13.208 2.148 13.477 54.168 ;
     RECT  13.477 1.728 13.504 54.216 ;
     RECT  13.504 29.808 13.529 52.488 ;
     RECT  13.189 55.776 13.573 55.8 ;
     RECT  13.573 55.776 13.597 55.896 ;
     RECT  13.504 53.568 13.601 54.216 ;
     RECT  13.529 36.912 13.637 52.488 ;
     RECT  13.597 55.68 13.66 55.896 ;
     RECT  13.529 29.808 13.681 35.928 ;
     RECT  13.66 55.68 13.681 55.704 ;
     RECT  13.669 0.096 13.752 0.12 ;
     RECT  13.681 29.808 13.907 35.16 ;
     RECT  13.752 0.096 13.925 0.264 ;
     RECT  13.504 3.408 14.177 28.44 ;
     RECT  14.177 3.408 14.243 26.232 ;
     RECT  13.637 36.912 14.249 51.912 ;
     RECT  13.925 0.096 14.393 0.12 ;
     RECT  13.907 29.808 14.533 34.824 ;
     RECT  13.601 53.568 14.617 54.12 ;
     RECT  14.249 50.688 14.713 51.912 ;
     RECT  14.425 55.296 14.713 55.32 ;
     RECT  13.504 1.728 14.725 2.28 ;
     RECT  14.725 1.728 14.732 2.328 ;
     RECT  14.243 3.408 14.732 25.992 ;
     RECT  14.732 1.728 15.049 25.992 ;
     RECT  14.713 55.296 15.059 56.04 ;
     RECT  14.177 27.456 15.073 28.44 ;
     RECT  14.533 29.616 15.073 34.824 ;
     RECT  14.749 35.904 15.073 35.928 ;
     RECT  15.073 29.616 15.077 35.928 ;
     RECT  15.049 3.408 15.253 25.992 ;
     RECT  15.049 1.728 15.257 2.328 ;
     RECT  15.073 27.456 15.257 28.488 ;
     RECT  15.253 3.408 15.293 26.04 ;
     RECT  15.293 24.096 15.325 26.04 ;
     RECT  15.257 27.648 15.397 28.488 ;
     RECT  15.077 29.616 15.397 35.736 ;
     RECT  15.059 55.296 15.443 55.32 ;
     RECT  15.257 1.728 15.473 2.28 ;
     RECT  14.249 36.912 15.493 49.56 ;
     RECT  14.713 50.688 15.493 52.2 ;
     RECT  15.293 3.408 15.581 23.112 ;
     RECT  15.581 3.408 15.689 21.192 ;
     RECT  15.493 36.912 15.793 52.2 ;
     RECT  15.325 24.096 15.829 26.088 ;
     RECT  15.473 1.728 15.833 1.752 ;
     RECT  14.617 53.568 16.069 53.976 ;
     RECT  16.069 53.568 16.157 54.024 ;
     RECT  15.793 36.912 16.357 52.488 ;
     RECT  16.157 53.568 16.357 53.976 ;
     RECT  15.397 27.648 16.369 35.736 ;
     RECT  16.369 27.6 16.441 35.736 ;
     RECT  16.357 36.912 16.441 53.976 ;
     RECT  15.689 3.408 16.481 20.76 ;
     RECT  16.481 3.648 16.517 20.76 ;
     RECT  15.581 22.656 16.549 23.112 ;
     RECT  15.829 24.096 16.549 26.424 ;
     RECT  16.441 27.6 16.589 53.976 ;
     RECT  16.517 20.112 16.801 20.76 ;
     RECT  16.549 22.656 16.972 26.424 ;
     RECT  16.657 55.296 17.267 55.32 ;
     RECT  16.589 51.408 17.317 53.976 ;
     RECT  16.801 20.112 17.449 21.144 ;
     RECT  17.317 51.408 17.521 54.072 ;
     RECT  16.589 27.6 17.66 50.328 ;
     RECT  17.521 51.408 17.66 54.12 ;
     RECT  16.972 25.584 17.756 26.424 ;
     RECT  17.66 27.6 17.756 54.12 ;
     RECT  16.517 3.648 17.773 18.84 ;
     RECT  17.773 3.408 17.809 18.84 ;
     RECT  17.449 20.112 17.809 21.672 ;
     RECT  16.972 22.656 17.989 24.552 ;
     RECT  17.756 25.584 17.989 54.12 ;
     RECT  17.809 3.408 18.169 21.672 ;
     RECT  17.989 22.656 18.169 54.12 ;
     RECT  18.169 3.408 18.565 54.12 ;
     RECT  18.565 3.408 18.608 54.168 ;
     RECT  18.608 2.148 18.648 54.168 ;
     RECT  18.648 2.148 18.712 54.216 ;
     RECT  18.712 2.418 18.785 54.216 ;
     RECT  18.785 2.418 18.904 54.168 ;
     RECT  18.904 53.568 18.937 54.168 ;
     RECT  18.925 56.016 19.009 56.04 ;
     RECT  18.904 20.592 19.043 24.312 ;
     RECT  18.904 25.536 19.139 52.536 ;
     RECT  19.043 22.56 19.217 24.312 ;
     RECT  19.217 22.8 19.475 24.312 ;
     RECT  18.904 2.64 19.505 19.32 ;
     RECT  19.475 22.8 19.613 24.12 ;
     RECT  19.139 25.632 20.225 52.536 ;
     RECT  18.937 53.568 20.243 54.12 ;
     RECT  19.613 22.8 20.365 23.928 ;
     RECT  20.365 22.608 20.405 23.928 ;
     RECT  19.249 55.248 20.435 55.272 ;
     RECT  20.405 22.608 20.585 23.16 ;
     RECT  20.585 22.608 20.657 22.872 ;
     RECT  19.043 20.592 20.729 21.144 ;
     RECT  19.505 2.64 21.049 19.128 ;
     RECT  20.729 20.592 21.049 20.616 ;
     RECT  21.049 2.64 21.233 20.616 ;
     RECT  20.225 25.632 21.373 52.488 ;
     RECT  20.243 53.664 21.373 54.12 ;
     RECT  20.657 22.608 21.409 22.632 ;
     RECT  21.121 24.24 21.445 24.264 ;
     RECT  21.445 24.24 21.589 24.648 ;
     RECT  21.409 22.464 21.685 22.632 ;
     RECT  21.589 23.76 21.685 24.648 ;
     RECT  21.233 2.736 21.949 20.616 ;
     RECT  21.685 22.176 21.949 24.648 ;
     RECT  21.949 2.736 22.021 24.648 ;
     RECT  21.373 25.632 22.021 54.12 ;
     RECT  22.021 2.736 22.405 54.12 ;
     RECT  22.405 2.544 22.601 54.12 ;
     RECT  22.601 24.624 22.789 54.12 ;
     RECT  22.789 24.624 22.961 54.696 ;
     RECT  22.961 24.624 23.753 54.12 ;
     RECT  23.753 24.624 23.933 54.072 ;
     RECT  22.601 2.544 23.965 23.592 ;
     RECT  23.965 2.304 24.008 23.592 ;
     RECT  23.933 24.624 24.008 54.012 ;
     RECT  24.008 2.148 24.112 54.012 ;
     RECT  24.112 2.208 24.304 53.742 ;
     RECT  24.304 24.48 25.333 53.544 ;
     RECT  25.333 24.48 25.369 53.592 ;
     RECT  25.369 24.384 25.405 53.592 ;
     RECT  24.304 22.224 25.441 23.112 ;
     RECT  25.441 22.176 25.477 23.112 ;
     RECT  25.405 24.192 25.477 53.592 ;
     RECT  25.477 22.176 25.481 53.592 ;
     RECT  25.481 52.704 25.553 53.592 ;
     RECT  24.304 2.208 25.585 21.096 ;
     RECT  25.481 22.176 25.585 51.528 ;
     RECT  25.553 52.704 25.697 53.544 ;
     RECT  25.697 52.704 25.769 53.4 ;
     RECT  25.769 52.992 25.913 53.4 ;
     RECT  25.585 2.208 25.985 51.528 ;
     RECT  25.985 2.208 26.093 51.096 ;
     RECT  26.093 24.624 26.201 51.096 ;
     RECT  26.201 24.624 26.813 50.808 ;
     RECT  26.813 24.72 27.101 50.808 ;
     RECT  26.093 2.208 27.281 23.592 ;
     RECT  25.913 53.376 27.313 53.4 ;
     RECT  27.281 2.544 27.821 23.592 ;
     RECT  27.313 53.328 27.853 53.4 ;
     RECT  27.101 24.72 28.321 50.712 ;
     RECT  28.321 24.336 28.429 50.712 ;
     RECT  28.429 24.336 28.465 50.808 ;
     RECT  27.853 52.848 28.681 53.4 ;
     RECT  27.821 2.544 28.897 23.112 ;
     RECT  28.897 2.496 29.113 23.112 ;
     RECT  29.113 2.496 29.408 23.352 ;
     RECT  28.465 24.336 29.408 51 ;
     RECT  28.681 52.8 29.408 53.4 ;
     RECT  29.408 2.148 29.512 54.012 ;
     RECT  29.512 2.418 29.704 53.742 ;
     RECT  29.704 2.496 30.413 23.352 ;
     RECT  30.413 2.544 31.333 23.352 ;
     RECT  29.704 24.624 31.333 53.4 ;
     RECT  31.333 2.544 31.529 53.4 ;
     RECT  31.529 2.544 31.571 50.664 ;
     RECT  31.571 2.544 31.777 22.872 ;
     RECT  31.571 23.856 31.925 50.664 ;
     RECT  31.529 51.744 32.065 53.4 ;
     RECT  32.065 51.744 32.317 53.496 ;
     RECT  32.317 51.744 32.389 53.544 ;
     RECT  31.777 2.496 32.569 22.872 ;
     RECT  31.925 46.56 32.653 50.664 ;
     RECT  32.389 51.744 32.825 53.592 ;
     RECT  32.569 2.352 33.005 22.872 ;
     RECT  33.005 2.544 33.011 22.872 ;
     RECT  33.011 21.456 33.109 22.872 ;
     RECT  31.925 23.856 33.109 45.576 ;
     RECT  32.825 51.888 33.149 53.592 ;
     RECT  33.109 21.456 33.221 45.576 ;
     RECT  33.149 51.888 33.653 53.544 ;
     RECT  32.653 46.56 33.865 48.84 ;
     RECT  32.653 49.824 33.865 50.664 ;
     RECT  33.653 51.888 33.865 53.4 ;
     RECT  33.221 23.856 34.333 45.528 ;
     RECT  33.011 2.544 34.549 20.424 ;
     RECT  33.221 21.456 34.549 22.872 ;
     RECT  34.333 23.856 34.693 45.576 ;
     RECT  33.865 46.56 34.693 53.4 ;
     RECT  34.549 2.544 34.808 22.872 ;
     RECT  34.693 23.856 34.808 53.4 ;
     RECT  34.808 2.148 34.912 54.012 ;
     RECT  34.912 2.418 35.104 53.742 ;
     RECT  35.104 2.544 35.273 51.96 ;
     RECT  35.273 21.456 35.417 51.96 ;
     RECT  35.417 21.504 35.561 51.96 ;
     RECT  35.561 50.112 35.597 51.96 ;
     RECT  35.561 21.504 35.705 49.08 ;
     RECT  35.597 50.352 36.097 51.96 ;
     RECT  35.104 53.328 36.097 53.592 ;
     RECT  36.097 50.352 36.353 53.592 ;
     RECT  36.353 50.352 36.605 51.768 ;
     RECT  36.353 52.896 36.641 53.592 ;
     RECT  36.641 52.896 36.713 53.4 ;
     RECT  35.273 2.544 36.749 20.424 ;
     RECT  35.705 21.552 36.925 49.08 ;
     RECT  36.925 21.552 37.033 49.272 ;
     RECT  36.749 2.544 37.045 20.328 ;
     RECT  36.605 51.744 37.073 51.768 ;
     RECT  37.045 2.256 37.109 20.328 ;
     RECT  37.033 21.456 37.213 49.272 ;
     RECT  36.605 50.352 37.213 50.376 ;
     RECT  37.109 2.256 37.433 20.232 ;
     RECT  36.713 52.992 37.933 53.4 ;
     RECT  37.433 2.352 38.077 20.232 ;
     RECT  37.213 21.456 38.077 50.376 ;
     RECT  37.933 52.464 38.293 53.4 ;
     RECT  38.077 2.352 38.365 50.376 ;
     RECT  38.293 51.648 38.365 53.4 ;
     RECT  38.365 2.352 38.405 53.4 ;
     RECT  38.405 2.544 38.477 53.4 ;
     RECT  38.477 2.592 39.589 53.4 ;
     RECT  39.589 2.544 40.208 53.4 ;
     RECT  40.208 2.148 40.312 54.012 ;
     RECT  40.312 2.418 40.504 53.742 ;
     RECT  40.504 2.592 41.821 53.4 ;
     RECT  41.821 2.496 42.113 53.4 ;
     RECT  42.113 2.592 42.467 53.4 ;
     RECT  42.467 2.832 43.445 53.4 ;
     RECT  43.445 2.832 43.557 19.224 ;
     RECT  43.557 2.688 44.488 19.224 ;
     RECT  43.445 20.208 44.488 53.4 ;
     RECT  44.488 2.688 45.608 53.4 ;
     RECT  45.608 2.148 45.712 54.012 ;
     RECT  45.712 2.418 45.904 53.742 ;
     RECT  45.904 2.832 47.185 53.4 ;
     RECT  47.185 2.304 48.449 53.4 ;
     RECT  48.449 2.448 48.773 53.4 ;
     RECT  48.773 2.688 49.781 53.4 ;
     RECT  49.781 3.072 51.008 53.4 ;
     RECT  51.008 2.148 51.112 54.012 ;
     RECT  51.112 2.418 51.304 53.742 ;
     RECT  51.304 2.88 52.441 53.112 ;
     RECT  52.441 2.496 52.513 53.112 ;
     RECT  52.513 2.496 52.739 53.592 ;
     RECT  52.739 2.496 52.765 20.712 ;
     RECT  52.739 22.032 53.121 53.592 ;
     RECT  52.765 2.304 53.417 20.712 ;
     RECT  53.417 2.496 54.281 20.712 ;
     RECT  53.121 22.032 54.425 53.112 ;
     RECT  54.281 3.408 54.529 20.712 ;
     RECT  54.529 3.408 54.781 21.048 ;
     RECT  54.425 22.032 54.781 35.448 ;
     RECT  54.425 36.864 54.853 53.112 ;
     RECT  54.853 36.864 55.429 53.592 ;
     RECT  54.781 3.408 55.609 35.448 ;
     RECT  55.429 36.528 55.609 53.592 ;
     RECT  55.609 3.408 56.408 53.592 ;
     RECT  56.408 2.148 56.512 54.012 ;
     RECT  56.512 2.418 56.704 53.742 ;
     RECT  56.704 3.6 57.593 53.64 ;
     RECT  57.593 3.6 57.985 53.448 ;
     RECT  57.841 1.152 58.093 1.176 ;
     RECT  57.985 3.552 58.133 53.448 ;
     RECT  58.133 37.536 58.205 53.448 ;
     RECT  58.133 3.552 58.273 36.456 ;
     RECT  58.093 1.152 58.405 1.224 ;
     RECT  58.057 2.304 58.405 2.328 ;
     RECT  58.405 1.152 58.46 2.328 ;
     RECT  58.46 1.104 58.525 2.328 ;
     RECT  58.237 55.344 58.597 55.368 ;
     RECT  58.525 1.008 58.633 2.328 ;
     RECT  58.273 3.36 58.637 36.456 ;
     RECT  58.205 37.776 58.709 53.448 ;
     RECT  58.633 0.24 58.777 2.328 ;
     RECT  58.637 3.36 58.777 18.84 ;
     RECT  58.777 0.24 58.861 18.84 ;
     RECT  58.709 37.92 59.029 53.448 ;
     RECT  58.861 3.6 59.033 18.84 ;
     RECT  58.637 20.112 59.069 36.456 ;
     RECT  58.861 0.24 59.123 2.328 ;
     RECT  58.597 55.296 59.123 55.368 ;
     RECT  59.123 0.24 59.245 0.648 ;
     RECT  59.123 55.344 59.315 55.368 ;
     RECT  59.069 20.112 59.321 36.408 ;
     RECT  59.029 37.92 59.641 53.976 ;
     RECT  59.245 0.096 59.645 0.648 ;
     RECT  59.321 20.112 59.749 36.312 ;
     RECT  59.749 19.92 59.891 36.312 ;
     RECT  59.645 0.576 59.969 0.648 ;
     RECT  59.641 37.92 60.289 54.12 ;
     RECT  59.891 20.112 60.365 36.312 ;
     RECT  60.365 20.304 60.421 36.312 ;
     RECT  60.289 37.824 60.421 54.12 ;
     RECT  59.969 0.624 60.437 0.648 ;
     RECT  60.421 20.304 60.437 54.12 ;
     RECT  60.437 20.4 60.467 54.12 ;
     RECT  60.467 37.92 60.581 54.12 ;
     RECT  59.123 1.728 60.613 2.328 ;
     RECT  60.581 38.016 60.617 54.12 ;
     RECT  60.613 1.152 60.685 2.328 ;
     RECT  59.033 3.6 60.685 18.504 ;
     RECT  60.685 1.152 60.697 18.504 ;
     RECT  60.697 1.728 60.721 18.504 ;
     RECT  60.721 1.728 61.553 18.792 ;
     RECT  60.617 38.496 61.724 54.12 ;
     RECT  61.724 38.496 61.729 54.168 ;
     RECT  61.553 1.776 61.808 18.792 ;
     RECT  60.467 20.4 61.808 36.936 ;
     RECT  61.729 38.16 61.808 54.168 ;
     RECT  61.808 1.776 61.984 54.168 ;
     RECT  61.984 1.776 62.099 54.216 ;
     RECT  62.099 1.776 62.345 54.12 ;
     RECT  61.573 56.016 62.381 56.04 ;
     RECT  62.345 33.264 62.705 54.12 ;
     RECT  62.345 1.776 63.245 32.28 ;
     RECT  63.245 2.736 63.281 32.28 ;
     RECT  63.281 28.992 63.565 32.28 ;
     RECT  62.705 33.264 63.565 33.672 ;
     RECT  63.281 2.736 63.569 27.72 ;
     RECT  63.569 2.736 63.785 22.344 ;
     RECT  63.565 28.992 63.889 33.672 ;
     RECT  62.705 34.704 63.889 54.12 ;
     RECT  63.785 2.784 64.073 22.344 ;
     RECT  63.889 28.992 64.145 54.12 ;
     RECT  64.145 28.992 64.289 32.328 ;
     RECT  64.289 29.184 64.505 32.328 ;
     RECT  63.025 55.296 64.595 55.32 ;
     RECT  64.505 29.184 64.613 32.232 ;
     RECT  64.073 3.408 64.645 22.344 ;
     RECT  63.569 23.328 64.645 27.72 ;
     RECT  64.145 33.36 64.897 54.12 ;
     RECT  64.897 33.36 64.901 54.744 ;
     RECT  64.901 37.968 65.075 54.744 ;
     RECT  64.901 33.36 65.113 36.984 ;
     RECT  65.113 33.264 65.189 36.984 ;
     RECT  65.189 33.264 65.333 36.888 ;
     RECT  65.333 34.464 65.585 36.888 ;
     RECT  64.645 3.408 65.725 27.72 ;
     RECT  64.613 29.232 65.833 32.232 ;
     RECT  65.725 2.88 66.017 27.72 ;
     RECT  65.833 29.088 66.049 32.232 ;
     RECT  65.941 55.296 66.227 55.32 ;
     RECT  66.049 28.992 66.265 32.232 ;
     RECT  65.585 34.608 66.445 36.888 ;
     RECT  65.075 37.968 66.445 54.12 ;
     RECT  66.017 2.88 66.553 19.32 ;
     RECT  65.333 33.264 66.709 33.432 ;
     RECT  66.445 34.608 66.709 54.12 ;
     RECT  66.265 28.704 66.733 32.232 ;
     RECT  66.709 33.264 66.733 54.12 ;
     RECT  66.625 55.776 66.995 55.8 ;
     RECT  66.733 28.704 67.141 54.12 ;
     RECT  66.553 2.784 67.201 19.32 ;
     RECT  66.017 20.688 67.201 27.72 ;
     RECT  67.201 2.784 67.208 27.72 ;
     RECT  67.141 28.704 67.208 54.168 ;
     RECT  67.208 2.148 67.227 54.168 ;
     RECT  67.227 2.148 67.312 54.216 ;
     RECT  67.312 2.418 67.385 54.216 ;
     RECT  67.385 2.418 67.504 54.168 ;
     RECT  67.504 27.696 67.609 54.168 ;
     RECT  67.609 27.696 67.817 54.12 ;
     RECT  67.817 27.696 67.853 54.024 ;
     RECT  67.504 3.648 67.997 26.424 ;
     RECT  67.997 19.008 68.069 26.424 ;
     RECT  67.853 27.696 68.213 41.592 ;
     RECT  68.069 21.648 68.645 26.424 ;
     RECT  68.213 34.752 68.681 41.592 ;
     RECT  67.853 42.576 68.681 54.024 ;
     RECT  68.645 21.696 68.885 26.424 ;
     RECT  68.213 27.696 68.885 33.384 ;
     RECT  68.681 42.768 68.969 54.024 ;
     RECT  68.885 21.696 69.041 33.384 ;
     RECT  68.969 42.768 69.041 53.64 ;
     RECT  67.997 3.648 69.061 18.024 ;
     RECT  68.069 19.008 69.061 19.992 ;
     RECT  69.041 21.696 69.293 29.304 ;
     RECT  69.061 3.648 69.325 19.992 ;
     RECT  68.681 34.752 69.443 41.208 ;
     RECT  69.041 30.528 69.505 33.384 ;
     RECT  69.443 34.752 69.541 41.064 ;
     RECT  69.541 34.656 69.653 41.064 ;
     RECT  69.505 30.528 69.781 33.576 ;
     RECT  69.325 3.648 69.793 20.664 ;
     RECT  69.293 21.696 69.793 22.056 ;
     RECT  69.793 3.648 69.833 22.056 ;
     RECT  69.653 34.8 69.833 41.064 ;
     RECT  69.781 30.528 69.868 33.816 ;
     RECT  69.293 23.136 70.081 29.304 ;
     RECT  69.868 30.528 70.081 33.576 ;
     RECT  69.041 43.248 70.081 53.64 ;
     RECT  69.833 19.008 70.193 22.056 ;
     RECT  69.833 3.648 70.229 17.976 ;
     RECT  70.193 19.008 70.265 20.088 ;
     RECT  70.193 21.12 70.333 22.056 ;
     RECT  70.081 23.136 70.333 33.576 ;
     RECT  70.333 21.12 70.451 33.576 ;
     RECT  70.081 42.192 70.481 53.64 ;
     RECT  70.229 3.648 70.697 17.928 ;
     RECT  70.481 42.192 70.697 48.936 ;
     RECT  70.697 4.8 70.877 17.928 ;
     RECT  70.877 5.04 70.993 17.928 ;
     RECT  70.451 21.12 71.197 22.056 ;
     RECT  70.993 15.312 71.221 17.928 ;
     RECT  70.451 23.04 71.309 33.576 ;
     RECT  71.309 23.04 71.417 29.304 ;
     RECT  70.265 19.008 71.485 19.944 ;
     RECT  71.197 21.072 71.485 22.056 ;
     RECT  71.309 30.336 71.489 33.576 ;
     RECT  71.485 19.008 71.593 22.056 ;
     RECT  71.417 23.04 71.593 26.424 ;
     RECT  70.481 50.304 71.845 53.592 ;
     RECT  71.845 50.112 71.996 53.592 ;
     RECT  69.833 34.8 72.037 41.016 ;
     RECT  71.996 49.92 72.092 53.592 ;
     RECT  70.697 42.432 72.133 48.936 ;
     RECT  72.092 49.92 72.133 53.976 ;
     RECT  72.037 34.752 72.229 41.016 ;
     RECT  71.221 15.312 72.241 18.024 ;
     RECT  71.593 19.008 72.241 26.424 ;
     RECT  72.229 34.752 72.313 41.112 ;
     RECT  72.133 42.432 72.313 53.976 ;
     RECT  70.993 5.04 72.349 14.28 ;
     RECT  72.241 15.312 72.349 26.424 ;
     RECT  72.349 5.04 72.457 26.424 ;
     RECT  71.417 27.6 72.457 29.304 ;
     RECT  72.313 34.752 72.565 53.976 ;
     RECT  72.457 5.04 72.601 29.304 ;
     RECT  70.697 3.648 72.608 3.72 ;
     RECT  72.601 5.04 72.608 29.64 ;
     RECT  71.489 30.672 72.608 33.576 ;
     RECT  72.565 34.752 72.608 54.168 ;
     RECT  72.608 2.148 72.712 54.168 ;
     RECT  72.712 2.418 72.901 54.168 ;
     RECT  72.901 2.418 72.904 54.216 ;
     RECT  72.904 42.192 72.988 54.216 ;
     RECT  72.373 55.968 72.995 55.992 ;
     RECT  72.904 25.728 73.001 32.616 ;
     RECT  72.988 42.192 73.441 54.12 ;
     RECT  72.904 5.04 73.523 20.376 ;
     RECT  73.523 5.04 73.541 17.832 ;
     RECT  72.904 34.752 73.852 40.584 ;
     RECT  72.904 22.032 73.859 23.544 ;
     RECT  73.523 19.056 73.897 20.376 ;
     RECT  73.897 19.056 74.077 20.52 ;
     RECT  73.859 22.032 74.077 23.352 ;
     RECT  73.541 15.312 74.099 17.832 ;
     RECT  73.852 34.752 74.153 36.264 ;
     RECT  73.001 30.48 74.185 32.28 ;
     RECT  72.904 33.6 74.185 33.624 ;
     RECT  73.541 5.04 74.297 13.992 ;
     RECT  74.185 30.48 74.329 33.624 ;
     RECT  74.153 34.752 74.329 36.072 ;
     RECT  74.297 6.24 74.477 13.992 ;
     RECT  74.099 15.312 74.477 15.336 ;
     RECT  74.077 19.056 74.513 23.352 ;
     RECT  74.099 16.512 74.545 17.832 ;
     RECT  74.513 19.056 74.545 23.208 ;
     RECT  73.001 25.728 74.725 29.448 ;
     RECT  74.329 30.48 74.725 36.072 ;
     RECT  74.725 25.728 75.053 36.072 ;
     RECT  73.852 37.68 75.053 40.584 ;
     RECT  74.545 16.512 75.085 23.208 ;
     RECT  75.053 25.728 75.085 33.624 ;
     RECT  75.085 25.68 75.125 33.624 ;
     RECT  75.053 34.608 75.157 36.072 ;
     RECT  75.053 37.68 75.157 39.288 ;
     RECT  75.085 15.936 75.251 23.208 ;
     RECT  73.441 42.192 75.341 53.976 ;
     RECT  75.341 42.192 75.589 53.64 ;
     RECT  75.157 34.608 75.629 39.288 ;
     RECT  75.053 40.368 75.733 40.584 ;
     RECT  75.589 41.568 75.733 53.64 ;
     RECT  74.477 6.24 75.809 13.128 ;
     RECT  75.629 37.488 75.809 39.288 ;
     RECT  75.629 34.608 75.953 36.072 ;
     RECT  75.809 7.44 75.98 13.128 ;
     RECT  75.251 15.984 75.989 23.208 ;
     RECT  75.733 40.368 76.025 53.64 ;
     RECT  75.98 7.44 76.067 13.656 ;
     RECT  75.697 24.24 76.093 24.456 ;
     RECT  75.125 25.68 76.093 33.24 ;
     RECT  75.989 15.984 76.133 19.368 ;
     RECT  75.953 34.608 76.163 35.976 ;
     RECT  76.025 40.368 76.169 51.528 ;
     RECT  75.989 20.976 76.205 23.208 ;
     RECT  76.025 52.992 76.259 53.64 ;
     RECT  75.809 37.632 76.273 39.288 ;
     RECT  76.169 40.368 76.273 46.392 ;
     RECT  76.273 37.632 76.421 46.392 ;
     RECT  76.067 7.44 76.457 13.128 ;
     RECT  76.093 24.24 76.489 33.24 ;
     RECT  76.163 34.608 76.489 35.784 ;
     RECT  74.617 14.64 76.529 14.664 ;
     RECT  76.489 24.24 76.529 35.784 ;
     RECT  76.421 37.728 76.637 46.392 ;
     RECT  74.297 5.04 76.673 5.064 ;
     RECT  76.205 20.976 76.745 22.776 ;
     RECT  76.637 37.728 76.853 44.472 ;
     RECT  76.745 20.976 76.889 22.68 ;
     RECT  76.853 37.728 76.961 42.024 ;
     RECT  76.169 47.424 76.993 51.528 ;
     RECT  75.809 6.24 77.209 6.264 ;
     RECT  76.457 7.44 77.209 7.752 ;
     RECT  76.529 24.432 77.353 35.784 ;
     RECT  77.353 24.432 77.389 35.928 ;
     RECT  76.637 45.552 77.677 46.392 ;
     RECT  76.993 47.424 77.677 51.864 ;
     RECT  77.677 45.552 77.701 51.864 ;
     RECT  77.209 6.24 77.713 7.752 ;
     RECT  76.457 8.832 77.713 13.128 ;
     RECT  76.853 43.056 77.749 44.472 ;
     RECT  77.701 45.456 77.749 51.864 ;
     RECT  76.133 16.8 77.893 18.6 ;
     RECT  77.893 16.8 77.965 19.56 ;
     RECT  76.889 20.976 77.965 22.488 ;
     RECT  76.961 37.728 77.965 40.872 ;
     RECT  72.904 3.648 78.008 3.72 ;
     RECT  77.713 6.24 78.008 13.128 ;
     RECT  77.137 14.736 78.008 15.048 ;
     RECT  77.965 16.8 78.008 22.488 ;
     RECT  77.389 24.432 78.008 36.072 ;
     RECT  77.965 37.68 78.008 40.872 ;
     RECT  76.961 42 78.008 42.024 ;
     RECT  77.749 43.056 78.008 51.864 ;
     RECT  76.259 52.992 78.008 53.064 ;
     RECT  78.008 2.148 78.112 54.012 ;
     RECT  78.112 2.418 78.304 53.742 ;
     RECT  78.304 7.392 78.365 7.992 ;
     RECT  78.304 24.432 78.365 39.768 ;
     RECT  78.304 17.376 78.419 22.488 ;
     RECT  78.365 37.056 78.419 39.768 ;
     RECT  78.419 17.376 78.509 22.104 ;
     RECT  78.365 24.432 78.509 35.016 ;
     RECT  78.304 40.848 78.509 40.872 ;
     RECT  78.509 17.376 78.545 17.832 ;
     RECT  78.509 24.672 78.545 35.016 ;
     RECT  78.419 37.056 78.545 38.088 ;
     RECT  78.419 39.744 78.545 39.768 ;
     RECT  78.304 45.168 78.563 50.424 ;
     RECT  78.365 7.392 78.581 7.416 ;
     RECT  78.304 11.424 78.581 11.784 ;
     RECT  78.509 18.816 78.581 22.056 ;
     RECT  78.545 37.68 78.581 38.088 ;
     RECT  78.563 45.168 78.611 46.728 ;
     RECT  78.563 47.76 78.611 50.424 ;
     RECT  78.304 12.816 78.617 12.84 ;
     RECT  78.581 21.936 78.617 21.96 ;
     RECT  78.545 25.008 78.617 35.016 ;
     RECT  78.365 36.048 78.617 36.072 ;
     RECT  78.304 42 78.617 43.656 ;
     RECT  78.581 11.424 78.653 11.448 ;
     RECT  78.617 34.08 78.653 34.68 ;
     RECT  78.581 18.816 78.659 20.424 ;
     RECT  78.581 37.68 78.689 37.704 ;
     RECT  78.611 48.48 78.689 50.424 ;
     RECT  78.545 17.808 78.797 17.832 ;
     RECT  78.653 34.656 78.797 34.68 ;
     RECT  78.617 43.104 78.797 43.656 ;
     RECT  78.611 45.408 78.803 46.728 ;
     RECT  78.304 9.552 78.833 9.576 ;
     RECT  78.304 14.736 78.833 15.576 ;
     RECT  78.659 18.816 78.833 20.376 ;
     RECT  78.689 49.776 78.833 50.424 ;
     RECT  78.617 42 78.864 42.12 ;
     RECT  78.833 20.304 78.869 20.376 ;
     RECT  78.617 25.008 78.869 33.096 ;
     RECT  78.864 42.096 78.899 42.12 ;
     RECT  78.797 43.104 78.899 43.32 ;
     RECT  78.803 45.504 78.899 46.728 ;
     RECT  78.689 48.768 78.905 48.792 ;
     RECT  78.899 45.936 78.94 46.728 ;
     RECT  78.833 18.816 78.941 18.936 ;
     RECT  78.869 20.304 78.941 20.328 ;
     RECT  78.899 43.296 78.941 43.32 ;
     RECT  78.94 46.032 78.941 46.728 ;
     RECT  78.941 18.816 78.977 18.84 ;
     RECT  78.833 49.776 79.013 49.8 ;
     RECT  78.869 25.008 79.121 32.808 ;
     RECT  79.121 25.008 79.532 32.568 ;
     RECT  78.304 52.992 79.589 53.016 ;
     RECT  79.532 24.24 79.619 32.568 ;
     RECT  79.619 24.48 79.667 32.568 ;
     RECT  79.667 25.056 79.733 32.568 ;
     RECT  79.733 25.056 79.763 31.944 ;
     RECT  79.763 25.056 79.811 25.08 ;
     RECT  79.763 26.064 80.845 31.944 ;
     RECT  80.845 26.064 81.996 26.088 ;
     RECT  80.845 26.088 82.044 26.16 ;
     RECT  80.845 26.16 81.996 26.184 ;
     RECT  80.845 26.184 82.044 26.256 ;
     RECT  80.845 26.256 81.996 26.28 ;
     RECT  80.845 26.28 82.044 26.352 ;
     RECT  80.845 26.352 81.996 26.376 ;
     RECT  80.845 26.376 82.044 26.448 ;
     RECT  80.845 26.448 81.996 26.472 ;
     RECT  80.845 26.472 82.044 26.544 ;
     RECT  80.845 26.544 81.996 26.568 ;
     RECT  80.845 26.568 82.044 26.64 ;
     RECT  80.845 26.64 81.996 26.664 ;
     RECT  80.845 26.664 82.044 26.736 ;
     RECT  80.845 26.736 81.996 26.76 ;
     RECT  80.845 26.76 82.044 26.832 ;
     RECT  80.845 26.832 81.996 26.856 ;
     RECT  80.845 26.856 82.044 26.928 ;
     RECT  80.845 26.928 81.996 26.952 ;
     RECT  80.845 26.952 82.044 27.024 ;
     RECT  80.845 27.024 81.996 27.048 ;
     RECT  80.845 27.048 82.044 27.12 ;
     RECT  80.845 27.12 81.996 27.144 ;
     RECT  80.845 27.144 82.044 27.216 ;
     RECT  80.845 27.216 81.996 27.24 ;
     RECT  80.845 27.24 82.044 27.312 ;
     RECT  80.845 27.312 81.996 27.336 ;
     RECT  80.845 27.336 82.044 27.408 ;
     RECT  80.845 27.408 81.996 27.432 ;
     RECT  80.845 27.432 82.044 27.504 ;
     RECT  80.845 27.504 81.996 27.528 ;
     RECT  80.845 27.528 82.044 27.6 ;
     RECT  80.845 27.6 81.996 27.624 ;
     RECT  80.845 27.624 82.044 27.696 ;
     RECT  80.845 27.696 81.996 27.72 ;
     RECT  80.845 27.72 82.044 27.792 ;
     RECT  80.845 27.792 81.996 27.816 ;
     RECT  80.845 27.816 82.044 27.888 ;
     RECT  80.845 27.888 81.996 27.912 ;
     RECT  80.845 27.912 82.044 27.984 ;
     RECT  80.845 27.984 81.996 28.008 ;
     RECT  80.845 28.008 82.044 28.08 ;
     RECT  80.845 28.08 81.996 28.104 ;
     RECT  80.845 28.104 82.044 28.176 ;
     RECT  80.845 28.176 81.996 28.2 ;
     RECT  80.845 28.2 82.044 29.136 ;
     RECT  80.845 29.136 81.996 29.16 ;
     RECT  80.845 29.16 82.044 29.232 ;
     RECT  80.845 29.232 81.996 29.256 ;
     RECT  80.845 29.256 82.044 29.328 ;
     RECT  80.845 29.328 81.996 29.352 ;
     RECT  80.845 29.352 82.044 29.424 ;
     RECT  80.845 29.424 81.996 29.448 ;
     RECT  80.845 29.448 82.044 29.52 ;
     RECT  80.845 29.52 81.996 29.544 ;
     RECT  80.845 29.544 82.044 29.616 ;
     RECT  80.845 29.616 81.996 29.64 ;
     RECT  80.845 29.64 82.044 29.712 ;
     RECT  80.845 29.712 81.996 29.736 ;
     RECT  80.845 29.736 82.044 29.808 ;
     RECT  80.845 29.808 81.996 29.832 ;
     RECT  80.845 29.832 82.044 29.904 ;
     RECT  80.845 29.904 81.996 29.928 ;
     RECT  80.845 29.928 82.044 30 ;
     RECT  80.845 30 81.996 30.024 ;
     RECT  80.845 30.024 82.044 30.096 ;
     RECT  80.845 30.096 81.996 30.12 ;
     RECT  80.845 30.12 82.044 30.192 ;
     RECT  80.845 30.192 81.996 30.216 ;
     RECT  80.845 30.216 82.044 30.288 ;
     RECT  80.845 30.288 81.996 30.312 ;
     RECT  80.845 30.312 82.044 30.384 ;
     RECT  80.845 30.384 81.996 30.408 ;
     RECT  80.845 30.408 82.044 30.48 ;
     RECT  80.845 30.48 81.996 30.504 ;
     RECT  80.845 30.504 82.044 30.576 ;
     RECT  80.845 30.576 81.996 30.6 ;
     RECT  80.845 30.6 82.044 30.672 ;
     RECT  80.845 30.672 81.996 30.696 ;
     RECT  80.845 30.696 82.044 30.768 ;
     RECT  80.845 30.768 81.996 30.792 ;
     RECT  80.845 30.792 82.044 30.864 ;
     RECT  80.845 30.864 81.996 30.888 ;
     RECT  80.845 30.888 82.044 30.96 ;
     RECT  80.845 30.96 81.996 30.984 ;
     RECT  80.845 30.984 82.044 31.056 ;
     RECT  80.845 31.056 81.996 31.08 ;
     RECT  80.845 31.08 82.044 31.152 ;
     RECT  80.845 31.152 81.996 31.176 ;
     RECT  80.845 31.176 82.044 31.248 ;
     RECT  80.845 31.248 81.996 31.272 ;
     RECT  80.845 31.272 82.044 31.344 ;
     RECT  80.845 31.344 81.996 31.368 ;
     RECT  80.845 31.368 82.044 31.44 ;
     RECT  80.845 31.44 81.996 31.464 ;
     RECT  80.845 31.464 82.044 31.536 ;
     RECT  80.845 31.536 81.996 31.56 ;
     RECT  80.845 31.56 82.044 31.632 ;
     RECT  80.845 31.632 81.996 31.656 ;
     RECT  80.845 31.656 82.044 31.728 ;
     RECT  80.845 31.728 81.996 31.752 ;
     RECT  80.845 31.752 82.044 31.824 ;
     RECT  80.845 31.824 81.996 31.848 ;
     RECT  80.845 31.848 82.044 31.92 ;
     RECT  80.845 31.92 81.996 31.944 ;
     RECT  80.845 31.944 82.044 32.016 ;
     RECT  80.845 32.016 81.996 32.04 ;
     RECT  80.845 32.04 82.044 32.112 ;
     RECT  80.845 32.112 81.996 32.136 ;
    LAYER M5 ;
     RECT  13.416 0.016 13.488 0.084 ;
     RECT  13.512 0.016 13.584 0.084 ;
     RECT  13.608 0.016 13.68 0.084 ;
     RECT  13.704 0.016 13.776 0.084 ;
     RECT  13.8 0.016 13.872 0.084 ;
     RECT  13.896 0.016 13.968 0.084 ;
     RECT  13.992 0.016 14.064 0.084 ;
     RECT  14.088 0.016 14.16 0.084 ;
     RECT  14.184 0.016 14.256 0.084 ;
     RECT  14.28 0.016 14.352 0.084 ;
     RECT  14.376 0.016 14.448 0.084 ;
     RECT  14.472 0.016 14.544 0.084 ;
     RECT  14.568 0.016 14.64 0.084 ;
     RECT  14.664 0.016 14.736 0.084 ;
     RECT  14.76 0.016 14.832 0.084 ;
     RECT  14.856 0.016 14.928 0.084 ;
     RECT  14.952 0.016 15.024 0.084 ;
     RECT  15.048 0.016 15.12 0.084 ;
     RECT  15.144 0.016 15.216 0.084 ;
     RECT  15.24 0.016 15.312 0.084 ;
     RECT  15.336 0.016 15.408 0.084 ;
     RECT  13.392 0.084 15.432 1.139 ;
     RECT  13.488 1.139 15.432 1.763 ;
     RECT  13.488 1.763 15.336 2.137 ;
     RECT  58.344 0.016 58.416 0.084 ;
     RECT  58.44 0.016 58.512 0.084 ;
     RECT  58.536 0.016 58.608 0.084 ;
     RECT  58.632 0.016 58.704 0.084 ;
     RECT  58.728 0.016 58.8 0.084 ;
     RECT  58.824 0.016 58.896 0.084 ;
     RECT  58.92 0.016 58.992 0.084 ;
     RECT  59.016 0.016 59.088 0.084 ;
     RECT  59.112 0.016 59.184 0.084 ;
     RECT  59.208 0.016 59.28 0.084 ;
     RECT  59.304 0.016 59.376 0.084 ;
     RECT  59.4 0.016 59.472 0.084 ;
     RECT  59.496 0.016 59.568 0.084 ;
     RECT  59.592 0.016 59.664 0.084 ;
     RECT  59.688 0.016 59.76 0.084 ;
     RECT  59.784 0.016 59.856 0.084 ;
     RECT  59.88 0.016 59.952 0.084 ;
     RECT  59.976 0.016 60.048 0.084 ;
     RECT  60.072 0.016 60.144 0.084 ;
     RECT  60.168 0.016 60.24 0.084 ;
     RECT  60.264 0.016 60.336 0.084 ;
     RECT  60.36 0.016 60.432 0.084 ;
     RECT  60.456 0.016 60.528 0.084 ;
     RECT  60.552 0.016 60.624 0.084 ;
     RECT  60.648 0.016 60.72 0.084 ;
     RECT  60.744 0.016 60.816 0.084 ;
     RECT  60.84 0.016 60.912 0.084 ;
     RECT  60.936 0.016 61.008 0.084 ;
     RECT  61.032 0.016 61.104 0.084 ;
     RECT  61.128 0.016 61.2 0.084 ;
     RECT  61.224 0.016 61.296 0.084 ;
     RECT  58.32 0.084 61.32 2.137 ;
     RECT  2.4 2.137 2.52 2.151 ;
     RECT  7.8 2.137 7.92 2.151 ;
     RECT  18.6 2.137 18.72 2.151 ;
     RECT  24 2.137 24.12 2.151 ;
     RECT  29.4 2.137 29.52 2.151 ;
     RECT  34.8 2.137 34.92 2.151 ;
     RECT  40.2 2.137 40.32 2.151 ;
     RECT  45.6 2.137 45.72 2.151 ;
     RECT  51 2.137 51.12 2.151 ;
     RECT  56.4 2.137 56.52 2.151 ;
     RECT  58.32 2.137 61.92 2.151 ;
     RECT  67.2 2.137 67.32 2.151 ;
     RECT  72.6 2.137 72.72 2.151 ;
     RECT  78 2.137 78.12 2.151 ;
     RECT  24 2.151 24.312 2.197 ;
     RECT  13.2 2.137 15.336 2.291 ;
     RECT  13.2 2.291 15.24 2.339 ;
     RECT  58.32 2.151 62.112 2.339 ;
     RECT  29.4 2.151 29.712 2.533 ;
     RECT  29.28 2.533 29.712 2.581 ;
     RECT  29.28 2.581 29.832 2.629 ;
     RECT  29.28 2.629 30.264 2.677 ;
     RECT  21.072 2.629 21.096 2.725 ;
     RECT  22.416 2.533 22.44 2.821 ;
     RECT  37.056 2.245 37.08 2.821 ;
     RECT  42.432 2.581 42.456 2.867 ;
     RECT  58.704 2.339 58.824 2.915 ;
     RECT  22.416 2.821 22.632 2.963 ;
     RECT  43.584 2.677 43.608 3.061 ;
     RECT  29.04 2.677 30.264 3.109 ;
     RECT  40.2 2.151 40.512 3.157 ;
     RECT  42.72 3.061 43.608 3.347 ;
     RECT  61.296 2.339 62.112 3.349 ;
     RECT  10.992 2.821 11.016 3.397 ;
     RECT  10.848 3.397 11.016 3.443 ;
     RECT  20.496 2.725 21.096 3.443 ;
     RECT  21.072 3.443 21.096 3.635 ;
     RECT  24 2.197 24.6 3.637 ;
     RECT  25.632 3.397 26.568 3.637 ;
     RECT  56.4 2.151 56.712 3.829 ;
     RECT  13.2 2.339 15 3.925 ;
     RECT  45.6 2.151 45.912 3.925 ;
     RECT  39.456 3.157 40.512 3.971 ;
     RECT  53.04 3.445 53.064 4.019 ;
     RECT  58.704 2.915 58.728 4.019 ;
     RECT  10.848 3.443 10.872 4.067 ;
     RECT  37.056 2.821 38.04 4.067 ;
     RECT  13.2 3.925 15.048 4.117 ;
     RECT  13.104 4.117 15.048 4.261 ;
     RECT  13.104 4.261 15.384 4.309 ;
     RECT  24 3.637 26.568 4.309 ;
     RECT  51 2.151 51.312 4.501 ;
     RECT  45.072 3.925 45.912 4.549 ;
     RECT  5.664 3.685 5.688 4.595 ;
     RECT  51 4.501 51.816 4.645 ;
     RECT  45.024 4.549 45.912 4.691 ;
     RECT  45.072 4.691 45.912 4.693 ;
     RECT  22.608 2.963 22.632 4.739 ;
     RECT  42.72 3.347 42.744 4.885 ;
     RECT  42.24 4.885 42.744 4.931 ;
     RECT  43.776 3.925 43.8 4.931 ;
     RECT  37.584 4.067 38.04 4.933 ;
     RECT  72.6 2.151 72.912 5.077 ;
     RECT  55.776 3.829 56.712 5.171 ;
     RECT  20.544 5.077 20.568 5.173 ;
     RECT  12.816 4.309 15.384 5.219 ;
     RECT  37.584 4.933 38.088 5.221 ;
     RECT  50.064 4.645 51.816 5.269 ;
     RECT  47.952 3.829 47.976 5.365 ;
     RECT  49.008 5.269 49.032 5.365 ;
     RECT  60.24 2.339 60.264 5.365 ;
     RECT  61.296 3.349 62.952 5.365 ;
     RECT  64.608 5.269 64.728 5.411 ;
     RECT  47.952 5.365 49.032 5.507 ;
     RECT  24 4.309 26.952 5.509 ;
     RECT  28.368 3.109 30.264 5.509 ;
     RECT  40.2 3.971 40.512 5.509 ;
     RECT  49.008 5.507 49.032 5.555 ;
     RECT  50.064 5.269 52.536 5.555 ;
     RECT  47.952 5.507 47.976 5.603 ;
     RECT  53.808 5.125 53.832 5.699 ;
     RECT  64.608 5.411 64.632 5.699 ;
     RECT  13.2 5.219 15.384 5.747 ;
     RECT  40.2 5.509 41.112 5.747 ;
     RECT  45.072 4.693 46.2 5.747 ;
     RECT  60.24 5.365 62.952 5.747 ;
     RECT  24 5.509 30.264 5.795 ;
     RECT  5.136 5.077 5.16 5.843 ;
     RECT  15.36 5.747 15.384 5.843 ;
     RECT  45.072 5.747 46.152 5.845 ;
     RECT  34.8 2.151 35.112 5.893 ;
     RECT  44.592 5.845 46.152 5.989 ;
     RECT  72.6 5.077 73.416 6.083 ;
     RECT  60.96 5.747 62.952 6.179 ;
     RECT  56.4 5.171 56.712 6.229 ;
     RECT  67.2 2.151 67.512 6.229 ;
     RECT  37.056 5.221 38.088 6.275 ;
     RECT  18.6 2.151 18.912 6.277 ;
     RECT  44.496 5.989 46.152 6.373 ;
     RECT  50.064 5.555 52.104 6.421 ;
     RECT  27.792 5.795 30.264 6.563 ;
     RECT  70.656 3.973 70.68 6.563 ;
     RECT  34.8 5.893 35.208 6.565 ;
     RECT  49.632 6.421 52.104 6.611 ;
     RECT  7.8 2.151 8.112 6.661 ;
     RECT  32.448 4.741 32.472 6.661 ;
     RECT  44.4 6.373 46.152 6.757 ;
     RECT  55.488 6.229 56.712 6.757 ;
     RECT  40.2 5.747 40.512 6.805 ;
     RECT  42.24 4.931 42.264 6.805 ;
     RECT  49.632 6.611 51.864 6.805 ;
     RECT  78 2.151 78.312 6.805 ;
     RECT  16.512 6.133 16.536 6.853 ;
     RECT  31.296 6.421 31.32 6.853 ;
     RECT  16.368 6.853 16.536 6.901 ;
     RECT  59.664 6.133 59.688 6.947 ;
     RECT  32.448 6.661 33.672 6.949 ;
     RECT  34.8 6.565 35.544 6.949 ;
     RECT  54.816 6.757 56.712 6.995 ;
     RECT  6.48 5.317 6.504 7.043 ;
     RECT  27.792 6.563 29.832 7.043 ;
     RECT  39.168 6.901 39.192 7.045 ;
     RECT  40.2 6.805 42.264 7.045 ;
     RECT  16.08 6.901 16.536 7.141 ;
     RECT  39.168 7.045 42.264 7.283 ;
     RECT  15.648 7.141 16.536 7.331 ;
     RECT  24 5.795 26.568 7.333 ;
     RECT  27.792 7.043 29.712 7.333 ;
     RECT  72.6 6.083 73.32 7.333 ;
     RECT  17.664 6.277 18.912 7.379 ;
     RECT  31.296 6.853 31.368 7.427 ;
     RECT  49.584 6.805 51.864 7.427 ;
     RECT  16.272 7.331 16.536 7.619 ;
     RECT  77.472 6.805 78.312 7.619 ;
     RECT  66.384 6.229 67.512 7.861 ;
     RECT  16.272 7.619 16.392 7.907 ;
     RECT  20.448 5.173 20.568 7.957 ;
     RECT  37.92 6.275 38.088 7.957 ;
     RECT  49.584 7.427 51.816 8.005 ;
     RECT  54.816 6.995 55.176 8.101 ;
     RECT  31.296 7.427 31.32 8.147 ;
     RECT  32.448 6.949 35.544 8.149 ;
     RECT  36.768 7.957 36.792 8.149 ;
     RECT  20.448 7.957 21.096 8.197 ;
     RECT  56.4 6.995 56.712 8.197 ;
     RECT  32.448 8.149 36.792 8.245 ;
     RECT  32.448 8.245 36.888 8.291 ;
     RECT  72.6 7.333 73.368 8.291 ;
     RECT  20.448 8.197 21.24 8.339 ;
     RECT  60.432 8.197 60.456 8.339 ;
     RECT  56.4 8.197 57.144 8.341 ;
     RECT  36.864 8.291 36.888 8.389 ;
     RECT  37.92 7.957 38.184 8.389 ;
     RECT  44.16 6.757 46.152 8.389 ;
     RECT  36.864 8.389 38.184 8.435 ;
     RECT  48.72 8.005 51.816 8.435 ;
     RECT  32.448 8.291 35.544 8.483 ;
     RECT  36.96 8.435 38.184 8.531 ;
     RECT  44.16 8.389 46.392 8.531 ;
     RECT  32.448 8.483 35.352 8.579 ;
     RECT  34.8 8.579 35.352 8.627 ;
     RECT  49.008 8.435 51.816 8.629 ;
     RECT  53.04 8.245 53.064 8.629 ;
     RECT  40.032 7.283 42.264 8.677 ;
     RECT  7.8 6.661 8.232 8.723 ;
     RECT  10.464 8.341 10.488 8.723 ;
     RECT  34.8 8.627 35.304 8.723 ;
     RECT  49.008 8.629 53.064 8.771 ;
     RECT  40.032 8.677 42.456 8.773 ;
     RECT  50.208 8.771 53.064 8.915 ;
     RECT  50.208 8.915 51.816 8.963 ;
     RECT  65.712 7.861 67.512 9.011 ;
     RECT  13.2 5.747 14.232 9.013 ;
     RECT  56.4 8.341 57.672 9.013 ;
     RECT  61.68 6.179 62.952 9.013 ;
     RECT  13.2 9.013 14.856 9.059 ;
     RECT  37.728 8.531 38.184 9.107 ;
     RECT  37.728 9.107 38.04 9.155 ;
     RECT  54.72 8.101 55.176 9.155 ;
     RECT  52.944 8.915 53.064 9.157 ;
     RECT  66.384 9.011 67.512 9.205 ;
     RECT  7.8 8.723 8.112 9.253 ;
     RECT  18.6 7.379 18.912 9.253 ;
     RECT  52.944 9.157 53.256 9.299 ;
     RECT  13.2 9.059 13.512 9.349 ;
     RECT  18.6 9.253 19.032 9.349 ;
     RECT  56.304 9.013 57.672 9.349 ;
     RECT  58.992 8.389 59.016 9.349 ;
     RECT  54.72 9.155 54.744 9.491 ;
     RECT  52.944 9.299 53.16 9.539 ;
     RECT  32.448 8.579 33.432 9.541 ;
     RECT  37.728 9.155 37.992 9.541 ;
     RECT  24 7.333 29.712 9.589 ;
     RECT  2.4 2.151 2.712 9.637 ;
     RECT  34.8 8.723 35.256 9.685 ;
     RECT  32.016 9.541 33.432 9.781 ;
     RECT  40.032 8.773 43.032 9.781 ;
     RECT  20.448 8.339 21.144 9.877 ;
     RECT  34.8 9.685 35.4 9.973 ;
     RECT  36.864 9.541 37.992 10.019 ;
     RECT  24 9.589 29.976 10.067 ;
     RECT  56.304 9.349 59.016 10.067 ;
     RECT  20.448 9.877 21.24 10.115 ;
     RECT  49.008 9.973 49.032 10.115 ;
     RECT  20.448 10.115 21.144 10.117 ;
     RECT  36.864 10.019 37.752 10.163 ;
     RECT  20.112 10.117 21.144 10.259 ;
     RECT  44.16 8.531 46.2 10.261 ;
     RECT  31.392 9.781 33.432 10.451 ;
     RECT  56.4 10.067 59.016 10.499 ;
     RECT  16.368 10.117 16.392 10.501 ;
     RECT  39.264 9.781 43.032 10.549 ;
     RECT  44.16 10.261 46.728 10.549 ;
     RECT  61.056 9.013 62.952 10.549 ;
     RECT  56.4 10.499 57.24 10.739 ;
     RECT  24 10.067 26.568 10.741 ;
     RECT  66.384 9.205 68.424 10.741 ;
     RECT  27.648 10.067 29.976 10.883 ;
     RECT  58.464 10.499 59.016 10.931 ;
     RECT  65.232 9.397 65.256 10.931 ;
     RECT  56.4 10.739 56.856 10.979 ;
     RECT  4.896 7.957 4.92 10.981 ;
     RECT  2.4 9.637 3.672 11.027 ;
     RECT  13.056 9.349 13.512 11.027 ;
     RECT  39.264 10.549 46.728 11.075 ;
     RECT  66.384 10.741 68.808 11.123 ;
     RECT  60.384 10.549 62.952 11.171 ;
     RECT  42.432 11.075 46.728 11.173 ;
     RECT  32.016 10.451 33.432 11.269 ;
     RECT  23.712 10.741 26.568 11.317 ;
     RECT  37.2 10.163 37.752 11.365 ;
     RECT  52.944 9.539 52.968 11.365 ;
     RECT  13.104 11.027 13.512 11.459 ;
     RECT  16.368 10.501 16.632 11.461 ;
     RECT  48.96 11.365 48.984 11.461 ;
     RECT  71.568 8.389 71.592 11.461 ;
     RECT  36.96 11.365 37.752 11.555 ;
     RECT  18.6 9.349 19.08 11.557 ;
     RECT  58.992 10.931 59.016 11.557 ;
     RECT  60.048 11.365 60.264 11.557 ;
     RECT  61.344 11.171 62.952 11.603 ;
     RECT  52.944 11.365 53.016 11.605 ;
     RECT  58.992 11.557 60.264 11.699 ;
     RECT  18.48 11.557 19.08 11.701 ;
     RECT  20.112 10.259 20.472 11.701 ;
     RECT  27.744 10.883 29.976 11.747 ;
     RECT  37.056 11.555 37.752 11.747 ;
     RECT  70.656 11.461 71.592 11.747 ;
     RECT  32.016 11.269 33.528 11.797 ;
     RECT  34.8 9.973 35.88 11.797 ;
     RECT  16.32 11.461 16.632 11.891 ;
     RECT  58.992 11.699 59.016 11.891 ;
     RECT  4.896 10.981 5.16 11.939 ;
     RECT  60.048 11.699 60.264 11.939 ;
     RECT  70.944 11.747 71.592 11.939 ;
     RECT  39.264 11.075 41.448 11.941 ;
     RECT  4.896 11.939 4.92 11.987 ;
     RECT  48.96 11.461 49.032 11.989 ;
     RECT  9.504 11.845 9.528 12.035 ;
     RECT  27.84 11.747 29.976 12.035 ;
     RECT  50.736 8.963 51.816 12.035 ;
     RECT  75.84 9.061 75.864 12.037 ;
     RECT  75.84 12.037 75.96 12.083 ;
     RECT  18.48 11.701 20.472 12.085 ;
     RECT  27.984 12.035 29.976 12.085 ;
     RECT  31.008 11.797 35.88 12.085 ;
     RECT  27.984 12.085 35.88 12.131 ;
     RECT  48.96 11.989 49.08 12.133 ;
     RECT  56.4 10.979 56.712 12.133 ;
     RECT  10.512 10.837 10.536 12.179 ;
     RECT  75.936 12.083 75.96 12.179 ;
     RECT  18.432 12.085 20.472 12.181 ;
     RECT  52.944 11.605 53.064 12.181 ;
     RECT  66.384 11.123 67.512 12.181 ;
     RECT  68.784 11.123 68.808 12.181 ;
     RECT  72.6 8.291 73.32 12.181 ;
     RECT  72.096 12.181 73.32 12.227 ;
     RECT  56.4 12.133 57.048 12.371 ;
     RECT  72.096 12.227 73.032 12.371 ;
     RECT  18.432 12.181 21 12.373 ;
     RECT  48.912 12.133 49.08 12.373 ;
     RECT  61.8 11.603 62.952 12.373 ;
     RECT  16.944 12.085 16.968 12.419 ;
     RECT  42.432 11.173 47.016 12.419 ;
     RECT  39.024 11.941 41.448 12.421 ;
     RECT  42.432 12.419 43.944 12.421 ;
     RECT  48.912 12.373 49.512 12.467 ;
     RECT  45.024 12.419 47.016 12.469 ;
     RECT  18.432 12.373 21.096 12.517 ;
     RECT  7.44 9.253 8.112 12.611 ;
     RECT  39.024 12.421 43.944 12.611 ;
     RECT  45.024 12.469 47.784 12.611 ;
     RECT  66.384 12.181 68.808 12.611 ;
     RECT  18.432 12.517 21.24 12.707 ;
     RECT  45.024 12.611 46.776 12.803 ;
     RECT  37.68 11.747 37.752 12.805 ;
     RECT  50.736 12.035 51.432 12.901 ;
     RECT  18.432 12.707 20.472 12.949 ;
     RECT  28.176 12.131 35.88 12.995 ;
     RECT  66.384 12.611 67.944 12.995 ;
     RECT  39.024 12.611 41.448 12.997 ;
     RECT  55.392 12.613 55.416 13.043 ;
     RECT  61.8 12.373 63.816 13.043 ;
     RECT  15.936 11.941 15.96 13.139 ;
     RECT  18.384 12.949 20.472 13.187 ;
     RECT  72.096 12.371 72.912 13.187 ;
     RECT  48.96 12.467 49.512 13.189 ;
     RECT  50.688 12.901 51.432 13.189 ;
     RECT  28.416 12.995 35.88 13.235 ;
     RECT  45.072 12.803 46.776 13.283 ;
     RECT  36.864 12.805 37.752 13.381 ;
     RECT  19.968 13.187 20.472 13.475 ;
     RECT  60.24 11.939 60.264 13.475 ;
     RECT  45.072 13.283 46.728 13.571 ;
     RECT  13.2 11.459 13.512 13.573 ;
     RECT  52.944 12.181 53.976 13.573 ;
     RECT  56.4 12.371 56.712 13.621 ;
     RECT  28.464 13.235 35.88 13.667 ;
     RECT  52.944 13.573 54.12 13.667 ;
     RECT  28.896 13.667 35.88 13.669 ;
     RECT  36.864 13.381 37.896 13.669 ;
     RECT  65.184 11.269 65.208 13.669 ;
     RECT  66.384 12.995 67.608 13.669 ;
     RECT  28.896 13.669 37.896 13.763 ;
     RECT  45.072 13.571 46.68 13.763 ;
     RECT  52.944 13.667 52.968 13.763 ;
     RECT  56.4 13.621 57 13.765 ;
     RECT  28.896 13.763 37.752 13.955 ;
     RECT  47.76 12.611 47.784 13.957 ;
     RECT  38.88 12.997 41.448 14.003 ;
     RECT  28.896 13.955 35.304 14.099 ;
     RECT  47.76 13.957 47.976 14.147 ;
     RECT  39.792 14.003 41.448 14.197 ;
     RECT  42.432 12.611 43.944 14.197 ;
     RECT  65.184 13.669 67.608 14.197 ;
     RECT  39.792 14.197 43.944 14.243 ;
     RECT  55.92 13.765 57 14.243 ;
     RECT  64.704 14.197 67.608 14.243 ;
     RECT  2.4 11.027 2.712 14.245 ;
     RECT  22.896 11.317 26.568 14.291 ;
     RECT  48.96 13.189 51.432 14.291 ;
     RECT  48.96 14.291 49.752 14.341 ;
     RECT  31.296 14.099 35.304 14.435 ;
     RECT  58.656 12.469 58.68 14.533 ;
     RECT  22.896 14.291 26.376 14.629 ;
     RECT  42.24 14.243 42.456 14.675 ;
     RECT  76.032 13.621 76.056 14.675 ;
     RECT  27.456 14.389 27.48 14.723 ;
     RECT  31.392 14.435 35.304 14.723 ;
     RECT  16.992 13.861 17.016 14.725 ;
     RECT  18.48 13.187 18.912 14.725 ;
     RECT  72.6 13.187 72.912 14.773 ;
     RECT  28.896 14.099 30.072 14.819 ;
     RECT  45.168 13.763 46.68 14.819 ;
     RECT  48.816 14.341 49.752 14.819 ;
     RECT  2.4 14.245 3.384 14.867 ;
     RECT  28.896 14.819 29.976 14.867 ;
     RECT  53.952 13.667 54.12 14.867 ;
     RECT  55.92 14.243 56.712 14.867 ;
     RECT  64.704 14.243 65.208 14.867 ;
     RECT  69.696 14.197 69.72 14.867 ;
     RECT  70.944 11.939 70.968 14.867 ;
     RECT  22.8 14.629 26.376 14.869 ;
     RECT  22.752 14.869 26.376 15.011 ;
     RECT  48.96 14.819 49.752 15.011 ;
     RECT  16.992 14.725 18.912 15.203 ;
     RECT  28.896 14.867 29.88 15.203 ;
     RECT  43.92 14.243 43.944 15.205 ;
     RECT  43.92 15.205 44.472 15.251 ;
     RECT  55.968 14.867 56.712 15.299 ;
     RECT  72.6 14.773 73.512 15.301 ;
     RECT  61.8 13.043 62.952 15.349 ;
     RECT  20.112 13.475 20.472 15.395 ;
     RECT  53.952 14.867 53.976 15.397 ;
     RECT  14.832 9.059 14.856 15.443 ;
     RECT  58.176 14.533 58.68 15.443 ;
     RECT  13.2 13.573 13.8 15.445 ;
     RECT  39.792 14.243 40.824 15.445 ;
     RECT  45.456 14.819 46.68 15.491 ;
     RECT  39.792 15.445 41.016 15.637 ;
     RECT  36.672 13.955 37.752 15.685 ;
     RECT  38.928 15.637 41.016 15.685 ;
     RECT  17.136 15.203 18.912 15.731 ;
     RECT  36.672 15.685 41.016 15.827 ;
     RECT  61.68 15.349 62.952 15.827 ;
     RECT  28.896 15.203 29.832 15.923 ;
     RECT  11.808 15.445 11.832 16.019 ;
     RECT  66.384 14.243 67.608 16.019 ;
     RECT  39.792 15.827 41.016 16.069 ;
     RECT  42.432 14.675 42.456 16.069 ;
     RECT  42.432 16.069 42.6 16.211 ;
     RECT  60.384 15.925 60.408 16.261 ;
     RECT  67.104 16.019 67.608 16.307 ;
     RECT  31.536 14.723 35.304 16.309 ;
     RECT  36.672 15.827 38.664 16.309 ;
     RECT  20.112 15.395 20.424 16.357 ;
     RECT  21.744 15.877 21.768 16.357 ;
     RECT  59.712 16.261 60.408 16.403 ;
     RECT  52.992 15.397 53.976 16.405 ;
     RECT  42.432 16.211 42.456 16.453 ;
     RECT  44.448 15.251 44.472 16.453 ;
     RECT  2.4 14.867 2.712 16.501 ;
     RECT  72.6 15.301 74.088 16.547 ;
     RECT  47.76 14.147 47.784 16.549 ;
     RECT  48.96 15.011 48.984 16.549 ;
     RECT  61.8 15.827 62.952 16.597 ;
     RECT  47.76 16.549 48.984 16.645 ;
     RECT  52.992 16.405 54.36 16.645 ;
     RECT  60.384 16.403 60.408 16.789 ;
     RECT  61.8 16.597 63.672 16.789 ;
     RECT  13.2 15.445 14.328 16.835 ;
     RECT  47.76 16.645 49.08 16.883 ;
     RECT  52.656 16.645 54.36 16.883 ;
     RECT  43.872 16.453 44.472 16.885 ;
     RECT  45.456 15.491 46.488 16.885 ;
     RECT  42.24 16.453 42.456 16.931 ;
     RECT  17.136 15.731 17.16 16.933 ;
     RECT  11.28 16.117 11.304 16.979 ;
     RECT  39.792 16.069 41.112 16.981 ;
     RECT  31.536 16.309 38.664 17.029 ;
     RECT  17.04 16.933 17.16 17.075 ;
     RECT  20.112 16.357 21.768 17.075 ;
     RECT  28.896 15.923 29.712 17.077 ;
     RECT  17.04 17.075 17.064 17.123 ;
     RECT  30.72 17.029 38.664 17.123 ;
     RECT  47.76 16.883 48.936 17.123 ;
     RECT  22.896 15.011 26.376 17.125 ;
     RECT  30.72 17.123 32.328 17.171 ;
     RECT  13.2 16.835 13.8 17.173 ;
     RECT  33.408 17.123 38.664 17.219 ;
     RECT  39.696 16.981 41.112 17.317 ;
     RECT  52.8 16.883 54.36 17.363 ;
     RECT  2.4 16.501 3.144 17.411 ;
     RECT  37.008 17.219 38.664 17.509 ;
     RECT  39.696 17.317 41.304 17.509 ;
     RECT  22.896 17.125 27.144 17.555 ;
     RECT  43.872 16.885 46.488 17.555 ;
     RECT  27.12 17.555 27.144 17.651 ;
     RECT  31.008 17.171 32.328 17.651 ;
     RECT  43.872 17.555 46.2 17.651 ;
     RECT  47.76 17.123 48.12 17.651 ;
     RECT  52.8 17.363 53.976 17.651 ;
     RECT  70.704 16.309 70.728 17.651 ;
     RECT  5.28 16.501 5.304 17.653 ;
     RECT  20.112 17.075 21.096 17.699 ;
     RECT  58.656 15.443 58.68 17.747 ;
     RECT  51 14.291 51.432 17.749 ;
     RECT  33.408 17.219 35.976 17.795 ;
     RECT  33.408 17.795 33.672 18.131 ;
     RECT  37.008 17.509 41.304 18.131 ;
     RECT  42.432 16.931 42.456 18.133 ;
     RECT  31.008 17.651 32.136 18.179 ;
     RECT  34.8 17.795 35.976 18.179 ;
     RECT  43.872 17.651 43.896 18.179 ;
     RECT  52.8 17.651 53.832 18.179 ;
     RECT  60.384 16.789 63.672 18.179 ;
     RECT  28.848 17.077 29.712 18.181 ;
     RECT  51 17.749 51.624 18.181 ;
     RECT  59.76 18.181 59.784 18.229 ;
     RECT  20.112 17.699 20.136 18.275 ;
     RECT  38.736 18.131 41.304 18.275 ;
     RECT  59.664 18.229 59.784 18.371 ;
     RECT  22.896 17.555 25.8 18.421 ;
     RECT  72.6 16.547 73.512 18.467 ;
     RECT  56.4 15.299 56.712 18.469 ;
     RECT  61.008 18.179 63.672 18.515 ;
     RECT  75.216 15.925 75.24 18.565 ;
     RECT  22.8 18.421 25.8 18.611 ;
     RECT  37.008 18.131 37.704 18.659 ;
     RECT  22.896 18.611 25.8 18.803 ;
     RECT  61.008 18.515 62.112 18.803 ;
     RECT  31.728 18.179 32.136 18.805 ;
     RECT  33.408 18.131 33.432 18.805 ;
     RECT  31.728 18.805 33.432 19.043 ;
     RECT  31.728 19.043 33.096 19.091 ;
     RECT  28.752 18.181 29.712 19.141 ;
     RECT  18.6 15.731 18.912 19.189 ;
     RECT  42.432 18.133 42.84 19.235 ;
     RECT  23.76 18.803 25.8 19.237 ;
     RECT  32.112 19.091 33.096 19.283 ;
     RECT  50.592 18.181 51.624 19.285 ;
     RECT  52.8 18.179 52.824 19.285 ;
     RECT  50.592 19.285 52.824 19.331 ;
     RECT  37.68 18.659 37.704 19.333 ;
     RECT  69.072 18.757 69.096 19.333 ;
     RECT  28.752 19.141 30.216 19.379 ;
     RECT  71.232 17.653 71.256 19.379 ;
     RECT  4.56 17.653 5.304 19.427 ;
     RECT  10.848 17.989 10.872 19.427 ;
     RECT  44.88 17.651 46.2 19.571 ;
     RECT  34.8 18.179 35.112 19.621 ;
     RECT  78 7.619 78.312 19.765 ;
     RECT  51 19.331 52.824 19.811 ;
     RECT  63.792 18.757 63.816 19.859 ;
     RECT  53.808 18.179 53.832 19.909 ;
     RECT  59.76 18.371 59.784 19.909 ;
     RECT  75.216 18.565 75.816 19.909 ;
     RECT  69.072 19.333 69.144 19.955 ;
     RECT  18.336 19.189 18.912 20.003 ;
     RECT  42.432 19.235 42.456 20.003 ;
     RECT  13.104 17.173 13.8 20.101 ;
     RECT  13.104 20.101 14.232 20.149 ;
     RECT  15.648 19.333 15.672 20.149 ;
     RECT  34.8 19.621 35.496 20.339 ;
     RECT  29.4 19.379 30.216 20.341 ;
     RECT  39.696 18.275 41.304 20.387 ;
     RECT  78 19.765 78.648 20.435 ;
     RECT  5.28 19.427 5.304 20.485 ;
     RECT  32.112 19.283 32.136 20.579 ;
     RECT  59.76 19.909 59.88 20.579 ;
     RECT  23.76 19.237 26.232 20.627 ;
     RECT  13.104 20.149 15.672 20.675 ;
     RECT  53.808 19.909 54.408 20.723 ;
     RECT  13.104 20.675 15.048 20.869 ;
     RECT  61.68 18.803 62.112 20.869 ;
     RECT  56.4 18.469 57 20.915 ;
     RECT  29.4 20.341 30.84 20.965 ;
     RECT  43.872 20.485 43.896 20.965 ;
     RECT  72.6 18.467 72.912 20.965 ;
     RECT  45.024 19.571 46.2 21.011 ;
     RECT  74.928 19.909 75.816 21.011 ;
     RECT  34.8 20.339 35.112 21.013 ;
     RECT  72.48 20.965 72.912 21.107 ;
     RECT  29.4 20.965 31.944 21.155 ;
     RECT  51 19.811 52.728 21.155 ;
     RECT  58.704 18.805 58.728 21.155 ;
     RECT  30.816 21.155 31.944 21.203 ;
     RECT  61.68 20.869 62.376 21.205 ;
     RECT  5.28 20.485 5.688 21.251 ;
     RECT  34.656 21.013 35.112 21.251 ;
     RECT  2.4 17.411 2.712 21.253 ;
     RECT  61.68 21.205 62.664 21.253 ;
     RECT  7.8 12.611 8.112 21.301 ;
     RECT  65.184 14.867 65.208 21.301 ;
     RECT  47.808 17.651 48.12 21.397 ;
     RECT  31.392 21.203 31.944 21.443 ;
     RECT  67.2 16.307 67.608 21.539 ;
     RECT  37.68 19.333 38.088 21.587 ;
     RECT  7.536 21.301 8.112 21.589 ;
     RECT  78 20.435 78.312 21.637 ;
     RECT  2.4 21.253 2.904 21.683 ;
     RECT  10.8 21.013 10.824 21.683 ;
     RECT  71.232 21.061 71.256 21.683 ;
     RECT  18.6 20.003 18.912 21.781 ;
     RECT  9.12 21.541 9.144 21.827 ;
     RECT  65.184 21.301 65.64 21.829 ;
     RECT  67.2 21.539 67.512 21.829 ;
     RECT  63.936 19.861 63.96 21.925 ;
     RECT  63.936 21.925 64.104 21.971 ;
     RECT  39.696 20.387 40.512 21.973 ;
     RECT  56.4 20.915 56.712 22.021 ;
     RECT  37.872 21.587 38.088 22.069 ;
     RECT  59.76 20.579 59.784 22.117 ;
     RECT  43.824 20.965 43.896 22.163 ;
     RECT  21.12 18.325 21.144 22.165 ;
     RECT  74.928 21.011 74.952 22.165 ;
     RECT  26.208 20.627 26.232 22.259 ;
     RECT  31.584 21.443 31.944 22.259 ;
     RECT  36.432 21.973 36.456 22.259 ;
     RECT  45.6 21.011 46.2 22.259 ;
     RECT  65.184 21.829 67.512 22.259 ;
     RECT  7.488 21.589 8.112 22.307 ;
     RECT  65.184 22.259 65.64 22.451 ;
     RECT  31.584 22.259 31.608 22.499 ;
     RECT  78 21.637 78.408 22.499 ;
     RECT  52.368 21.155 52.728 22.547 ;
     RECT  53.808 20.723 53.832 22.547 ;
     RECT  37.872 22.069 38.328 22.549 ;
     RECT  39.696 21.973 40.728 22.549 ;
     RECT  59.76 22.117 60.408 22.691 ;
     RECT  37.872 22.549 40.728 22.741 ;
     RECT  61.68 21.253 62.76 22.741 ;
     RECT  72.6 21.107 72.912 22.741 ;
     RECT  74.544 22.165 74.952 22.741 ;
     RECT  37.2 22.741 40.728 22.787 ;
     RECT  72.6 22.741 74.952 22.787 ;
     RECT  76.224 22.117 76.248 22.787 ;
     RECT  5.28 21.251 5.304 22.789 ;
     RECT  23.76 20.627 25.128 22.835 ;
     RECT  65.616 22.451 65.64 22.835 ;
     RECT  18.6 21.781 19.032 22.979 ;
     RECT  13.056 20.869 15.048 23.027 ;
     RECT  45.6 22.259 46.056 23.077 ;
     RECT  23.76 22.835 24.312 23.123 ;
     RECT  29.4 21.155 29.832 23.123 ;
     RECT  39.264 22.787 40.728 23.123 ;
     RECT  74.928 22.787 74.952 23.173 ;
     RECT  74.928 23.173 75.24 23.219 ;
     RECT  31.536 23.029 31.56 23.269 ;
     RECT  56.4 22.021 57.096 23.269 ;
     RECT  52.704 22.547 52.728 23.315 ;
     RECT  44.976 23.077 46.056 23.317 ;
     RECT  64.08 21.971 64.104 23.317 ;
     RECT  70.416 22.741 70.44 23.317 ;
     RECT  70.416 23.317 70.68 23.363 ;
     RECT  37.2 22.787 38.088 23.507 ;
     RECT  37.2 23.507 37.224 23.555 ;
     RECT  43.92 22.165 43.944 23.555 ;
     RECT  60.864 22.741 62.76 23.555 ;
     RECT  72.6 22.787 73.848 23.555 ;
     RECT  61.68 23.555 62.76 23.699 ;
     RECT  44.976 23.317 46.824 23.701 ;
     RECT  47.808 21.397 48.456 23.701 ;
     RECT  21.12 22.165 21.72 23.795 ;
     RECT  56.304 23.269 57.096 23.845 ;
     RECT  44.976 23.701 48.456 23.891 ;
     RECT  61.8 23.699 62.76 23.891 ;
     RECT  63.936 23.317 64.104 23.893 ;
     RECT  69.408 20.485 69.432 23.939 ;
     RECT  12 23.269 12.024 23.987 ;
     RECT  56.304 23.845 57.24 23.987 ;
     RECT  5.28 22.789 5.736 24.035 ;
     RECT  30.912 23.269 31.56 24.085 ;
     RECT  18.6 22.979 18.912 24.277 ;
     RECT  70.656 23.363 70.68 24.371 ;
     RECT  51 21.155 51.312 24.421 ;
     RECT  2.4 21.683 2.712 24.469 ;
     RECT  18.6 24.277 19.464 24.469 ;
     RECT  79.584 24.229 79.608 24.469 ;
     RECT  18.288 24.469 19.464 24.517 ;
     RECT  16.896 23.893 16.92 24.659 ;
     RECT  76.896 24.901 76.92 24.997 ;
     RECT  78 22.499 78.312 24.997 ;
     RECT  79.584 24.469 79.656 25.045 ;
     RECT  29.4 23.123 29.712 25.141 ;
     RECT  29.088 25.141 29.712 25.283 ;
     RECT  76.896 24.997 78.312 25.573 ;
     RECT  79.584 25.045 79.8 25.573 ;
     RECT  24 23.123 24.312 25.621 ;
     RECT  25.776 23.077 25.8 25.621 ;
     RECT  39.264 23.123 40.512 25.621 ;
     RECT  61.8 23.891 62.112 25.621 ;
     RECT  45.6 23.891 48.456 25.667 ;
     RECT  24 25.621 25.8 25.715 ;
     RECT  38.976 25.621 40.512 25.715 ;
     RECT  56.304 23.987 56.808 25.715 ;
     RECT  75.216 23.219 75.24 25.715 ;
     RECT  76.896 25.573 79.8 25.715 ;
     RECT  63.936 23.893 64.488 25.765 ;
     RECT  45.6 25.667 47.016 25.811 ;
     RECT  63.264 25.765 64.488 25.907 ;
     RECT  40.2 25.715 40.512 25.957 ;
     RECT  29.4 25.283 29.712 26.053 ;
     RECT  18.048 24.517 19.464 26.101 ;
     RECT  40.2 25.957 41.064 26.147 ;
     RECT  77.664 25.715 79.8 26.195 ;
     RECT  56.304 25.715 56.712 26.197 ;
     RECT  2.4 24.469 3.48 26.243 ;
     RECT  13.2 23.027 14.232 26.243 ;
     RECT  50.736 24.421 51.312 26.243 ;
     RECT  77.664 26.195 79.752 26.243 ;
     RECT  67.2 22.259 67.512 26.293 ;
     RECT  77.856 26.243 79.752 26.483 ;
     RECT  24 25.715 24.984 26.579 ;
     RECT  77.856 26.483 79.704 26.579 ;
     RECT  45.6 25.811 45.912 26.581 ;
     RECT  44.928 26.581 45.912 26.723 ;
     RECT  5.28 24.035 5.304 26.725 ;
     RECT  5.28 26.725 5.4 26.771 ;
     RECT  76.368 26.581 76.392 26.771 ;
     RECT  61.488 25.621 62.112 26.773 ;
     RECT  74.64 26.053 74.664 26.819 ;
     RECT  38.976 25.715 39 26.867 ;
     RECT  77.856 26.579 79.656 26.867 ;
     RECT  17.952 26.101 19.464 26.869 ;
     RECT  29.4 26.053 29.832 26.869 ;
     RECT  30.912 24.085 31.608 26.869 ;
     RECT  32.976 21.109 33 26.869 ;
     RECT  22.752 25.573 22.776 26.915 ;
     RECT  30.912 26.869 33 26.915 ;
     RECT  31.584 26.915 33 27.011 ;
     RECT  48.432 25.667 48.456 27.059 ;
     RECT  68.928 25.717 68.952 27.059 ;
     RECT  77.904 26.867 79.656 27.059 ;
     RECT  21.12 23.795 21.24 27.061 ;
     RECT  59.76 22.691 59.784 27.061 ;
     RECT  21.12 27.061 21.384 27.107 ;
     RECT  25.92 26.917 25.944 27.107 ;
     RECT  59.568 27.061 59.784 27.107 ;
     RECT  56.208 26.197 56.712 27.109 ;
     RECT  27.888 26.917 27.912 27.155 ;
     RECT  29.088 26.869 29.832 27.155 ;
     RECT  24 26.579 24.552 27.251 ;
     RECT  56.208 27.109 57 27.251 ;
     RECT  56.208 27.251 56.904 27.347 ;
     RECT  61.488 26.773 62.808 27.347 ;
     RECT  63.84 25.907 64.488 27.347 ;
     RECT  66.912 26.293 67.512 27.347 ;
     RECT  52.464 25.045 52.488 27.395 ;
     RECT  61.68 27.347 62.808 27.395 ;
     RECT  64.176 27.347 64.488 27.395 ;
     RECT  77.904 27.059 79.368 27.395 ;
     RECT  46.992 25.811 47.016 27.445 ;
     RECT  46.992 27.445 47.208 27.491 ;
     RECT  64.464 27.395 64.488 27.587 ;
     RECT  40.2 26.147 40.872 27.635 ;
     RECT  50.88 26.243 51.312 27.637 ;
     RECT  50.736 27.637 51.312 27.827 ;
     RECT  47.184 27.491 47.208 27.829 ;
     RECT  54.768 27.013 54.792 27.875 ;
     RECT  15.84 26.053 15.864 27.877 ;
     RECT  51 27.827 51.312 27.877 ;
     RECT  47.184 27.829 48.168 28.163 ;
     RECT  7.8 22.307 8.112 28.165 ;
     RECT  36.288 27.973 36.312 28.259 ;
     RECT  34.8 21.251 35.112 28.405 ;
     RECT  15.408 27.877 15.864 28.453 ;
     RECT  45.6 26.723 45.912 28.453 ;
     RECT  6.816 28.165 8.112 28.499 ;
     RECT  21.36 27.107 21.384 28.501 ;
     RECT  53.568 28.453 53.592 28.501 ;
     RECT  51 27.877 52.248 28.549 ;
     RECT  53.568 28.501 53.88 28.549 ;
     RECT  51 28.549 53.88 28.691 ;
     RECT  21.264 28.501 21.384 28.741 ;
     RECT  21.12 28.741 21.384 28.883 ;
     RECT  40.2 27.635 40.512 28.981 ;
     RECT  56.208 27.347 56.712 28.981 ;
     RECT  53.568 28.691 53.88 29.027 ;
     RECT  21.216 28.883 21.384 29.075 ;
     RECT  13.2 26.243 13.608 29.077 ;
     RECT  25.44 28.789 25.464 29.125 ;
     RECT  78 27.395 79.368 29.125 ;
     RECT  54.672 29.029 54.696 29.171 ;
     RECT  29.4 27.155 29.832 29.221 ;
     RECT  13.104 29.077 13.608 29.267 ;
     RECT  31.584 27.011 31.608 29.269 ;
     RECT  25.44 29.125 26.136 29.363 ;
     RECT  26.112 29.363 26.136 29.459 ;
     RECT  45.6 28.453 46.152 29.507 ;
     RECT  78 29.125 79.8 29.509 ;
     RECT  36.864 29.269 36.888 29.555 ;
     RECT  17.808 26.869 19.464 29.653 ;
     RECT  5.376 26.771 5.4 29.699 ;
     RECT  77.904 29.509 79.8 29.699 ;
     RECT  9.888 29.029 9.912 29.795 ;
     RECT  32.976 27.011 33 29.795 ;
     RECT  61.68 27.395 62.112 29.795 ;
     RECT  45.6 29.507 45.912 29.989 ;
     RECT  43.728 26.725 43.752 30.035 ;
     RECT  55.872 28.981 56.712 30.035 ;
     RECT  53.568 29.027 53.592 30.227 ;
     RECT  40.2 28.981 40.632 30.275 ;
     RECT  56.208 30.035 56.712 30.275 ;
     RECT  63.792 29.605 63.816 30.275 ;
     RECT  70.704 29.653 70.728 30.275 ;
     RECT  77.904 29.699 79.752 30.275 ;
     RECT  7.8 28.499 8.112 30.421 ;
     RECT  27.12 28.405 27.144 30.565 ;
     RECT  7.8 30.421 8.28 30.611 ;
     RECT  27.12 30.565 27.384 30.611 ;
     RECT  13.2 29.267 13.608 30.613 ;
     RECT  76.128 29.893 76.152 30.661 ;
     RECT  31.488 29.269 31.608 30.709 ;
     RECT  31.44 30.709 31.608 30.755 ;
     RECT  78 30.275 79.704 30.803 ;
     RECT  17.808 29.653 20.04 30.805 ;
     RECT  21.264 29.075 21.384 30.805 ;
     RECT  17.808 30.805 21.384 30.851 ;
     RECT  45.312 29.989 45.912 30.851 ;
     RECT  51 28.691 52.248 30.853 ;
     RECT  78 30.803 79.656 30.899 ;
     RECT  20.544 30.851 21.384 30.947 ;
     RECT  13.104 30.613 13.608 31.043 ;
     RECT  2.4 26.243 2.712 31.093 ;
     RECT  48.144 28.163 48.168 31.093 ;
     RECT  81.888 30.949 81.912 31.139 ;
     RECT  50.88 30.853 52.248 31.187 ;
     RECT  10.992 24.613 11.016 31.189 ;
     RECT  17.808 30.851 19.464 31.285 ;
     RECT  51 31.187 52.248 31.285 ;
     RECT  51 31.285 52.728 31.619 ;
     RECT  7.8 30.611 8.112 31.621 ;
     RECT  45.6 30.851 45.912 31.621 ;
     RECT  17.04 31.285 19.464 31.669 ;
     RECT  72.6 23.555 72.912 31.669 ;
     RECT  10.992 31.189 11.352 31.765 ;
     RECT  29.232 29.221 29.832 31.909 ;
     RECT  27.36 30.611 27.384 31.955 ;
     RECT  13.2 31.043 13.608 32.005 ;
     RECT  21.264 30.947 21.384 32.005 ;
     RECT  71.808 31.669 72.912 32.099 ;
     RECT  36.72 31.573 36.744 32.195 ;
     RECT  47.808 31.093 48.168 32.195 ;
     RECT  10.992 31.765 11.496 32.197 ;
     RECT  66.048 30.709 66.072 32.243 ;
     RECT  29.088 31.909 29.832 32.291 ;
     RECT  76.128 30.661 76.92 32.291 ;
     RECT  59.568 27.107 59.592 32.293 ;
     RECT  6.912 31.621 8.112 32.437 ;
     RECT  79.632 30.899 79.656 32.531 ;
     RECT  76.128 32.291 76.392 32.579 ;
     RECT  51 31.619 52.248 32.581 ;
     RECT  49.728 32.149 49.752 32.629 ;
     RECT  51 32.581 53.064 32.629 ;
     RECT  42.576 32.053 42.6 32.771 ;
     RECT  49.728 32.629 53.064 32.771 ;
     RECT  31.44 30.755 31.512 32.773 ;
     RECT  29.136 32.291 29.832 32.869 ;
     RECT  31.056 32.773 31.512 32.869 ;
     RECT  61.8 29.795 62.112 32.869 ;
     RECT  41.52 31.237 41.544 32.963 ;
     RECT  49.728 32.771 52.248 33.011 ;
     RECT  53.856 32.821 53.88 33.011 ;
     RECT  2.4 31.093 2.856 33.013 ;
     RECT  15.168 28.453 15.864 33.013 ;
     RECT  29.136 32.869 31.512 33.059 ;
     RECT  45.6 31.621 46.2 33.061 ;
     RECT  70.272 32.101 70.296 33.061 ;
     RECT  6.912 32.437 8.904 33.107 ;
     RECT  16.944 31.669 19.464 33.107 ;
     RECT  31.44 33.059 31.512 33.155 ;
     RECT  45.024 33.061 46.2 33.203 ;
     RECT  78 30.899 78.312 33.205 ;
     RECT  20.448 32.005 21.384 33.347 ;
     RECT  21.072 33.347 21.384 33.395 ;
     RECT  67.2 27.347 67.512 33.397 ;
     RECT  2.304 33.013 2.856 33.443 ;
     RECT  50.544 33.011 52.248 33.491 ;
     RECT  24 27.251 24.408 33.589 ;
     RECT  36.432 32.485 36.456 33.589 ;
     RECT  60.864 32.869 62.112 33.635 ;
     RECT  29.136 33.059 29.832 33.731 ;
     RECT  43.728 32.725 43.752 33.731 ;
     RECT  10.992 32.197 11.928 33.779 ;
     RECT  14.64 33.013 15.864 33.827 ;
     RECT  69.792 33.061 70.296 33.827 ;
     RECT  13.2 32.005 13.656 34.117 ;
     RECT  17.808 33.107 19.464 34.165 ;
     RECT  66.72 33.397 67.512 34.211 ;
     RECT  2.304 33.443 2.712 34.259 ;
     RECT  74.64 33.589 74.664 34.259 ;
     RECT  31.488 33.155 31.512 34.453 ;
     RECT  34.8 28.405 35.256 34.453 ;
     RECT  34.8 34.453 35.4 34.501 ;
     RECT  36.432 33.589 36.696 34.547 ;
     RECT  26.784 33.445 26.808 34.643 ;
     RECT  34.608 34.501 35.4 34.691 ;
     RECT  53.76 33.925 53.784 34.693 ;
     RECT  10.992 33.779 11.496 34.741 ;
     RECT  72.6 32.099 72.912 34.741 ;
     RECT  74.688 34.597 74.712 34.787 ;
     RECT  6.912 33.107 8.112 34.883 ;
     RECT  48.144 32.195 48.168 34.885 ;
     RECT  72.048 34.741 72.912 34.931 ;
     RECT  48.144 34.885 49.032 35.027 ;
     RECT  13.2 34.117 13.896 35.171 ;
     RECT  15.168 33.827 15.864 35.219 ;
     RECT  50.592 33.491 52.248 35.269 ;
     RECT  53.664 34.693 53.784 35.269 ;
     RECT  54.912 34.069 54.936 35.269 ;
     RECT  61.8 33.635 62.112 35.269 ;
     RECT  29.4 33.731 29.832 35.317 ;
     RECT  40.2 30.275 40.512 35.317 ;
     RECT  63.36 34.741 64.2 35.317 ;
     RECT  65.376 34.741 65.4 35.317 ;
     RECT  77.904 33.205 78.312 35.317 ;
     RECT  10.08 34.741 11.496 35.363 ;
     RECT  29.088 35.317 29.832 35.363 ;
     RECT  63.36 35.317 65.4 35.363 ;
     RECT  61.056 35.269 62.112 35.413 ;
     RECT  63.36 35.363 63.384 35.413 ;
     RECT  31.488 34.453 31.656 35.605 ;
     RECT  31.344 35.605 31.656 35.651 ;
     RECT  44.448 35.509 44.472 35.651 ;
     RECT  61.056 35.413 63.384 35.651 ;
     RECT  67.2 34.211 67.512 35.653 ;
     RECT  17.376 34.165 19.464 35.699 ;
     RECT  21.36 33.395 21.384 35.701 ;
     RECT  22.704 27.157 22.728 35.701 ;
     RECT  61.056 35.651 62.112 35.891 ;
     RECT  25.68 31.285 25.704 35.893 ;
     RECT  34.608 34.691 35.256 35.939 ;
     RECT  40.08 35.317 40.872 35.939 ;
     RECT  77.376 35.317 78.312 35.939 ;
     RECT  7.104 34.883 8.112 35.941 ;
     RECT  70.272 33.827 70.296 35.941 ;
     RECT  76.128 32.579 76.152 35.941 ;
     RECT  53.664 35.269 54.936 35.987 ;
     RECT  64.416 35.363 65.4 35.987 ;
     RECT  70.272 35.941 70.68 35.987 ;
     RECT  75.84 35.941 76.152 35.987 ;
     RECT  63.36 35.651 63.384 36.035 ;
     RECT  34.8 35.939 35.256 36.085 ;
     RECT  36.672 34.547 36.696 36.085 ;
     RECT  67.2 35.653 68.328 36.229 ;
     RECT  72.6 34.931 72.912 36.229 ;
     RECT  31.344 35.651 31.512 36.275 ;
     RECT  24 33.589 24.504 36.421 ;
     RECT  25.68 35.893 25.944 36.421 ;
     RECT  67.2 36.229 69.24 36.421 ;
     RECT  70.656 35.987 70.68 36.515 ;
     RECT  6.384 35.941 8.112 36.755 ;
     RECT  37.68 35.317 37.704 36.755 ;
     RECT  67.2 36.421 69.288 36.755 ;
     RECT  67.2 36.755 69.24 36.803 ;
     RECT  71.856 36.229 73.8 36.851 ;
     RECT  48.144 35.027 48.168 36.901 ;
     RECT  53.664 35.987 53.688 36.901 ;
     RECT  59.568 32.293 59.736 36.901 ;
     RECT  54.912 35.987 54.936 36.947 ;
     RECT  2.4 34.259 2.712 36.949 ;
     RECT  31.344 36.275 31.368 36.995 ;
     RECT  10.992 35.363 11.496 36.997 ;
     RECT  13.2 35.171 13.656 36.997 ;
     RECT  40.08 35.939 40.512 37.043 ;
     RECT  17.568 35.699 19.464 37.091 ;
     RECT  38.832 36.949 38.856 37.091 ;
     RECT  50.112 35.269 52.248 37.091 ;
     RECT  72.288 36.851 73.8 37.091 ;
     RECT  29.088 35.363 29.712 37.093 ;
     RECT  43.296 35.893 43.32 37.141 ;
     RECT  10.992 36.997 13.656 37.379 ;
     RECT  45.6 33.203 46.2 37.429 ;
     RECT  78 35.939 78.312 37.429 ;
     RECT  67.2 36.803 67.512 37.573 ;
     RECT  34.8 36.085 36.696 37.619 ;
     RECT  27.936 37.573 27.96 37.669 ;
     RECT  28.992 37.093 29.712 37.669 ;
     RECT  34.8 37.619 36.504 37.715 ;
     RECT  67.104 37.573 67.512 37.717 ;
     RECT  21.36 35.701 22.728 37.765 ;
     RECT  51 37.091 52.248 37.765 ;
     RECT  53.568 36.901 53.688 37.765 ;
     RECT  27.936 37.669 29.712 37.813 ;
     RECT  59.568 36.901 60.456 37.859 ;
     RECT  27.024 37.813 29.712 37.955 ;
     RECT  75.84 35.987 75.864 37.955 ;
     RECT  72.288 37.091 72.912 37.957 ;
     RECT  78 37.429 78.408 37.957 ;
     RECT  47.664 36.901 48.168 38.003 ;
     RECT  68.64 36.803 69.24 38.003 ;
     RECT  21.36 37.765 22.824 38.099 ;
     RECT  78 37.957 78.552 38.099 ;
     RECT  2.4 36.949 3.432 38.147 ;
     RECT  43.296 37.141 43.512 38.147 ;
     RECT  17.808 37.091 19.464 38.149 ;
     RECT  64.416 35.987 65.256 38.149 ;
     RECT  27.936 37.955 29.712 38.243 ;
     RECT  43.488 38.147 43.512 38.291 ;
     RECT  67.056 37.717 67.512 38.339 ;
     RECT  48.144 38.003 48.168 38.341 ;
     RECT  48.144 38.341 48.408 38.387 ;
     RECT  15.84 35.219 15.864 38.533 ;
     RECT  61.8 35.891 62.112 38.533 ;
     RECT  7.104 36.755 8.112 38.629 ;
     RECT  6.816 38.629 8.112 38.771 ;
     RECT  5.52 38.005 5.544 38.819 ;
     RECT  48.384 38.387 48.408 38.819 ;
     RECT  64.368 38.149 65.256 38.819 ;
     RECT  71.808 37.957 72.912 38.867 ;
     RECT  74.304 38.725 74.328 38.965 ;
     RECT  74.304 38.965 74.472 39.011 ;
     RECT  78 38.099 78.408 39.107 ;
     RECT  59.568 37.859 59.736 39.109 ;
     RECT  68.64 38.003 68.664 39.157 ;
     RECT  34.8 37.715 35.784 39.203 ;
     RECT  34.8 39.203 35.352 39.205 ;
     RECT  65.232 38.819 65.256 39.301 ;
     RECT  67.2 38.339 67.512 39.301 ;
     RECT  17.808 38.149 19.8 39.347 ;
     RECT  14.976 38.533 15.864 39.493 ;
     RECT  21.36 38.099 22.728 39.541 ;
     RECT  13.2 37.379 13.656 39.587 ;
     RECT  58.512 38.533 58.536 39.635 ;
     RECT  21.36 39.541 22.824 39.637 ;
     RECT  24 36.421 25.944 39.637 ;
     RECT  66.72 39.301 67.512 39.637 ;
     RECT  68.64 39.157 69.432 39.637 ;
     RECT  14.976 39.493 16.824 39.685 ;
     RECT  17.808 39.347 19.464 39.685 ;
     RECT  13.2 39.587 13.608 39.829 ;
     RECT  59.568 39.109 59.784 39.923 ;
     RECT  74.448 39.011 74.472 39.923 ;
     RECT  7.104 38.771 8.112 39.971 ;
     RECT  49.584 38.197 49.608 40.019 ;
     RECT  54.768 38.725 54.792 40.019 ;
     RECT  28.176 38.243 29.712 40.259 ;
     RECT  21.36 39.637 25.944 40.261 ;
     RECT  43.584 40.021 43.608 40.307 ;
     RECT  27.12 39.829 27.144 40.309 ;
     RECT  28.176 40.259 28.2 40.309 ;
     RECT  45.6 37.429 46.296 40.405 ;
     RECT  59.568 39.923 59.736 40.499 ;
     RECT  65.232 39.301 65.544 40.499 ;
     RECT  56.4 30.275 56.712 40.501 ;
     RECT  65.52 40.499 65.544 40.547 ;
     RECT  61.056 38.533 62.112 40.549 ;
     RECT  38.16 38.149 38.184 40.595 ;
     RECT  56.4 40.501 56.904 40.643 ;
     RECT  34.32 39.205 35.352 40.645 ;
     RECT  27.12 40.309 28.2 40.691 ;
     RECT  45.36 40.405 46.296 40.691 ;
     RECT  61.008 40.549 62.112 40.691 ;
     RECT  59.664 40.499 59.736 40.739 ;
     RECT  56.4 40.643 56.808 40.787 ;
     RECT  72.24 38.867 72.912 40.789 ;
     RECT  34.32 40.645 35.976 40.835 ;
     RECT  66.72 39.637 69.432 40.835 ;
     RECT  34.8 40.835 35.976 40.883 ;
     RECT  54.72 40.597 54.744 40.979 ;
     RECT  71.808 40.789 72.912 40.979 ;
     RECT  27.264 40.691 28.2 41.027 ;
     RECT  66.72 40.835 68.424 41.077 ;
     RECT  66.528 41.077 68.424 41.219 ;
     RECT  34.8 40.883 35.832 41.267 ;
     RECT  14.976 39.685 19.464 41.509 ;
     RECT  2.4 38.147 2.712 41.605 ;
     RECT  20.544 40.261 25.944 41.651 ;
     RECT  51 37.765 53.688 41.651 ;
     RECT  58.032 40.405 58.056 41.651 ;
     RECT  20.544 41.651 20.568 41.747 ;
     RECT  7.8 39.971 8.112 41.749 ;
     RECT  55.056 41.653 55.08 41.795 ;
     RECT  40.2 37.043 40.512 41.893 ;
     RECT  45.6 40.691 46.104 41.941 ;
     RECT  61.056 40.691 62.112 41.989 ;
     RECT  78 39.107 78.312 41.989 ;
     RECT  2.4 41.605 3.432 42.037 ;
     RECT  78 41.989 78.792 42.085 ;
     RECT  70.656 42.469 70.68 42.517 ;
     RECT  51 41.651 52.248 42.613 ;
     RECT  53.664 41.651 53.688 42.613 ;
     RECT  65.808 41.797 65.832 42.613 ;
     RECT  31.008 42.517 31.032 42.659 ;
     RECT  2.4 42.037 3.528 42.709 ;
     RECT  45.504 41.941 46.104 42.709 ;
     RECT  65.808 42.613 66.168 42.755 ;
     RECT  12.768 39.829 13.608 42.757 ;
     RECT  14.88 41.509 19.464 42.757 ;
     RECT  2.4 42.709 4.104 42.803 ;
     RECT  12.768 42.757 19.464 42.803 ;
     RECT  22.032 41.651 25.128 42.803 ;
     RECT  22.032 42.803 24.888 42.805 ;
     RECT  76.32 41.989 76.728 42.805 ;
     RECT  75.84 42.805 76.728 42.995 ;
     RECT  10.992 37.379 11.496 42.997 ;
     RECT  12.768 42.803 14.568 42.997 ;
     RECT  74.688 42.949 74.712 43.093 ;
     RECT  75.84 42.995 76.344 43.139 ;
     RECT  39.936 41.893 40.512 43.187 ;
     RECT  45.504 42.709 46.152 43.237 ;
     RECT  56.4 40.787 56.712 43.285 ;
     RECT  61.056 41.989 62.712 43.285 ;
     RECT  74.592 43.093 74.712 43.285 ;
     RECT  65.952 42.755 66.168 43.331 ;
     RECT  7.248 41.749 8.112 43.379 ;
     RECT  15.84 42.803 19.464 43.525 ;
     RECT  21.072 42.805 24.888 43.525 ;
     RECT  55.632 43.285 56.712 43.525 ;
     RECT  59.712 40.739 59.736 43.525 ;
     RECT  61.008 43.285 62.712 43.525 ;
     RECT  67.2 41.219 68.424 43.573 ;
     RECT  69.408 40.835 69.432 43.573 ;
     RECT  37.68 43.285 37.704 43.669 ;
     RECT  59.712 43.525 62.712 43.669 ;
     RECT  55.392 43.525 56.712 43.715 ;
     RECT  67.2 43.573 69.432 43.765 ;
     RECT  15.84 43.525 24.888 43.811 ;
     RECT  21.072 43.811 24.888 43.813 ;
     RECT  2.4 42.803 2.952 43.861 ;
     RECT  4.08 42.803 4.104 43.861 ;
     RECT  59.712 43.669 63.336 43.909 ;
     RECT  64.464 43.717 64.488 43.909 ;
     RECT  2.304 43.861 4.104 44.051 ;
     RECT  45.216 43.237 46.152 44.099 ;
     RECT  67.2 43.765 69.528 44.099 ;
     RECT  10.992 42.997 14.568 44.149 ;
     RECT  55.632 43.715 56.712 44.149 ;
     RECT  49.248 44.053 49.272 44.195 ;
     RECT  51 42.613 53.688 44.243 ;
     RECT  55.632 44.149 57.048 44.291 ;
     RECT  9.264 43.285 9.288 44.341 ;
     RECT  65.952 43.331 65.976 44.341 ;
     RECT  67.2 44.099 69.432 44.341 ;
     RECT  47.28 44.053 47.304 44.387 ;
     RECT  10.992 44.149 14.616 44.389 ;
     RECT  15.84 43.811 19.464 44.389 ;
     RECT  3.84 44.051 4.104 44.437 ;
     RECT  5.232 42.709 5.256 44.437 ;
     RECT  29.4 40.259 29.712 44.437 ;
     RECT  28.176 41.027 28.2 44.483 ;
     RECT  51 44.243 53.4 44.483 ;
     RECT  65.952 44.341 69.432 44.483 ;
     RECT  37.68 43.669 38.088 44.627 ;
     RECT  59.712 43.909 64.488 44.723 ;
     RECT  9.168 44.341 9.288 44.725 ;
     RECT  10.992 44.389 19.464 44.725 ;
     RECT  55.632 44.291 56.808 44.867 ;
     RECT  70.56 42.517 70.68 44.917 ;
     RECT  42.816 43.765 42.84 44.963 ;
     RECT  10.8 44.725 19.464 44.965 ;
     RECT  9.168 44.725 9.576 45.059 ;
     RECT  10.56 44.965 19.464 45.059 ;
     RECT  61.008 44.723 64.488 45.059 ;
     RECT  34.8 41.267 35.352 45.061 ;
     RECT  12.528 45.059 19.464 45.107 ;
     RECT  55.776 44.867 56.808 45.107 ;
     RECT  72.192 40.979 72.912 45.107 ;
     RECT  74.304 43.285 74.712 45.107 ;
     RECT  12.768 45.107 19.464 45.155 ;
     RECT  21.072 43.813 25.368 45.155 ;
     RECT  3.84 44.437 5.256 45.157 ;
     RECT  64.08 45.059 64.488 45.157 ;
     RECT  74.304 45.107 74.616 45.203 ;
     RECT  13.104 45.155 19.464 45.205 ;
     RECT  52.656 44.483 53.4 45.205 ;
     RECT  64.08 45.157 65.016 45.299 ;
     RECT  13.104 45.205 19.752 45.301 ;
     RECT  13.104 45.301 20.616 45.395 ;
     RECT  13.104 45.395 19.464 45.443 ;
     RECT  56.4 45.107 56.808 45.445 ;
     RECT  78 42.085 78.888 45.445 ;
     RECT  9.36 45.059 9.576 45.539 ;
     RECT  10.56 45.059 11.544 45.539 ;
     RECT  3.84 45.157 5.688 45.541 ;
     RECT  51 44.483 51.312 45.541 ;
     RECT  20.592 45.395 20.616 45.587 ;
     RECT  31.584 45.445 31.608 45.587 ;
     RECT  56.4 45.445 57 45.587 ;
     RECT  61.008 45.059 63.048 45.587 ;
     RECT  64.08 45.299 64.584 45.587 ;
     RECT  29.4 44.437 30.312 45.685 ;
     RECT  29.4 45.685 31.176 45.731 ;
     RECT  58.656 44.437 58.68 45.731 ;
     RECT  70.56 44.917 71.112 45.779 ;
     RECT  2.304 44.051 2.712 45.827 ;
     RECT  26.4 45.301 26.424 45.923 ;
     RECT  41.808 44.917 41.832 45.923 ;
     RECT  77.712 45.445 78.888 45.971 ;
     RECT  77.712 45.971 78.792 46.067 ;
     RECT  64.08 45.587 64.488 46.117 ;
     RECT  66.48 44.483 69.432 46.117 ;
     RECT  13.104 45.443 14.76 46.163 ;
     RECT  2.4 45.827 2.712 46.165 ;
     RECT  3.84 45.541 6.264 46.165 ;
     RECT  50.304 45.541 51.312 46.211 ;
     RECT  59.712 44.723 59.736 46.211 ;
     RECT  13.104 46.163 14.424 46.213 ;
     RECT  72.336 45.107 72.912 46.405 ;
     RECT  74.304 45.203 74.328 46.405 ;
     RECT  22.032 45.155 25.368 46.547 ;
     RECT  10.56 45.539 11.448 46.595 ;
     RECT  65.952 46.117 69.432 46.643 ;
     RECT  2.4 46.165 6.264 46.645 ;
     RECT  34.8 45.061 35.64 46.645 ;
     RECT  39.024 46.117 39.048 46.787 ;
     RECT  9.36 45.539 9.384 46.789 ;
     RECT  33.888 46.645 35.64 46.835 ;
     RECT  7.8 43.379 8.112 46.837 ;
     RECT  9.36 46.789 9.48 46.837 ;
     RECT  29.4 45.731 29.712 46.885 ;
     RECT  31.152 45.731 31.176 46.885 ;
     RECT  61.008 45.587 62.664 46.931 ;
     RECT  65.952 46.643 69 46.933 ;
     RECT  22.032 46.547 22.728 47.075 ;
     RECT  15.84 45.443 19.464 47.173 ;
     RECT  15.84 47.173 20.136 47.269 ;
     RECT  71.088 45.779 71.112 47.269 ;
     RECT  75.84 43.139 75.864 47.269 ;
     RECT  75.696 47.269 75.864 47.317 ;
     RECT  10.8 46.595 11.448 47.363 ;
     RECT  52.656 45.205 53.832 47.363 ;
     RECT  77.712 46.067 78.552 47.363 ;
     RECT  65.856 46.933 69 47.413 ;
     RECT  63.696 46.117 64.488 47.459 ;
     RECT  12.96 46.213 14.424 47.555 ;
     RECT  61.008 46.931 62.232 47.749 ;
     RECT  72.336 46.405 74.376 47.749 ;
     RECT  75.408 47.317 75.864 47.749 ;
     RECT  78 47.363 78.552 47.749 ;
     RECT  13.2 47.555 14.424 47.795 ;
     RECT  7.8 46.837 9.48 47.845 ;
     RECT  37.68 44.627 37.704 47.845 ;
     RECT  56.4 45.587 56.904 47.845 ;
     RECT  60.624 47.749 62.232 47.845 ;
     RECT  65.76 47.413 69 47.845 ;
     RECT  72.336 47.749 75.864 47.845 ;
     RECT  2.4 46.645 6.744 47.893 ;
     RECT  33.888 46.835 35.112 47.939 ;
     RECT  2.304 47.893 6.744 48.181 ;
     RECT  7.8 47.845 9.576 48.181 ;
     RECT  2.304 48.181 9.576 48.229 ;
     RECT  72.336 47.845 76.488 48.229 ;
     RECT  21.504 47.845 21.528 48.277 ;
     RECT  22.512 47.075 22.728 48.277 ;
     RECT  59.808 47.845 62.232 48.325 ;
     RECT  10.8 47.363 11.16 48.373 ;
     RECT  21.504 48.277 22.728 48.419 ;
     RECT  45.216 44.099 45.912 48.419 ;
     RECT  63.696 47.459 63.72 48.419 ;
     RECT  52.656 47.363 52.68 48.421 ;
     RECT  53.808 47.363 53.832 48.421 ;
     RECT  56.4 47.845 57.432 48.467 ;
     RECT  45.504 48.419 45.912 48.469 ;
     RECT  2.304 48.229 9.672 48.515 ;
     RECT  13.2 47.795 13.656 48.659 ;
     RECT  47.904 47.269 47.928 48.659 ;
     RECT  59.184 48.325 62.232 48.707 ;
     RECT  2.304 48.515 5.592 48.803 ;
     RECT  70.656 47.269 71.112 48.805 ;
     RECT  63.264 48.661 63.288 48.851 ;
     RECT  15.456 47.269 20.136 48.947 ;
     RECT  40.2 43.187 40.512 48.949 ;
     RECT  51 46.211 51.312 48.949 ;
     RECT  52.656 48.421 53.832 48.949 ;
     RECT  64.848 47.845 69 48.949 ;
     RECT  70.464 48.805 71.112 48.949 ;
     RECT  10.8 48.373 11.928 48.995 ;
     RECT  15.888 48.947 20.136 48.995 ;
     RECT  51 48.949 53.832 48.997 ;
     RECT  64.848 48.949 71.112 48.997 ;
     RECT  37.68 47.845 38.232 49.043 ;
     RECT  27.312 48.421 27.336 49.045 ;
     RECT  50.016 48.997 53.832 49.045 ;
     RECT  11.904 48.995 11.928 49.091 ;
     RECT  24 46.547 25.368 49.091 ;
     RECT  26.88 49.045 27.336 49.091 ;
     RECT  36.24 48.325 36.264 49.091 ;
     RECT  43.536 47.893 43.56 49.091 ;
     RECT  15.888 48.995 19.464 49.139 ;
     RECT  45.504 48.469 46.776 49.139 ;
     RECT  55.248 47.845 55.272 49.141 ;
     RECT  49.2 49.045 53.832 49.235 ;
     RECT  54.96 49.141 55.272 49.235 ;
     RECT  59.184 48.707 59.208 49.235 ;
     RECT  6.72 48.515 9.672 49.477 ;
     RECT  13.2 48.659 13.512 49.525 ;
     RECT  20.736 49.237 20.856 49.525 ;
     RECT  22.176 48.419 22.728 49.525 ;
     RECT  56.4 48.467 56.808 49.525 ;
     RECT  29.4 46.885 31.176 49.571 ;
     RECT  2.304 48.803 5.16 49.619 ;
     RECT  6.24 49.477 9.672 49.619 ;
     RECT  45.504 49.139 45.912 49.765 ;
     RECT  56.304 49.525 56.808 49.861 ;
     RECT  44.976 49.765 45.912 49.907 ;
     RECT  49.776 49.235 52.68 49.907 ;
     RECT  15.888 49.139 15.912 49.909 ;
     RECT  64.656 48.997 71.112 49.909 ;
     RECT  72.144 48.229 76.488 49.909 ;
     RECT  26.88 49.091 26.904 50.003 ;
     RECT  50.016 49.907 52.68 50.003 ;
     RECT  54.96 49.235 54.984 50.003 ;
     RECT  56.304 49.861 57.144 50.051 ;
     RECT  78 47.749 78.6 50.051 ;
     RECT  34.8 47.939 35.112 50.053 ;
     RECT  60.624 48.707 62.232 50.053 ;
     RECT  16.944 49.139 19.464 50.101 ;
     RECT  6.24 49.619 9.192 50.147 ;
     RECT  78 50.051 78.552 50.147 ;
     RECT  32.592 49.525 32.616 50.195 ;
     RECT  37.68 49.043 37.992 50.195 ;
     RECT  59.808 50.053 62.232 50.195 ;
     RECT  64.656 49.909 76.488 50.195 ;
     RECT  20.736 49.525 22.728 50.243 ;
     RECT  53.808 49.235 53.832 50.243 ;
     RECT  16.944 50.101 19.752 50.291 ;
     RECT  39.792 48.949 40.512 50.293 ;
     RECT  10.8 48.995 10.872 50.339 ;
     RECT  45.504 49.907 45.912 50.341 ;
     RECT  20.736 50.243 21.096 50.435 ;
     RECT  13.056 49.525 13.512 50.579 ;
     RECT  15.504 49.909 15.912 50.677 ;
     RECT  39.408 50.293 40.512 50.723 ;
     RECT  13.2 50.579 13.512 50.725 ;
     RECT  2.304 49.619 5.112 50.771 ;
     RECT  6.24 50.147 6.264 50.771 ;
     RECT  10.8 50.339 10.824 50.771 ;
     RECT  15.36 50.677 15.912 50.771 ;
     RECT  64.656 50.195 75.96 50.771 ;
     RECT  17.328 50.291 19.752 50.819 ;
     RECT  51 50.003 52.68 50.819 ;
     RECT  58.176 49.477 58.2 50.867 ;
     RECT  45.504 50.341 46.008 50.869 ;
     RECT  34.8 50.053 35.208 50.963 ;
     RECT  59.808 50.195 59.832 50.963 ;
     RECT  66.096 50.771 75.96 50.963 ;
     RECT  29.4 49.571 30.12 50.965 ;
     RECT  31.152 49.571 31.176 50.965 ;
     RECT  60.912 50.195 62.232 50.965 ;
     RECT  29.4 50.965 31.176 51.011 ;
     RECT  29.4 51.011 30.792 51.059 ;
     RECT  45.504 50.869 46.584 51.107 ;
     RECT  51 50.819 51.312 51.109 ;
     RECT  52.656 50.819 52.68 51.299 ;
     RECT  2.304 50.771 4.776 51.301 ;
     RECT  15.36 50.771 15.528 51.347 ;
     RECT  17.328 50.819 19.464 51.347 ;
     RECT  45.504 51.107 46.008 51.347 ;
     RECT  56.304 50.051 57 51.347 ;
     RECT  66.288 50.963 75.96 51.347 ;
     RECT  1.776 51.301 4.776 51.395 ;
     RECT  66.288 51.347 70.104 51.395 ;
     RECT  50.736 51.109 51.312 51.397 ;
     RECT  71.088 51.347 75.96 51.445 ;
     RECT  60.912 50.965 62.712 51.491 ;
     RECT  24 49.091 24.312 51.685 ;
     RECT  25.344 49.091 25.368 51.685 ;
     RECT  17.328 51.347 19.128 51.781 ;
     RECT  1.776 51.395 4.536 51.923 ;
     RECT  7.632 50.147 9.192 51.923 ;
     RECT  16.512 51.781 19.128 51.923 ;
     RECT  21.072 50.435 21.096 51.923 ;
     RECT  30.768 51.059 30.792 51.923 ;
     RECT  56.4 51.347 57 51.923 ;
     RECT  61.8 51.491 62.712 51.923 ;
     RECT  56.4 51.923 56.808 51.971 ;
     RECT  64.944 50.771 65.016 51.971 ;
     RECT  45.6 51.347 46.008 52.019 ;
     RECT  48.192 51.061 48.216 52.021 ;
     RECT  47.664 52.021 48.216 52.067 ;
     RECT  7.632 51.923 8.112 52.211 ;
     RECT  64.752 52.021 64.776 52.259 ;
     RECT  13.2 50.725 14.376 52.357 ;
     RECT  3.936 51.923 4.104 52.499 ;
     RECT  17.712 51.923 19.128 52.499 ;
     RECT  37.968 50.195 37.992 52.499 ;
     RECT  22.512 50.243 22.728 52.789 ;
     RECT  1.776 51.923 2.904 52.837 ;
     RECT  24 51.685 25.368 52.883 ;
     RECT  7.68 52.211 8.112 52.885 ;
     RECT  16.512 51.923 16.536 52.933 ;
     RECT  1.584 52.837 2.904 52.981 ;
     RECT  7.68 52.885 8.232 52.981 ;
     RECT  16.512 52.933 16.68 52.981 ;
     RECT  11.088 52.981 11.112 53.029 ;
     RECT  60.528 52.981 60.552 53.029 ;
     RECT  66.384 51.395 70.104 53.075 ;
     RECT  50.688 51.397 51.312 53.219 ;
     RECT  47.664 52.067 47.688 53.363 ;
     RECT  21.6 52.789 22.728 53.413 ;
     RECT  60.432 53.029 60.552 53.461 ;
     RECT  61.8 51.923 62.112 53.461 ;
     RECT  1.488 52.981 2.904 53.557 ;
     RECT  3.984 52.499 4.104 53.557 ;
     RECT  7.68 52.981 9.672 53.557 ;
     RECT  11.088 53.029 11.688 53.557 ;
     RECT  12.672 52.357 14.376 53.557 ;
     RECT  16.368 52.981 16.68 53.557 ;
     RECT  17.712 52.499 18.912 53.557 ;
     RECT  21.456 53.413 22.728 53.557 ;
     RECT  24 52.883 24.312 53.557 ;
     RECT  60.432 53.461 62.112 53.557 ;
     RECT  63.6 52.405 63.624 53.557 ;
     RECT  66.384 53.075 69.864 53.557 ;
     RECT  25.344 52.883 25.368 53.603 ;
     RECT  53.04 51.589 53.064 53.603 ;
     RECT  63.216 53.557 69.864 53.603 ;
     RECT  71.088 51.445 76.248 53.603 ;
     RECT  63.216 53.603 69.48 53.651 ;
     RECT  76.224 53.603 76.248 53.651 ;
     RECT  5.616 53.557 20.232 53.653 ;
     RECT  21.456 53.557 24.312 53.653 ;
     RECT  59.472 53.557 62.112 53.893 ;
     RECT  63.216 53.651 69 53.893 ;
     RECT  1.488 53.557 4.2 53.941 ;
     RECT  59.472 53.893 69 53.941 ;
     RECT  1.488 53.941 4.296 53.989 ;
     RECT  5.616 53.653 24.312 54.009 ;
     RECT  29.4 51.059 29.712 54.009 ;
     RECT  34.8 50.963 35.112 54.009 ;
     RECT  40.2 50.723 40.512 54.009 ;
     RECT  45.6 52.019 45.912 54.009 ;
     RECT  51 53.219 51.312 54.009 ;
     RECT  56.4 51.971 56.712 54.009 ;
     RECT  78 50.147 78.312 54.009 ;
     RECT  5.616 54.009 24.12 54.023 ;
     RECT  29.4 54.009 29.52 54.023 ;
     RECT  34.8 54.009 34.92 54.023 ;
     RECT  40.2 54.009 40.32 54.023 ;
     RECT  45.6 54.009 45.72 54.023 ;
     RECT  51 54.009 51.12 54.023 ;
     RECT  56.4 54.009 56.52 54.023 ;
     RECT  78 54.009 78.12 54.023 ;
     RECT  1.488 53.989 4.392 54.037 ;
     RECT  5.616 54.023 23.688 54.037 ;
     RECT  59.184 53.941 69 55.285 ;
     RECT  1.488 54.037 23.688 56.076 ;
     RECT  1.512 56.076 1.584 56.144 ;
     RECT  1.608 56.076 1.68 56.144 ;
     RECT  1.704 56.076 1.776 56.144 ;
     RECT  1.8 56.076 1.872 56.144 ;
     RECT  1.896 56.076 1.968 56.144 ;
     RECT  1.992 56.076 2.064 56.144 ;
     RECT  2.088 56.076 2.16 56.144 ;
     RECT  2.184 56.076 2.256 56.144 ;
     RECT  2.28 56.076 2.352 56.144 ;
     RECT  2.376 56.076 2.448 56.144 ;
     RECT  2.472 56.076 2.544 56.144 ;
     RECT  2.568 56.076 2.64 56.144 ;
     RECT  2.664 56.076 2.736 56.144 ;
     RECT  2.76 56.076 2.832 56.144 ;
     RECT  2.856 56.076 2.928 56.144 ;
     RECT  2.952 56.076 3.024 56.144 ;
     RECT  3.048 56.076 3.12 56.144 ;
     RECT  3.144 56.076 3.216 56.144 ;
     RECT  3.24 56.076 3.312 56.144 ;
     RECT  3.336 56.076 3.408 56.144 ;
     RECT  3.432 56.076 3.504 56.144 ;
     RECT  3.528 56.076 3.6 56.144 ;
     RECT  3.624 56.076 3.696 56.144 ;
     RECT  3.72 56.076 3.792 56.144 ;
     RECT  3.816 56.076 3.888 56.144 ;
     RECT  3.912 56.076 3.984 56.144 ;
     RECT  4.008 56.076 4.08 56.144 ;
     RECT  4.104 56.076 4.176 56.144 ;
     RECT  4.2 56.076 4.272 56.144 ;
     RECT  4.296 56.076 4.368 56.144 ;
     RECT  4.392 56.076 4.464 56.144 ;
     RECT  4.488 56.076 5.328 56.144 ;
     RECT  5.352 56.076 5.424 56.144 ;
     RECT  5.448 56.076 5.52 56.144 ;
     RECT  5.544 56.076 5.616 56.144 ;
     RECT  5.64 56.076 5.712 56.144 ;
     RECT  5.736 56.076 5.808 56.144 ;
     RECT  5.832 56.076 5.904 56.144 ;
     RECT  5.928 56.076 6 56.144 ;
     RECT  6.024 56.076 6.096 56.144 ;
     RECT  6.12 56.076 6.192 56.144 ;
     RECT  6.216 56.076 6.288 56.144 ;
     RECT  6.312 56.076 6.384 56.144 ;
     RECT  6.408 56.076 6.48 56.144 ;
     RECT  6.504 56.076 6.576 56.144 ;
     RECT  6.6 56.076 6.672 56.144 ;
     RECT  6.696 56.076 6.768 56.144 ;
     RECT  6.792 56.076 6.864 56.144 ;
     RECT  6.888 56.076 6.96 56.144 ;
     RECT  6.984 56.076 7.056 56.144 ;
     RECT  7.08 56.076 7.152 56.144 ;
     RECT  7.176 56.076 7.248 56.144 ;
     RECT  7.272 56.076 7.344 56.144 ;
     RECT  7.368 56.076 7.44 56.144 ;
     RECT  7.464 56.076 7.536 56.144 ;
     RECT  7.56 56.076 7.632 56.144 ;
     RECT  7.656 56.076 7.728 56.144 ;
     RECT  7.752 56.076 7.824 56.144 ;
     RECT  7.848 56.076 7.92 56.144 ;
     RECT  7.944 56.076 8.016 56.144 ;
     RECT  8.04 56.076 8.112 56.144 ;
     RECT  8.136 56.076 8.208 56.144 ;
     RECT  8.232 56.076 8.304 56.144 ;
     RECT  8.328 56.076 9.168 56.144 ;
     RECT  9.192 56.076 9.264 56.144 ;
     RECT  9.288 56.076 9.36 56.144 ;
     RECT  9.384 56.076 9.456 56.144 ;
     RECT  9.48 56.076 9.552 56.144 ;
     RECT  9.576 56.076 9.648 56.144 ;
     RECT  9.672 56.076 9.744 56.144 ;
     RECT  9.768 56.076 9.84 56.144 ;
     RECT  9.864 56.076 9.936 56.144 ;
     RECT  9.96 56.076 10.032 56.144 ;
     RECT  10.056 56.076 10.128 56.144 ;
     RECT  10.152 56.076 10.224 56.144 ;
     RECT  10.248 56.076 10.32 56.144 ;
     RECT  10.344 56.076 10.416 56.144 ;
     RECT  10.44 56.076 10.512 56.144 ;
     RECT  10.536 56.076 10.608 56.144 ;
     RECT  10.632 56.076 10.704 56.144 ;
     RECT  10.728 56.076 10.8 56.144 ;
     RECT  10.824 56.076 10.896 56.144 ;
     RECT  10.92 56.076 10.992 56.144 ;
     RECT  11.016 56.076 11.088 56.144 ;
     RECT  11.112 56.076 11.184 56.144 ;
     RECT  11.208 56.076 11.28 56.144 ;
     RECT  11.304 56.076 11.376 56.144 ;
     RECT  11.4 56.076 11.472 56.144 ;
     RECT  11.496 56.076 11.568 56.144 ;
     RECT  11.592 56.076 11.664 56.144 ;
     RECT  11.688 56.076 11.76 56.144 ;
     RECT  11.784 56.076 11.856 56.144 ;
     RECT  11.88 56.076 11.952 56.144 ;
     RECT  11.976 56.076 12.048 56.144 ;
     RECT  12.072 56.076 12.144 56.144 ;
     RECT  12.168 56.076 12.24 56.144 ;
     RECT  12.264 56.076 12.336 56.144 ;
     RECT  12.36 56.076 12.432 56.144 ;
     RECT  12.456 56.076 12.528 56.144 ;
     RECT  12.552 56.076 12.624 56.144 ;
     RECT  12.648 56.076 12.72 56.144 ;
     RECT  12.744 56.076 12.816 56.144 ;
     RECT  12.84 56.076 12.912 56.144 ;
     RECT  12.936 56.076 13.008 56.144 ;
     RECT  13.032 56.076 13.104 56.144 ;
     RECT  13.128 56.076 13.2 56.144 ;
     RECT  13.224 56.076 13.296 56.144 ;
     RECT  13.32 56.076 13.392 56.144 ;
     RECT  13.416 56.076 13.488 56.144 ;
     RECT  13.512 56.076 13.584 56.144 ;
     RECT  13.608 56.076 13.68 56.144 ;
     RECT  13.704 56.076 13.776 56.144 ;
     RECT  13.8 56.076 13.872 56.144 ;
     RECT  13.896 56.076 13.968 56.144 ;
     RECT  13.992 56.076 14.064 56.144 ;
     RECT  14.088 56.076 14.16 56.144 ;
     RECT  14.184 56.076 14.256 56.144 ;
     RECT  14.28 56.076 14.352 56.144 ;
     RECT  14.376 56.076 14.448 56.144 ;
     RECT  14.472 56.076 14.544 56.144 ;
     RECT  14.568 56.076 14.64 56.144 ;
     RECT  14.664 56.076 14.736 56.144 ;
     RECT  14.76 56.076 14.832 56.144 ;
     RECT  14.856 56.076 14.928 56.144 ;
     RECT  14.952 56.076 15.024 56.144 ;
     RECT  15.048 56.076 15.12 56.144 ;
     RECT  15.144 56.076 15.216 56.144 ;
     RECT  15.24 56.076 15.312 56.144 ;
     RECT  15.336 56.076 15.408 56.144 ;
     RECT  15.432 56.076 15.504 56.144 ;
     RECT  15.528 56.076 15.6 56.144 ;
     RECT  15.624 56.076 15.696 56.144 ;
     RECT  15.72 56.076 15.792 56.144 ;
     RECT  15.816 56.076 15.888 56.144 ;
     RECT  15.912 56.076 15.984 56.144 ;
     RECT  16.008 56.076 16.08 56.144 ;
     RECT  16.104 56.076 16.176 56.144 ;
     RECT  16.2 56.076 16.272 56.144 ;
     RECT  16.296 56.076 16.368 56.144 ;
     RECT  16.392 56.076 16.464 56.144 ;
     RECT  16.488 56.076 16.56 56.144 ;
     RECT  16.584 56.076 16.656 56.144 ;
     RECT  16.68 56.076 16.752 56.144 ;
     RECT  16.776 56.076 16.848 56.144 ;
     RECT  16.872 56.076 16.944 56.144 ;
     RECT  16.968 56.076 17.04 56.144 ;
     RECT  17.064 56.076 17.136 56.144 ;
     RECT  17.16 56.076 17.232 56.144 ;
     RECT  17.256 56.076 17.328 56.144 ;
     RECT  17.352 56.076 17.424 56.144 ;
     RECT  17.448 56.076 17.52 56.144 ;
     RECT  17.544 56.076 17.616 56.144 ;
     RECT  17.64 56.076 17.712 56.144 ;
     RECT  17.736 56.076 17.808 56.144 ;
     RECT  17.832 56.076 17.904 56.144 ;
     RECT  17.928 56.076 18 56.144 ;
     RECT  18.024 56.076 18.096 56.144 ;
     RECT  18.12 56.076 18.192 56.144 ;
     RECT  18.216 56.076 18.288 56.144 ;
     RECT  18.312 56.076 18.384 56.144 ;
     RECT  18.408 56.076 18.48 56.144 ;
     RECT  18.504 56.076 18.576 56.144 ;
     RECT  18.6 56.076 18.672 56.144 ;
     RECT  18.696 56.076 18.768 56.144 ;
     RECT  18.792 56.076 18.864 56.144 ;
     RECT  18.888 56.076 18.96 56.144 ;
     RECT  18.984 56.076 19.056 56.144 ;
     RECT  19.08 56.076 19.152 56.144 ;
     RECT  19.176 56.076 19.248 56.144 ;
     RECT  19.272 56.076 19.344 56.144 ;
     RECT  19.368 56.076 19.44 56.144 ;
     RECT  19.464 56.076 19.536 56.144 ;
     RECT  19.56 56.076 19.632 56.144 ;
     RECT  19.656 56.076 19.728 56.144 ;
     RECT  19.752 56.076 19.824 56.144 ;
     RECT  19.848 56.076 19.92 56.144 ;
     RECT  19.944 56.076 20.016 56.144 ;
     RECT  20.04 56.076 20.112 56.144 ;
     RECT  20.136 56.076 20.208 56.144 ;
     RECT  20.232 56.076 20.304 56.144 ;
     RECT  20.328 56.076 20.4 56.144 ;
     RECT  20.424 56.076 20.496 56.144 ;
     RECT  20.52 56.076 20.592 56.144 ;
     RECT  20.616 56.076 20.688 56.144 ;
     RECT  20.712 56.076 20.784 56.144 ;
     RECT  20.808 56.076 20.88 56.144 ;
     RECT  20.904 56.076 20.976 56.144 ;
     RECT  21 56.076 21.072 56.144 ;
     RECT  21.096 56.076 21.168 56.144 ;
     RECT  21.192 56.076 21.264 56.144 ;
     RECT  21.288 56.076 21.36 56.144 ;
     RECT  21.384 56.076 21.456 56.144 ;
     RECT  21.48 56.076 21.552 56.144 ;
     RECT  21.576 56.076 21.648 56.144 ;
     RECT  21.672 56.076 21.744 56.144 ;
     RECT  21.768 56.076 21.84 56.144 ;
     RECT  21.864 56.076 21.936 56.144 ;
     RECT  21.96 56.076 22.032 56.144 ;
     RECT  22.056 56.076 22.128 56.144 ;
     RECT  22.152 56.076 22.224 56.144 ;
     RECT  22.248 56.076 22.32 56.144 ;
     RECT  22.344 56.076 22.416 56.144 ;
     RECT  22.44 56.076 22.512 56.144 ;
     RECT  22.536 56.076 22.608 56.144 ;
     RECT  22.632 56.076 22.704 56.144 ;
     RECT  22.728 56.076 22.8 56.144 ;
     RECT  22.824 56.076 22.896 56.144 ;
     RECT  22.92 56.076 22.992 56.144 ;
     RECT  23.016 56.076 23.088 56.144 ;
     RECT  23.112 56.076 23.184 56.144 ;
     RECT  23.208 56.076 23.28 56.144 ;
     RECT  23.304 56.076 23.376 56.144 ;
     RECT  23.4 56.076 23.472 56.144 ;
     RECT  23.496 56.076 23.568 56.144 ;
     RECT  23.592 56.076 23.664 56.144 ;
     RECT  59.088 55.285 69 56.076 ;
     RECT  59.112 56.076 59.184 56.144 ;
     RECT  59.208 56.076 59.28 56.144 ;
     RECT  59.304 56.076 59.376 56.144 ;
     RECT  59.4 56.076 59.472 56.144 ;
     RECT  59.496 56.076 59.568 56.144 ;
     RECT  59.592 56.076 59.664 56.144 ;
     RECT  59.688 56.076 59.76 56.144 ;
     RECT  59.784 56.076 59.856 56.144 ;
     RECT  59.88 56.076 59.952 56.144 ;
     RECT  59.976 56.076 60.048 56.144 ;
     RECT  60.072 56.076 60.144 56.144 ;
     RECT  60.168 56.076 60.24 56.144 ;
     RECT  60.264 56.076 60.336 56.144 ;
     RECT  60.36 56.076 60.432 56.144 ;
     RECT  60.456 56.076 60.528 56.144 ;
     RECT  60.552 56.076 60.624 56.144 ;
     RECT  60.648 56.076 60.72 56.144 ;
     RECT  60.744 56.076 60.816 56.144 ;
     RECT  60.84 56.076 60.912 56.144 ;
     RECT  60.936 56.076 61.008 56.144 ;
     RECT  61.032 56.076 61.104 56.144 ;
     RECT  61.128 56.076 61.2 56.144 ;
     RECT  61.224 56.076 61.296 56.144 ;
     RECT  61.32 56.076 61.392 56.144 ;
     RECT  61.416 56.076 61.488 56.144 ;
     RECT  61.512 56.076 61.584 56.144 ;
     RECT  61.608 56.076 61.68 56.144 ;
     RECT  61.704 56.076 61.776 56.144 ;
     RECT  61.8 56.076 61.872 56.144 ;
     RECT  61.896 56.076 61.968 56.144 ;
     RECT  61.992 56.076 62.064 56.144 ;
     RECT  62.088 56.076 62.928 56.144 ;
     RECT  62.952 56.076 63.024 56.144 ;
     RECT  63.048 56.076 63.12 56.144 ;
     RECT  63.144 56.076 63.216 56.144 ;
     RECT  63.24 56.076 63.312 56.144 ;
     RECT  63.336 56.076 63.408 56.144 ;
     RECT  63.432 56.076 63.504 56.144 ;
     RECT  63.528 56.076 63.6 56.144 ;
     RECT  63.624 56.076 63.696 56.144 ;
     RECT  63.72 56.076 63.792 56.144 ;
     RECT  63.816 56.076 63.888 56.144 ;
     RECT  63.912 56.076 63.984 56.144 ;
     RECT  64.008 56.076 64.08 56.144 ;
     RECT  64.104 56.076 64.176 56.144 ;
     RECT  64.2 56.076 64.272 56.144 ;
     RECT  64.296 56.076 64.368 56.144 ;
     RECT  64.392 56.076 64.464 56.144 ;
     RECT  64.488 56.076 64.56 56.144 ;
     RECT  64.584 56.076 64.656 56.144 ;
     RECT  64.68 56.076 64.752 56.144 ;
     RECT  64.776 56.076 64.848 56.144 ;
     RECT  64.872 56.076 64.944 56.144 ;
     RECT  64.968 56.076 65.04 56.144 ;
     RECT  65.064 56.076 65.136 56.144 ;
     RECT  65.16 56.076 65.232 56.144 ;
     RECT  65.256 56.076 65.328 56.144 ;
     RECT  65.352 56.076 65.424 56.144 ;
     RECT  65.448 56.076 65.52 56.144 ;
     RECT  65.544 56.076 65.616 56.144 ;
     RECT  65.64 56.076 65.712 56.144 ;
     RECT  65.736 56.076 65.808 56.144 ;
     RECT  65.832 56.076 65.904 56.144 ;
     RECT  65.928 56.076 66 56.144 ;
     RECT  66.024 56.076 66.096 56.144 ;
     RECT  66.12 56.076 66.192 56.144 ;
     RECT  66.216 56.076 66.288 56.144 ;
     RECT  66.312 56.076 66.384 56.144 ;
     RECT  66.408 56.076 66.48 56.144 ;
     RECT  66.504 56.076 66.576 56.144 ;
     RECT  66.6 56.076 66.672 56.144 ;
     RECT  66.696 56.076 66.768 56.144 ;
     RECT  66.792 56.076 66.864 56.144 ;
     RECT  66.888 56.076 66.96 56.144 ;
     RECT  66.984 56.076 67.056 56.144 ;
     RECT  67.08 56.076 67.152 56.144 ;
     RECT  67.176 56.076 67.248 56.144 ;
     RECT  67.272 56.076 67.344 56.144 ;
     RECT  67.368 56.076 67.44 56.144 ;
     RECT  67.464 56.076 67.536 56.144 ;
     RECT  67.56 56.076 67.632 56.144 ;
     RECT  67.656 56.076 67.728 56.144 ;
     RECT  67.752 56.076 67.824 56.144 ;
     RECT  67.848 56.076 67.92 56.144 ;
     RECT  67.944 56.076 68.016 56.144 ;
     RECT  68.04 56.076 68.112 56.144 ;
     RECT  68.136 56.076 68.208 56.144 ;
     RECT  68.232 56.076 68.304 56.144 ;
     RECT  68.328 56.076 68.4 56.144 ;
     RECT  68.424 56.076 68.496 56.144 ;
     RECT  68.52 56.076 68.592 56.144 ;
     RECT  68.616 56.076 68.688 56.144 ;
     RECT  68.712 56.076 68.784 56.144 ;
     RECT  68.808 56.076 68.88 56.144 ;
     RECT  68.904 56.076 68.976 56.144 ;
     RECT  72.144 53.603 75.144 56.076 ;
     RECT  72.168 56.076 72.24 56.144 ;
     RECT  72.264 56.076 72.336 56.144 ;
     RECT  72.36 56.076 72.432 56.144 ;
     RECT  72.456 56.076 72.528 56.144 ;
     RECT  72.552 56.076 72.624 56.144 ;
     RECT  72.648 56.076 72.72 56.144 ;
     RECT  72.744 56.076 72.816 56.144 ;
     RECT  72.84 56.076 72.912 56.144 ;
     RECT  72.936 56.076 73.008 56.144 ;
     RECT  73.032 56.076 73.104 56.144 ;
     RECT  73.128 56.076 73.2 56.144 ;
     RECT  73.224 56.076 73.296 56.144 ;
     RECT  73.32 56.076 73.392 56.144 ;
     RECT  73.416 56.076 73.488 56.144 ;
     RECT  73.512 56.076 73.584 56.144 ;
     RECT  73.608 56.076 73.68 56.144 ;
     RECT  73.704 56.076 73.776 56.144 ;
     RECT  73.8 56.076 73.872 56.144 ;
     RECT  73.896 56.076 73.968 56.144 ;
     RECT  73.992 56.076 74.064 56.144 ;
     RECT  74.088 56.076 74.16 56.144 ;
     RECT  74.184 56.076 74.256 56.144 ;
     RECT  74.28 56.076 74.352 56.144 ;
     RECT  74.376 56.076 74.448 56.144 ;
     RECT  74.472 56.076 74.544 56.144 ;
     RECT  74.568 56.076 74.64 56.144 ;
     RECT  74.664 56.076 74.736 56.144 ;
     RECT  74.76 56.076 74.832 56.144 ;
     RECT  74.856 56.076 74.928 56.144 ;
     RECT  74.952 56.076 75.024 56.144 ;
     RECT  75.048 56.076 75.12 56.144 ;
     RECT  13.392 1.139 13.488 2.137 ;
     RECT  58.824 2.339 60.24 2.915 ;
     RECT  60.264 2.339 61.296 5.365 ;
     RECT  21.096 2.629 22.416 2.963 ;
     RECT  42.456 2.677 43.584 2.867 ;
     RECT  22.632 2.821 24 4.739 ;
     RECT  42.72 2.867 43.584 3.061 ;
     RECT  58.728 2.915 60.24 4.019 ;
     RECT  21.096 2.963 22.608 3.635 ;
     RECT  38.04 3.157 39.456 3.971 ;
     RECT  42.744 3.347 43.608 3.925 ;
     RECT  24.6 3.397 25.632 3.637 ;
     RECT  42.744 3.925 43.776 4.931 ;
     RECT  43.8 3.925 45.072 4.549 ;
     RECT  38.04 3.971 38.088 4.933 ;
     RECT  53.04 4.019 53.064 4.501 ;
     RECT  37.056 4.067 37.584 5.221 ;
     RECT  26.952 4.309 28.368 5.509 ;
     RECT  51.816 4.501 53.064 5.125 ;
     RECT  43.8 4.549 45.024 4.691 ;
     RECT  5.664 4.595 5.688 5.077 ;
     RECT  43.8 4.691 45.072 4.931 ;
     RECT  44.4 4.931 45.072 5.845 ;
     RECT  5.16 5.077 5.688 5.317 ;
     RECT  51.816 5.125 53.808 5.269 ;
     RECT  55.776 5.171 56.4 6.229 ;
     RECT  47.976 5.269 49.008 5.365 ;
     RECT  49.032 5.269 50.064 5.555 ;
     RECT  52.536 5.269 53.808 5.555 ;
     RECT  5.16 5.317 6.48 5.843 ;
     RECT  6.504 5.317 7.8 7.043 ;
     RECT  47.976 5.507 49.008 5.555 ;
     RECT  41.112 5.509 42.24 5.747 ;
     RECT  49.584 5.555 50.064 6.421 ;
     RECT  14.232 5.747 15.36 5.843 ;
     RECT  40.512 5.747 42.24 6.805 ;
     RECT  60.24 5.747 60.96 6.133 ;
     RECT  26.568 5.795 27.792 7.333 ;
     RECT  14.232 5.843 15.384 6.133 ;
     RECT  44.4 5.845 44.592 5.989 ;
     RECT  44.4 5.989 44.496 6.373 ;
     RECT  73.32 6.083 73.368 7.333 ;
     RECT  14.232 6.133 16.512 6.853 ;
     RECT  59.688 6.133 60.96 6.179 ;
     RECT  16.536 6.277 17.664 7.379 ;
     RECT  30.264 6.421 31.296 6.563 ;
     RECT  31.32 6.421 32.448 6.853 ;
     RECT  49.584 6.421 49.632 6.805 ;
     RECT  29.832 6.563 31.296 7.043 ;
     RECT  33.672 6.661 34.8 6.949 ;
     RECT  14.232 6.853 16.368 6.901 ;
     RECT  31.368 6.853 32.448 7.427 ;
     RECT  14.232 6.901 16.08 7.141 ;
     RECT  38.088 6.901 39.168 7.283 ;
     RECT  39.192 6.901 40.2 7.045 ;
     RECT  55.176 6.995 56.4 9.013 ;
     RECT  14.232 7.141 15.648 7.331 ;
     RECT  38.088 7.283 38.184 7.957 ;
     RECT  31.32 7.427 32.448 8.147 ;
     RECT  51.816 7.427 51.864 8.245 ;
     RECT  35.544 7.957 36.768 8.149 ;
     RECT  36.792 7.957 37.92 8.245 ;
     RECT  32.016 8.147 32.448 9.541 ;
     RECT  60.456 8.197 61.68 8.339 ;
     RECT  36.888 8.245 37.92 8.389 ;
     RECT  51.816 8.245 53.04 8.629 ;
     RECT  35.544 8.291 36.864 8.435 ;
     RECT  61.056 8.339 61.68 9.013 ;
     RECT  57.672 8.389 58.992 9.349 ;
     RECT  71.592 8.389 72.6 11.939 ;
     RECT  35.544 8.435 36.96 8.483 ;
     RECT  35.352 8.483 36.96 8.531 ;
     RECT  35.352 8.531 37.728 8.627 ;
     RECT  33.432 8.579 34.8 11.269 ;
     RECT  35.304 8.627 37.728 8.723 ;
     RECT  35.256 8.723 37.728 9.541 ;
     RECT  49.008 8.771 50.208 8.963 ;
     RECT  43.032 8.773 44.16 10.549 ;
     RECT  51.816 8.915 52.944 12.035 ;
     RECT  49.008 8.963 49.032 9.973 ;
     RECT  65.712 9.011 66.384 9.397 ;
     RECT  55.176 9.013 56.304 9.155 ;
     RECT  13.512 9.059 14.832 13.573 ;
     RECT  38.04 9.107 38.184 9.155 ;
     RECT  37.992 9.155 38.184 9.781 ;
     RECT  53.256 9.157 54.72 9.299 ;
     RECT  19.032 9.253 20.448 9.349 ;
     RECT  19.08 9.349 20.448 10.117 ;
     RECT  65.256 9.397 66.384 10.931 ;
     RECT  35.256 9.541 36.864 9.685 ;
     RECT  3.672 9.637 4.896 11.027 ;
     RECT  35.4 9.685 36.864 9.973 ;
     RECT  29.976 9.781 31.392 10.451 ;
     RECT  37.992 9.781 39.264 10.019 ;
     RECT  35.88 9.973 36.864 10.163 ;
     RECT  37.752 10.019 39.264 11.941 ;
     RECT  26.568 10.067 27.648 10.883 ;
     RECT  49.008 10.115 49.032 11.365 ;
     RECT  14.856 10.117 16.368 11.461 ;
     RECT  19.08 10.117 20.112 11.701 ;
     RECT  35.88 10.163 37.2 11.365 ;
     RECT  29.976 10.451 32.016 11.797 ;
     RECT  57.24 10.499 58.464 10.739 ;
     RECT  59.016 10.549 60.384 11.171 ;
     RECT  56.856 10.739 58.464 10.931 ;
     RECT  26.568 10.883 27.744 11.747 ;
     RECT  56.856 10.931 57.048 10.979 ;
     RECT  65.232 10.931 66.384 11.269 ;
     RECT  56.712 10.979 57.048 12.133 ;
     RECT  41.448 11.075 42.432 12.421 ;
     RECT  67.512 11.123 68.784 12.181 ;
     RECT  59.016 11.171 61.344 11.365 ;
     RECT  33.528 11.269 34.8 11.797 ;
     RECT  65.208 11.269 66.384 13.669 ;
     RECT  35.88 11.365 36.96 11.555 ;
     RECT  48.984 11.365 49.032 11.461 ;
     RECT  59.016 11.365 60.048 11.557 ;
     RECT  60.264 11.365 61.344 11.603 ;
     RECT  14.856 11.461 16.32 11.891 ;
     RECT  35.88 11.555 37.056 11.747 ;
     RECT  59.016 11.699 60.048 11.891 ;
     RECT  26.568 11.747 27.84 12.035 ;
     RECT  35.88 11.747 37.68 12.805 ;
     RECT  29.976 11.797 31.008 12.085 ;
     RECT  8.112 11.845 9.504 12.035 ;
     RECT  9.528 11.845 10.512 12.035 ;
     RECT  14.856 11.891 16.632 11.941 ;
     RECT  70.968 11.939 72.6 12.181 ;
     RECT  14.856 11.941 15.936 13.139 ;
     RECT  15.96 11.941 16.632 12.085 ;
     RECT  37.752 11.941 39.024 12.997 ;
     RECT  26.568 12.035 27.984 12.131 ;
     RECT  51.432 12.035 52.944 13.763 ;
     RECT  15.96 12.085 16.944 12.419 ;
     RECT  16.968 12.085 18.432 12.419 ;
     RECT  70.968 12.181 72.096 13.187 ;
     RECT  56.712 12.371 57 13.621 ;
     RECT  49.512 12.373 50.736 12.901 ;
     RECT  63.816 12.373 65.184 13.043 ;
     RECT  15.96 12.419 18.432 12.949 ;
     RECT  43.944 12.419 45.024 12.803 ;
     RECT  48.912 12.467 48.96 12.469 ;
     RECT  47.784 12.469 48.96 13.957 ;
     RECT  41.448 12.611 42.432 14.197 ;
     RECT  46.776 12.611 47.76 13.283 ;
     RECT  53.976 12.613 55.392 13.043 ;
     RECT  55.416 12.613 56.4 13.043 ;
     RECT  43.944 12.803 45.072 13.763 ;
     RECT  35.88 12.805 36.864 13.669 ;
     RECT  49.512 12.901 50.688 13.189 ;
     RECT  15.96 12.949 18.384 13.139 ;
     RECT  28.176 12.995 28.416 13.235 ;
     RECT  37.752 12.997 38.88 13.381 ;
     RECT  53.976 13.043 54.12 13.573 ;
     RECT  55.92 13.043 56.4 13.765 ;
     RECT  64.704 13.043 65.184 14.197 ;
     RECT  16.992 13.139 18.384 13.187 ;
     RECT  16.992 13.187 18.48 13.861 ;
     RECT  18.912 13.187 19.968 13.475 ;
     RECT  28.176 13.235 28.464 13.667 ;
     RECT  46.728 13.283 47.76 13.571 ;
     RECT  37.896 13.381 38.88 13.763 ;
     RECT  18.912 13.475 20.112 18.275 ;
     RECT  46.68 13.571 47.76 15.491 ;
     RECT  13.8 13.573 14.832 15.443 ;
     RECT  28.176 13.667 28.896 14.389 ;
     RECT  52.968 13.667 53.952 13.763 ;
     RECT  37.752 13.763 38.88 14.003 ;
     RECT  43.944 13.763 45.168 14.819 ;
     RECT  17.016 13.861 18.48 14.725 ;
     RECT  35.304 13.955 36.672 16.309 ;
     RECT  47.976 13.957 48.96 14.147 ;
     RECT  30.072 14.099 31.296 14.435 ;
     RECT  47.784 14.147 48.96 14.341 ;
     RECT  69.72 14.197 70.944 14.867 ;
     RECT  40.824 14.243 42.24 14.675 ;
     RECT  42.456 14.243 43.92 15.251 ;
     RECT  56.712 14.243 57 14.533 ;
     RECT  65.208 14.243 66.384 16.019 ;
     RECT  26.376 14.291 26.568 14.389 ;
     RECT  49.752 14.291 51 15.011 ;
     RECT  47.784 14.341 48.816 14.819 ;
     RECT  26.376 14.389 27.456 14.723 ;
     RECT  27.48 14.389 28.896 14.723 ;
     RECT  30.072 14.435 31.392 14.723 ;
     RECT  56.712 14.533 58.176 15.443 ;
     RECT  40.824 14.675 42.432 15.445 ;
     RECT  30.072 14.723 31.536 14.819 ;
     RECT  43.944 14.819 45.456 15.205 ;
     RECT  47.784 14.819 48.96 16.549 ;
     RECT  70.704 14.867 70.728 16.309 ;
     RECT  22.752 15.011 22.896 15.877 ;
     RECT  44.472 15.205 45.456 16.885 ;
     RECT  42.456 15.251 44.448 16.069 ;
     RECT  20.424 15.395 20.472 15.877 ;
     RECT  13.8 15.443 14.328 15.445 ;
     RECT  11.832 15.445 13.2 16.019 ;
     RECT  41.016 15.445 42.432 16.069 ;
     RECT  46.488 15.491 47.76 17.555 ;
     RECT  37.752 15.637 38.928 15.685 ;
     RECT  17.16 15.731 18.6 17.075 ;
     RECT  38.664 15.827 39.792 16.981 ;
     RECT  61.68 15.827 61.8 15.925 ;
     RECT  20.424 15.877 21.744 16.357 ;
     RECT  21.768 15.877 22.896 17.075 ;
     RECT  29.712 15.923 29.832 17.029 ;
     RECT  60.408 15.925 61.8 16.789 ;
     RECT  74.088 15.925 75.216 16.547 ;
     RECT  13.104 16.019 13.2 17.173 ;
     RECT  41.112 16.069 42.432 16.453 ;
     RECT  42.6 16.069 44.448 16.211 ;
     RECT  42.456 16.211 44.448 16.453 ;
     RECT  58.68 16.261 59.712 16.403 ;
     RECT  41.112 16.453 42.24 16.931 ;
     RECT  42.456 16.453 43.872 18.133 ;
     RECT  63.672 16.597 65.184 18.515 ;
     RECT  51.432 16.645 52.656 16.883 ;
     RECT  51.432 16.883 52.8 17.749 ;
     RECT  41.112 16.931 42.432 17.317 ;
     RECT  38.664 16.981 39.696 17.509 ;
     RECT  29.712 17.029 30.72 17.171 ;
     RECT  21.096 17.075 21.144 17.699 ;
     RECT  22.8 17.075 22.896 18.421 ;
     RECT  32.328 17.123 33.408 17.651 ;
     RECT  29.712 17.171 31.008 18.179 ;
     RECT  35.976 17.219 37.008 18.179 ;
     RECT  41.304 17.317 42.432 20.003 ;
     RECT  25.8 17.555 27.12 17.651 ;
     RECT  32.136 17.651 33.408 18.805 ;
     RECT  43.896 17.651 44.88 18.179 ;
     RECT  71.256 17.653 72.6 19.379 ;
     RECT  20.136 17.699 21.144 18.275 ;
     RECT  51.624 17.749 52.8 19.285 ;
     RECT  33.672 17.795 34.8 18.131 ;
     RECT  33.432 18.131 34.8 19.043 ;
     RECT  37.704 18.131 38.736 18.275 ;
     RECT  42.84 18.133 43.872 18.179 ;
     RECT  29.712 18.179 31.728 19.091 ;
     RECT  35.112 18.179 37.008 18.659 ;
     RECT  52.824 18.179 53.808 19.811 ;
     RECT  60.384 18.179 61.008 18.181 ;
     RECT  59.784 18.181 61.008 18.803 ;
     RECT  21.12 18.275 21.144 18.325 ;
     RECT  37.704 18.275 38.088 19.333 ;
     RECT  59.664 18.371 59.76 18.805 ;
     RECT  63.792 18.515 65.184 18.757 ;
     RECT  35.112 18.659 35.496 19.621 ;
     RECT  63.816 18.757 65.184 19.859 ;
     RECT  67.608 18.757 69.072 19.955 ;
     RECT  59.784 18.803 59.88 19.909 ;
     RECT  58.728 18.805 59.76 21.155 ;
     RECT  29.712 19.091 32.112 19.141 ;
     RECT  30.216 19.141 32.112 20.341 ;
     RECT  44.88 19.571 45.024 20.485 ;
     RECT  52.728 19.811 53.808 22.547 ;
     RECT  63.792 19.859 65.184 19.861 ;
     RECT  63.792 19.861 63.936 20.869 ;
     RECT  63.96 19.861 65.184 21.925 ;
     RECT  14.232 20.101 15.648 20.149 ;
     RECT  30.84 20.341 32.112 20.579 ;
     RECT  78.312 20.435 78.408 21.637 ;
     RECT  43.896 20.485 45.024 21.011 ;
     RECT  30.84 20.579 32.136 20.965 ;
     RECT  25.128 20.627 26.208 22.259 ;
     RECT  62.376 20.869 63.936 21.205 ;
     RECT  56.712 20.915 57 22.021 ;
     RECT  31.944 20.965 32.136 21.109 ;
     RECT  43.896 21.011 43.944 22.163 ;
     RECT  74.952 21.011 75.816 22.117 ;
     RECT  71.256 21.061 72.48 21.107 ;
     RECT  71.256 21.107 72.6 21.683 ;
     RECT  31.944 21.109 32.976 22.259 ;
     RECT  29.832 21.155 30.816 21.203 ;
     RECT  51.312 21.155 52.368 22.547 ;
     RECT  62.664 21.205 63.936 21.253 ;
     RECT  62.76 21.253 63.936 21.971 ;
     RECT  8.112 21.541 9.12 21.827 ;
     RECT  37.68 21.587 37.872 21.973 ;
     RECT  64.104 21.925 65.184 22.451 ;
     RECT  62.76 21.971 64.08 23.317 ;
     RECT  35.112 21.973 36.432 22.259 ;
     RECT  36.456 21.973 37.872 22.259 ;
     RECT  38.328 22.069 39.696 22.549 ;
     RECT  60.408 22.117 61.68 22.691 ;
     RECT  74.952 22.117 76.224 22.787 ;
     RECT  43.92 22.163 43.944 22.165 ;
     RECT  25.128 22.259 25.8 22.835 ;
     RECT  31.608 22.259 32.976 22.499 ;
     RECT  37.2 22.259 37.872 22.741 ;
     RECT  46.056 22.259 46.2 23.317 ;
     RECT  64.104 22.451 65.616 22.835 ;
     RECT  31.584 22.499 32.976 23.029 ;
     RECT  51.312 22.547 52.704 23.315 ;
     RECT  59.784 22.691 61.68 22.741 ;
     RECT  59.784 22.741 60.864 23.555 ;
     RECT  69.432 22.741 70.416 23.363 ;
     RECT  38.088 22.787 39.264 23.507 ;
     RECT  73.848 22.787 74.928 23.219 ;
     RECT  74.952 22.787 75.24 23.173 ;
     RECT  24.312 22.835 25.8 23.077 ;
     RECT  64.104 22.835 64.488 23.893 ;
     RECT  18.912 22.979 19.032 24.277 ;
     RECT  13.056 23.027 13.2 23.269 ;
     RECT  31.56 23.029 32.976 24.085 ;
     RECT  24.312 23.077 25.776 25.621 ;
     RECT  43.944 23.077 44.976 23.555 ;
     RECT  29.712 23.123 29.832 23.269 ;
     RECT  73.848 23.219 75.216 23.555 ;
     RECT  12.024 23.269 13.2 23.987 ;
     RECT  29.712 23.269 30.912 26.053 ;
     RECT  46.824 23.317 47.808 23.701 ;
     RECT  62.76 23.317 63.936 23.891 ;
     RECT  69.432 23.363 70.656 23.939 ;
     RECT  31.608 24.085 32.976 26.869 ;
     RECT  78.312 24.229 79.584 25.573 ;
     RECT  16.92 24.469 18.288 24.517 ;
     RECT  16.92 24.517 18.048 24.659 ;
     RECT  17.952 24.659 18.048 26.101 ;
     RECT  76.92 24.901 78 24.997 ;
     RECT  51.312 25.045 52.464 27.395 ;
     RECT  21.24 25.573 22.752 26.915 ;
     RECT  22.776 25.573 24 26.915 ;
     RECT  47.016 25.667 48.432 27.059 ;
     RECT  24.984 25.715 25.8 26.579 ;
     RECT  39 25.715 40.2 26.867 ;
     RECT  56.712 25.715 56.808 27.109 ;
     RECT  76.896 25.715 77.664 26.243 ;
     RECT  67.512 25.717 68.928 27.059 ;
     RECT  62.112 25.765 63.264 25.907 ;
     RECT  45.912 25.811 46.992 27.491 ;
     RECT  62.112 25.907 63.84 26.773 ;
     RECT  29.832 26.053 30.912 26.915 ;
     RECT  50.736 26.243 50.88 27.637 ;
     RECT  76.896 26.243 77.856 26.581 ;
     RECT  24.552 26.579 25.8 26.917 ;
     RECT  76.392 26.581 77.856 26.771 ;
     RECT  62.808 26.773 63.84 27.347 ;
     RECT  21.24 26.915 24 27.061 ;
     RECT  24.552 26.917 25.92 27.107 ;
     RECT  27.912 26.917 29.088 27.155 ;
     RECT  31.608 27.011 32.976 29.795 ;
     RECT  54.792 27.013 56.208 27.875 ;
     RECT  47.016 27.059 48.168 27.445 ;
     RECT  21.384 27.061 24 27.157 ;
     RECT  21.264 27.107 21.36 28.501 ;
     RECT  21.384 27.157 22.704 35.701 ;
     RECT  22.728 27.157 24 37.765 ;
     RECT  62.808 27.347 64.176 27.395 ;
     RECT  51.312 27.395 52.488 27.877 ;
     RECT  47.208 27.445 48.168 27.829 ;
     RECT  45.912 27.491 47.184 28.163 ;
     RECT  40.512 27.635 40.632 28.981 ;
     RECT  54.768 27.875 56.208 28.453 ;
     RECT  52.248 27.877 52.488 28.453 ;
     RECT  35.112 27.973 36.288 28.259 ;
     RECT  45.912 28.163 46.152 28.453 ;
     RECT  5.4 28.165 6.816 28.499 ;
     RECT  35.112 28.259 35.256 28.405 ;
     RECT  52.248 28.453 53.568 28.549 ;
     RECT  53.592 28.453 56.208 28.501 ;
     RECT  53.88 28.501 56.208 28.981 ;
     RECT  52.248 28.691 53.568 30.227 ;
     RECT  24.408 28.789 25.44 29.363 ;
     RECT  21.12 28.883 21.216 29.075 ;
     RECT  53.88 28.981 55.872 29.027 ;
     RECT  53.592 29.027 55.872 29.029 ;
     RECT  9.912 29.029 10.992 29.795 ;
     RECT  53.592 29.029 54.672 29.171 ;
     RECT  54.696 29.029 55.872 29.171 ;
     RECT  21.12 29.075 21.264 29.653 ;
     RECT  26.136 29.125 27.12 29.459 ;
     RECT  13.104 29.267 13.2 30.613 ;
     RECT  20.04 29.653 21.264 30.805 ;
     RECT  52.248 30.227 52.728 31.285 ;
     RECT  40.512 30.275 40.632 31.237 ;
     RECT  77.904 30.275 78 30.661 ;
     RECT  76.92 30.661 78 32.291 ;
     RECT  66.072 30.709 67.2 32.243 ;
     RECT  19.464 30.851 20.544 30.947 ;
     RECT  78.312 30.899 79.632 32.531 ;
     RECT  19.464 30.947 21.264 32.005 ;
     RECT  13.104 31.043 13.2 32.197 ;
     RECT  50.88 31.187 51 32.149 ;
     RECT  40.512 31.237 41.52 32.963 ;
     RECT  15.864 31.285 17.04 31.669 ;
     RECT  24.408 31.285 25.68 33.589 ;
     RECT  35.256 31.573 36.72 32.195 ;
     RECT  52.248 31.619 52.728 32.581 ;
     RECT  15.864 31.669 16.944 33.107 ;
     RECT  13.656 32.005 15.168 33.013 ;
     RECT  19.464 32.005 20.448 33.347 ;
     RECT  41.544 32.053 42.576 32.771 ;
     RECT  49.752 32.149 51 32.629 ;
     RECT  35.256 32.195 36.696 32.485 ;
     RECT  11.928 32.197 13.2 33.779 ;
     RECT  66.72 32.243 67.2 33.397 ;
     RECT  76.392 32.291 78 32.579 ;
     RECT  35.256 32.485 36.432 34.453 ;
     RECT  36.456 32.485 36.696 33.589 ;
     RECT  77.904 32.579 78 33.205 ;
     RECT  42.6 32.725 43.728 32.771 ;
     RECT  52.248 32.771 53.064 32.821 ;
     RECT  29.832 32.773 31.056 32.869 ;
     RECT  52.248 32.821 53.856 33.011 ;
     RECT  59.736 32.869 60.864 33.635 ;
     RECT  52.248 33.011 53.88 33.925 ;
     RECT  13.656 33.013 14.64 33.827 ;
     RECT  43.752 33.061 45.024 33.203 ;
     RECT  15.864 33.107 17.808 34.165 ;
     RECT  25.704 33.445 26.784 34.643 ;
     RECT  24.504 33.589 25.68 36.421 ;
     RECT  74.664 33.589 76.128 34.259 ;
     RECT  13.656 33.827 15.168 34.117 ;
     RECT  52.248 33.925 53.76 34.693 ;
     RECT  53.784 33.925 53.88 34.069 ;
     RECT  53.784 34.069 54.912 35.269 ;
     RECT  54.936 34.069 56.4 36.947 ;
     RECT  13.896 34.117 15.168 35.171 ;
     RECT  15.864 34.165 17.376 35.699 ;
     RECT  74.688 34.259 76.128 34.597 ;
     RECT  35.4 34.453 36.432 34.547 ;
     RECT  35.4 34.547 36.672 34.691 ;
     RECT  74.712 34.597 76.128 34.787 ;
     RECT  25.704 34.643 25.944 35.893 ;
     RECT  35.256 34.691 36.672 36.085 ;
     RECT  52.248 34.693 53.664 36.901 ;
     RECT  62.112 34.741 63.36 35.413 ;
     RECT  64.2 34.741 65.376 35.317 ;
     RECT  75.84 34.787 76.128 35.941 ;
     RECT  6.912 34.883 7.104 35.941 ;
     RECT  72.048 34.931 72.6 35.941 ;
     RECT  13.656 35.171 15.168 35.219 ;
     RECT  59.736 35.269 61.056 35.891 ;
     RECT  36.696 35.317 37.68 36.755 ;
     RECT  76.152 35.317 77.376 35.939 ;
     RECT  63.384 35.363 64.416 36.035 ;
     RECT  44.472 35.509 45.6 35.651 ;
     RECT  62.112 35.651 63.36 36.035 ;
     RECT  59.736 35.891 61.8 36.901 ;
     RECT  70.68 35.941 72.6 36.229 ;
     RECT  53.688 35.987 54.912 36.947 ;
     RECT  70.272 35.987 70.656 36.229 ;
     RECT  69.24 36.229 70.656 36.421 ;
     RECT  70.68 36.229 71.856 36.515 ;
     RECT  69.288 36.421 70.656 36.515 ;
     RECT  71.808 36.515 71.856 36.851 ;
     RECT  67.512 36.803 68.64 39.637 ;
     RECT  71.808 36.851 72.288 37.957 ;
     RECT  46.2 36.901 47.664 37.429 ;
     RECT  52.248 36.901 53.568 37.765 ;
     RECT  60.456 36.901 61.8 37.859 ;
     RECT  38.856 36.949 40.08 37.043 ;
     RECT  38.856 37.043 40.2 37.091 ;
     RECT  50.112 37.091 51 38.197 ;
     RECT  46.296 37.429 47.664 38.003 ;
     RECT  27.96 37.573 28.992 37.669 ;
     RECT  22.824 37.765 24 38.099 ;
     RECT  25.944 37.813 27.024 37.955 ;
     RECT  59.736 37.859 61.8 38.533 ;
     RECT  68.664 38.003 69.24 39.157 ;
     RECT  22.728 38.099 24 39.541 ;
     RECT  48.168 38.197 49.584 38.341 ;
     RECT  49.608 38.197 51 40.019 ;
     RECT  67.056 38.339 67.2 39.301 ;
     RECT  48.408 38.341 49.584 38.819 ;
     RECT  13.656 38.533 14.976 39.587 ;
     RECT  58.536 38.533 59.568 39.635 ;
     RECT  59.736 38.533 61.056 39.109 ;
     RECT  5.544 38.629 6.816 38.771 ;
     RECT  53.688 38.725 54.768 40.019 ;
     RECT  72.912 38.725 74.304 39.011 ;
     RECT  59.784 39.109 61.056 39.923 ;
     RECT  35.352 39.203 35.784 40.645 ;
     RECT  65.544 39.301 66.72 40.547 ;
     RECT  19.464 39.347 19.8 40.261 ;
     RECT  16.824 39.493 17.808 39.685 ;
     RECT  22.824 39.541 24 39.637 ;
     RECT  13.608 39.587 14.976 41.509 ;
     RECT  58.512 39.635 59.568 40.405 ;
     RECT  11.496 39.829 12.768 42.997 ;
     RECT  25.944 39.829 27.12 40.691 ;
     RECT  27.144 39.829 28.176 40.309 ;
     RECT  59.736 39.923 61.056 40.549 ;
     RECT  53.688 40.019 54.744 40.597 ;
     RECT  28.2 40.259 29.4 44.483 ;
     RECT  19.464 40.261 20.544 41.747 ;
     RECT  56.712 40.405 58.032 40.501 ;
     RECT  58.056 40.405 59.568 40.499 ;
     RECT  56.904 40.501 58.032 40.643 ;
     RECT  65.808 40.547 66.72 41.077 ;
     RECT  59.736 40.549 61.008 40.691 ;
     RECT  53.688 40.597 54.72 40.979 ;
     RECT  56.808 40.643 58.032 40.787 ;
     RECT  25.944 40.691 27.264 41.027 ;
     RECT  45.504 40.691 45.6 41.941 ;
     RECT  59.736 40.691 61.056 43.285 ;
     RECT  56.712 40.787 58.032 41.651 ;
     RECT  68.424 40.835 69.408 43.573 ;
     RECT  53.688 40.979 54.744 41.653 ;
     RECT  71.808 40.979 72.192 42.469 ;
     RECT  65.808 41.077 66.528 41.219 ;
     RECT  65.808 41.219 67.2 41.797 ;
     RECT  13.608 41.509 14.88 42.757 ;
     RECT  20.568 41.651 22.032 41.747 ;
     RECT  52.248 41.651 53.664 42.613 ;
     RECT  53.688 41.653 55.056 41.795 ;
     RECT  55.08 41.653 56.4 41.795 ;
     RECT  21.072 41.747 22.032 42.805 ;
     RECT  55.632 41.795 56.4 43.285 ;
     RECT  65.832 41.797 67.2 42.613 ;
     RECT  76.728 41.989 78 42.995 ;
     RECT  69.432 42.469 70.656 42.517 ;
     RECT  70.68 42.469 72.192 44.917 ;
     RECT  29.712 42.517 31.008 42.659 ;
     RECT  69.432 42.517 70.56 43.765 ;
     RECT  66.168 42.613 67.2 43.331 ;
     RECT  4.104 42.709 5.232 44.437 ;
     RECT  65.808 42.755 65.952 43.717 ;
     RECT  2.952 42.803 4.08 43.861 ;
     RECT  14.568 42.803 15.84 44.149 ;
     RECT  24.888 42.803 25.128 43.813 ;
     RECT  74.712 42.949 75.84 45.107 ;
     RECT  8.112 43.285 9.264 44.341 ;
     RECT  59.736 43.285 61.008 43.525 ;
     RECT  72.912 43.285 74.304 46.405 ;
     RECT  65.976 43.331 67.2 44.341 ;
     RECT  63.336 43.717 64.464 43.909 ;
     RECT  64.488 43.717 65.952 44.483 ;
     RECT  69.528 43.765 70.56 44.099 ;
     RECT  19.464 43.811 21.072 45.155 ;
     RECT  2.712 44.051 3.84 46.165 ;
     RECT  46.152 44.053 47.28 44.099 ;
     RECT  45.912 44.099 47.28 44.387 ;
     RECT  69.432 44.099 70.56 45.779 ;
     RECT  14.616 44.149 15.84 44.389 ;
     RECT  53.4 44.243 53.688 45.205 ;
     RECT  56.808 44.291 57 45.445 ;
     RECT  8.112 44.341 9.168 45.059 ;
     RECT  58.68 44.437 59.712 45.731 ;
     RECT  51.312 44.483 52.656 48.949 ;
     RECT  64.488 44.483 66.48 45.157 ;
     RECT  37.704 44.627 38.088 46.117 ;
     RECT  59.736 44.723 61.008 46.211 ;
     RECT  9.576 44.725 10.8 44.965 ;
     RECT  40.512 44.917 41.808 45.923 ;
     RECT  41.832 44.917 42.816 44.963 ;
     RECT  71.112 44.917 72.192 45.107 ;
     RECT  9.576 44.965 10.56 45.539 ;
     RECT  8.112 45.059 9.36 46.837 ;
     RECT  11.544 45.059 12.528 45.107 ;
     RECT  63.048 45.059 64.08 45.587 ;
     RECT  11.544 45.107 12.768 45.155 ;
     RECT  71.112 45.107 72.336 48.229 ;
     RECT  74.616 45.107 75.84 45.203 ;
     RECT  11.544 45.155 13.104 45.539 ;
     RECT  19.464 45.155 22.032 45.205 ;
     RECT  65.016 45.157 66.48 45.299 ;
     RECT  74.328 45.203 75.84 46.405 ;
     RECT  19.752 45.205 22.032 45.301 ;
     RECT  64.584 45.299 66.48 45.587 ;
     RECT  20.616 45.301 22.032 45.587 ;
     RECT  25.368 45.301 26.4 45.923 ;
     RECT  19.464 45.395 20.592 45.587 ;
     RECT  14.76 45.443 15.84 46.163 ;
     RECT  30.312 45.445 31.584 45.587 ;
     RECT  9.384 45.539 10.56 46.595 ;
     RECT  11.448 45.539 13.104 46.213 ;
     RECT  30.312 45.587 31.176 45.685 ;
     RECT  62.664 45.587 64.08 46.117 ;
     RECT  64.488 45.587 66.48 46.117 ;
     RECT  29.712 45.731 31.152 46.885 ;
     RECT  69.432 45.779 71.088 46.643 ;
     RECT  37.704 46.117 39.024 46.787 ;
     RECT  39.048 46.117 40.2 46.787 ;
     RECT  62.664 46.117 63.696 46.931 ;
     RECT  64.488 46.117 65.952 46.933 ;
     RECT  14.424 46.163 15.84 47.269 ;
     RECT  11.448 46.213 12.96 47.363 ;
     RECT  74.376 46.405 75.84 47.269 ;
     RECT  22.728 46.547 24 53.557 ;
     RECT  9.384 46.595 10.8 46.789 ;
     RECT  70.656 46.643 71.088 47.269 ;
     RECT  6.744 46.645 7.8 48.181 ;
     RECT  37.704 46.787 38.232 47.845 ;
     RECT  9.48 46.789 10.8 47.845 ;
     RECT  35.112 46.835 35.64 48.325 ;
     RECT  62.232 46.931 63.696 48.419 ;
     RECT  64.488 46.933 65.856 47.413 ;
     RECT  22.032 47.075 22.512 47.845 ;
     RECT  14.424 47.269 15.456 47.795 ;
     RECT  74.376 47.269 75.696 47.317 ;
     RECT  74.376 47.317 75.408 47.749 ;
     RECT  11.16 47.363 12.96 47.555 ;
     RECT  52.68 47.363 53.808 48.421 ;
     RECT  77.712 47.363 78 47.845 ;
     RECT  64.488 47.413 65.76 47.459 ;
     RECT  63.72 47.459 65.76 47.845 ;
     RECT  11.16 47.555 13.2 48.373 ;
     RECT  9.576 47.845 10.8 48.229 ;
     RECT  20.136 47.845 21.504 48.419 ;
     RECT  21.528 47.845 22.512 48.277 ;
     RECT  53.832 47.845 55.248 49.141 ;
     RECT  55.272 47.845 56.4 49.235 ;
     RECT  63.72 47.845 64.848 48.419 ;
     RECT  76.488 47.845 78 50.195 ;
     RECT  9.672 48.229 10.8 49.619 ;
     RECT  71.112 48.229 72.144 49.909 ;
     RECT  35.112 48.325 36.24 49.091 ;
     RECT  36.264 48.325 37.68 49.091 ;
     RECT  11.928 48.373 13.2 49.091 ;
     RECT  20.136 48.419 22.176 48.995 ;
     RECT  45.216 48.419 45.504 49.765 ;
     RECT  62.232 48.419 64.848 48.661 ;
     RECT  56.808 48.467 57.432 49.477 ;
     RECT  46.776 48.469 47.904 48.659 ;
     RECT  5.592 48.515 6.72 48.803 ;
     RECT  62.232 48.661 63.264 48.851 ;
     RECT  63.288 48.661 64.848 48.851 ;
     RECT  59.208 48.707 60.624 49.235 ;
     RECT  5.16 48.803 6.72 49.477 ;
     RECT  69 48.805 70.464 48.949 ;
     RECT  64.656 48.851 64.848 48.997 ;
     RECT  15.504 48.947 15.888 49.909 ;
     RECT  10.872 48.995 11.904 49.091 ;
     RECT  19.464 48.995 22.176 49.237 ;
     RECT  37.992 49.043 38.232 50.293 ;
     RECT  25.368 49.045 26.88 50.003 ;
     RECT  13.056 49.091 13.2 49.525 ;
     RECT  24.312 49.091 25.344 51.685 ;
     RECT  35.112 49.091 35.208 50.053 ;
     RECT  15.912 49.139 16.944 50.291 ;
     RECT  45.912 49.139 46.008 50.341 ;
     RECT  53.832 49.141 54.96 50.003 ;
     RECT  52.68 49.235 53.808 50.243 ;
     RECT  54.984 49.235 56.4 49.525 ;
     RECT  59.808 49.235 60.624 50.053 ;
     RECT  19.464 49.237 20.736 50.101 ;
     RECT  20.856 49.237 22.176 49.525 ;
     RECT  5.16 49.477 6.24 49.619 ;
     RECT  56.808 49.477 58.176 49.861 ;
     RECT  31.176 49.525 32.592 50.195 ;
     RECT  54.984 49.525 56.304 50.003 ;
     RECT  30.12 49.571 31.152 50.965 ;
     RECT  5.112 49.619 6.24 50.771 ;
     RECT  57.144 49.861 58.176 50.051 ;
     RECT  50.688 50.003 51 51.109 ;
     RECT  57 50.051 58.176 50.867 ;
     RECT  19.752 50.101 20.736 50.435 ;
     RECT  6.264 50.147 7.632 50.771 ;
     RECT  59.832 50.195 60.912 50.963 ;
     RECT  75.96 50.195 76.248 51.445 ;
     RECT  21.096 50.243 22.512 51.923 ;
     RECT  52.68 50.243 53.064 51.299 ;
     RECT  15.912 50.291 17.328 50.771 ;
     RECT  37.992 50.293 39.408 50.723 ;
     RECT  19.752 50.435 21.072 50.819 ;
     RECT  14.376 50.725 15.36 51.347 ;
     RECT  15.528 50.771 17.328 51.347 ;
     RECT  64.752 50.771 64.944 51.971 ;
     RECT  65.016 50.771 66.096 50.963 ;
     RECT  51.312 50.819 52.656 51.299 ;
     RECT  65.016 50.963 66.288 51.395 ;
     RECT  29.712 51.059 30.768 51.923 ;
     RECT  50.688 51.109 50.736 51.397 ;
     RECT  53.04 51.299 53.064 51.589 ;
     RECT  16.512 51.347 17.328 51.781 ;
     RECT  70.104 51.347 71.088 53.075 ;
     RECT  65.016 51.395 66.384 51.971 ;
     RECT  60.912 51.491 61.8 52.981 ;
     RECT  2.904 51.923 3.936 52.499 ;
     RECT  8.112 51.923 9.192 52.885 ;
     RECT  16.536 51.923 17.712 52.933 ;
     RECT  21.456 51.923 22.512 52.789 ;
     RECT  62.112 51.923 62.712 52.405 ;
     RECT  64.752 51.971 64.776 52.021 ;
     RECT  7.632 52.211 7.68 53.557 ;
     RECT  64.752 52.259 64.776 52.405 ;
     RECT  62.112 52.405 63.6 53.557 ;
     RECT  63.624 52.405 64.776 53.557 ;
     RECT  2.904 52.499 3.984 53.557 ;
     RECT  18.912 52.499 19.128 53.557 ;
     RECT  21.456 52.789 21.6 53.413 ;
     RECT  24.312 52.883 25.344 53.603 ;
     RECT  8.232 52.885 9.192 52.981 ;
     RECT  16.68 52.933 17.712 53.557 ;
     RECT  9.672 52.981 11.088 53.557 ;
     RECT  60.552 52.981 61.8 53.461 ;
     RECT  11.688 53.029 12.672 53.557 ;
     RECT  69.864 53.075 71.088 53.603 ;
     RECT  4.2 53.557 5.616 53.941 ;
     RECT  20.232 53.557 21.456 53.653 ;
     RECT  62.112 53.557 63.216 53.893 ;
     RECT  75.144 53.603 76.224 53.651 ;
     RECT  4.296 53.941 5.616 53.989 ;
     RECT  4.392 53.989 5.616 54.037 ;
  END
END ot_hgi_coll_fj_n1s0
END LIBRARY
